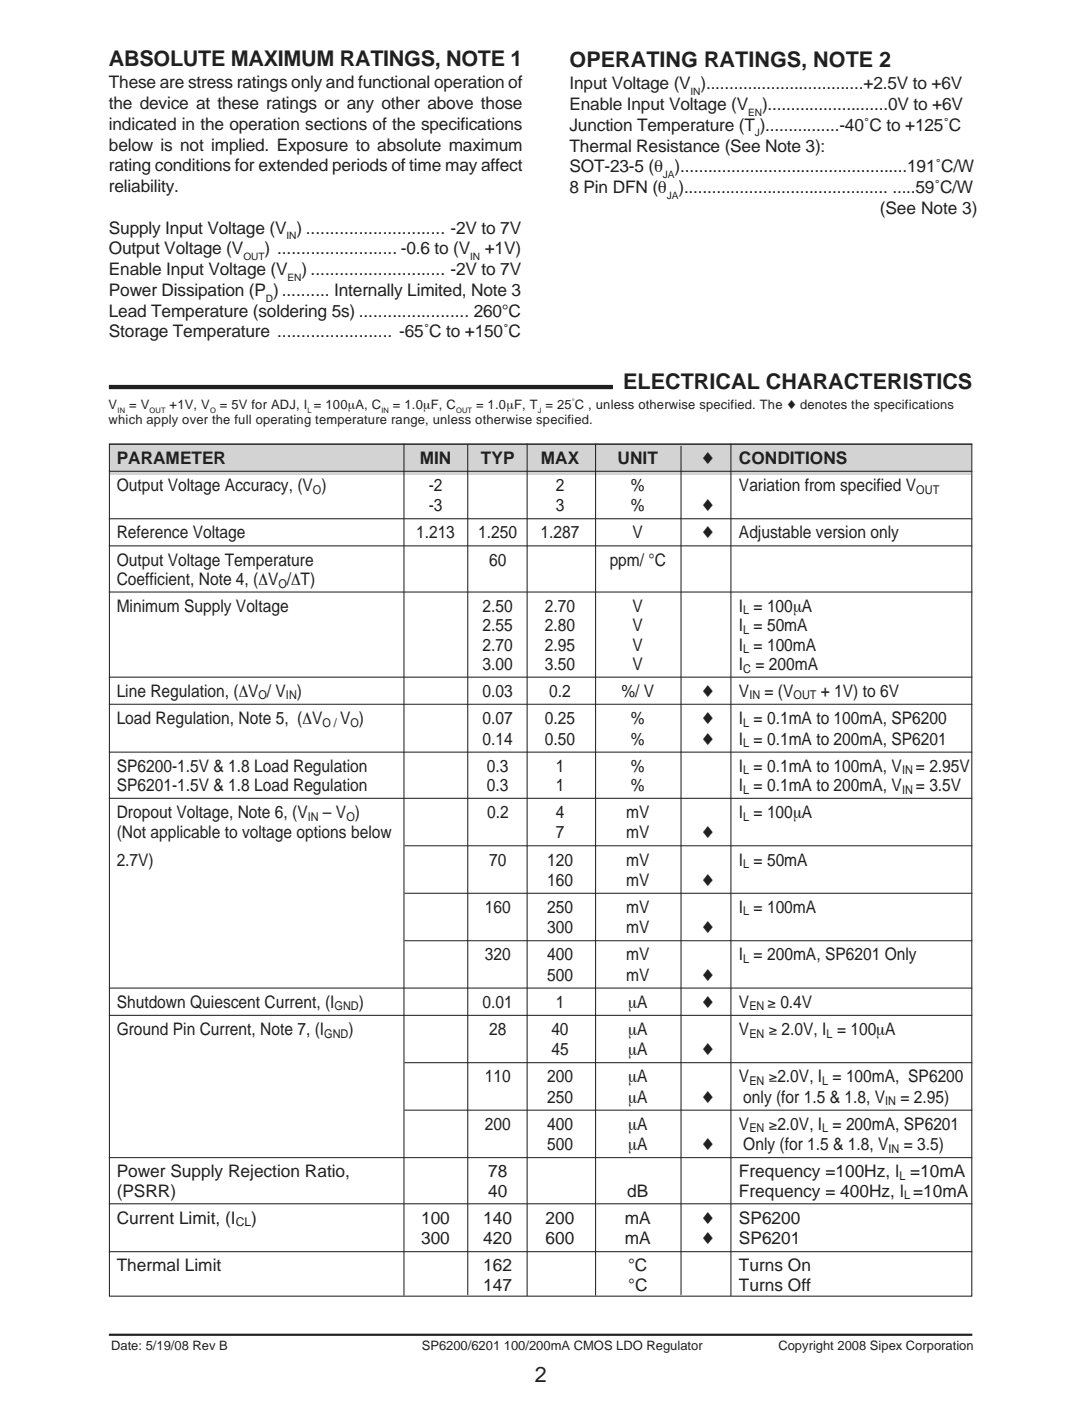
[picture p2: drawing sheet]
<svg xmlns="http://www.w3.org/2000/svg" width="178mm" height="229mm" viewBox="0 0 178 229" stroke-linecap="round" stroke-linejoin="round" font-family="sans-serif">
<defs><g id="words">
<g font-size="3.5" fill="#231f20">
<text x="17.8" y="10.8">ABSOLUTE MAXIMUM RATINGS, NOTE 1</text>
<text x="93" y="10.9">OPERATING RATINGS, NOTE 2</text>
<text x="101.7" y="63.5">ELECTRICAL CHARACTERISTICS</text>
<text x="87.3" y="225.6">2</text>
</g>
<g font-size="2.8" fill="#231f20">
<text x="17.8" y="14.4">These are stress ratings only and functional operation of</text>
<text x="17.8" y="17.8">the device at these ratings or any other above those</text>
<text x="93" y="14.6">Input Voltage (V )..................................+2.5V to +6V</text>
<text x="93" y="17.9">Enable Input Voltage (V</text>
<text x="124.4" y="17.9">)..........................0V to +6V</text>
<text x="17.8" y="21.2">indicated in the operation sections of the specifications</text>
<text x="93" y="21.3">Junction Temperature (T )................-40˚C to +125˚C</text>
<text x="17.8" y="24.6">below is not implied. Exposure to absolute maximum</text>
<text x="17.8" y="28">rating conditions for extended periods of time may affect</text>
<text x="93" y="24.7">Thermal Resistance (See Note 3):</text>
<text x="93" y="28.1">SOT-23-5 (θ ).................................................191˚C/W</text>
<text x="17.8" y="31.3">reliability.</text>
<text x="93" y="31.5">8 Pin DFN (θ )............................................ .....59˚C/W</text>
<text x="143.6" y="34.9">(See Note 3)</text>
<text x="17.8" y="41.5">Output Voltage (V</text>
<text x="17.8" y="38.1">Supply Input Voltage (V ) ............................. -2V to 7V</text>
<text x="43.2" y="41.5">) ......................... -0.6 to (V</text>
<text x="79.1" y="41.5">+1V)</text>
<text x="17.8" y="44.9">Enable Input Voltage (V</text>
<text x="49.2" y="44.9">) ............................ -2V to 7V</text>
<text x="17.8" y="48.3">Power Dissipation (P ).......... Internally Limited, Note 3</text>
<text x="17.8" y="51.7">Lead Temperature (soldering 5s) ....................... 260°C</text>
<text x="17.8" y="55.1">Storage Temperature ........................ -65˚C to +150˚C</text>
<text x="19" y="75.7">PARAMETER</text>
<text x="68.5" y="75.7">MIN</text>
<text x="78.5" y="75.7">TYP</text>
<text x="88.3" y="75.7">MAX</text>
<text x="100.8" y="75.7">UNIT</text>
<text x="114.5" y="75.7">♦</text>
<text x="120.6" y="75.7">CONDITIONS</text>
<text x="19" y="80.1">Output Voltage Accuracy, (V )</text>
<text x="70" y="83.4">-3</text>
<text x="70" y="80.1">-2</text>
<text x="90.7" y="83.4">3</text>
<text x="90.7" y="80.1">2</text>
<text x="103" y="83.4">%</text>
<text x="103" y="80.1">%</text>
<text x="114.5" y="83.4">♦</text>
<text x="120.7" y="80.1">Variation from specified V</text>
<text x="19" y="87.9">Reference Voltage</text>
<text x="67.9" y="87.9">1.213</text>
<text x="78.1" y="87.9">1.250</text>
<text x="88.3" y="87.9">1.287</text>
<text x="103.3" y="87.9">V</text>
<text x="114.5" y="87.9">♦</text>
<text x="120.6" y="87.9">Adjustable version only</text>
<text x="19" y="92.3">Output Voltage Temperature</text>
<text x="19.1" y="95.5">Coefficient, Note 4, (∆V /∆T)</text>
<text x="79.9" y="92.3">60</text>
<text x="99.5" y="92.3">ppm/ °C</text>
<text x="19" y="99.8">Minimum Supply Voltage</text>
<text x="78.8" y="99.8">2.50</text>
<text x="89" y="99.8">2.70</text>
<text x="103.3" y="99.8">V</text>
<text x="120.6" y="99.8">I = 100µA</text>
<text x="78.8" y="103">2.55</text>
<text x="78.8" y="106.2">2.70</text>
<text x="89" y="103">2.80</text>
<text x="89" y="106.2">2.95</text>
<text x="103.3" y="103">V</text>
<text x="103.3" y="106.2">V</text>
<text x="120.6" y="103">I = 50mA</text>
<text x="120.6" y="106.2">I = 100mA</text>
<text x="19" y="113.7">Line Regulation, (∆V / V )</text>
<text x="78.8" y="109.3">3.00</text>
<text x="78.8" y="113.7">0.03</text>
<text x="89" y="109.3">3.50</text>
<text x="89.7" y="113.7">0.2</text>
<text x="101.5" y="113.7">%/ V</text>
<text x="103.3" y="109.3">V</text>
<text x="114.5" y="113.7">♦</text>
<text x="120.6" y="109.3">I</text>
<text x="120.6" y="113.7">V</text>
<text x="123.3" y="109.3">= 200mA</text>
<text x="124.8" y="113.7">= (V</text>
<text x="134" y="113.7">+ 1V) to 6V</text>
<text x="19" y="118.1">Load Regulation, Note 5, (∆V</text>
<text x="55.5" y="118.1">V )</text>
<text x="78.8" y="118.1">0.07</text>
<text x="89" y="118.1">0.25</text>
<text x="103" y="118.1">%</text>
<text x="114.5" y="118.1">♦</text>
<text x="120.6" y="118.1">I = 0.1mA to 100mA, SP6200</text>
<text x="19" y="125.9">SP6200-1.5V &amp; 1.8 Load Regulation</text>
<text x="78.8" y="121.5">0.14</text>
<text x="79.5" y="125.9">0.3</text>
<text x="89" y="121.5">0.50</text>
<text x="90.7" y="125.9">1</text>
<text x="103" y="125.9">%</text>
<text x="103" y="121.5">%</text>
<text x="114.5" y="121.5">♦</text>
<text x="120.6" y="125.9">I = 0.1mA to 100mA, V</text>
<text x="120.6" y="121.5">I = 0.1mA to 200mA, SP6201</text>
<text x="149.5" y="125.9">= 2.95V</text>
<text x="19" y="129.1">SP6201-1.5V &amp; 1.8 Load Regulation</text>
<text x="79.5" y="129.1">0.3</text>
<text x="90.7" y="129.1">1</text>
<text x="103" y="129.1">%</text>
<text x="120.6" y="129.1">I = 0.1mA to 200mA, V</text>
<text x="149.5" y="129.1">= 3.5V</text>
<text x="19" y="136.8">(Not applicable to voltage options below</text>
<text x="19" y="133.5">Dropout Voltage, Note 6, (V</text>
<text x="52.7" y="133.5">– V )</text>
<text x="79.5" y="133.5">0.2</text>
<text x="90.7" y="136.8">7</text>
<text x="90.7" y="133.5">4</text>
<text x="102.2" y="136.8">mV</text>
<text x="102.2" y="133.5">mV</text>
<text x="114.5" y="136.8">♦</text>
<text x="120.6" y="133.5">I = 100µA</text>
<text x="19" y="141.2">2.7V)</text>
<text x="79.9" y="141.2">70</text>
<text x="89.3" y="141.2">120</text>
<text x="102.2" y="141.2">mV</text>
<text x="120.6" y="141.2">I = 50mA</text>
<text x="79.2" y="148.9">160</text>
<text x="89.3" y="148.9">250</text>
<text x="89.3" y="144.5">160</text>
<text x="102.2" y="148.9">mV</text>
<text x="102.2" y="144.5">mV</text>
<text x="114.5" y="144.5">♦</text>
<text x="120.6" y="148.9">I = 100mA</text>
<text x="89.3" y="152.3">300</text>
<text x="102.2" y="152.3">mV</text>
<text x="114.5" y="152.3">♦</text>
<text x="79.2" y="156.7">320</text>
<text x="89.3" y="156.7">400</text>
<text x="89.3" y="160">500</text>
<text x="102.2" y="156.7">mV</text>
<text x="102.2" y="160">mV</text>
<text x="114.5" y="160">♦</text>
<text x="120.6" y="156.7">I = 200mA, SP6201 Only</text>
<text x="19" y="164.4">Shutdown Quiescent Current, (I</text>
<text x="58.6" y="164.4">)</text>
<text x="78.8" y="164.4">0.01</text>
<text x="90.7" y="164.4">1</text>
<text x="102.6" y="164.4">µA</text>
<text x="114.5" y="164.4">♦</text>
<text x="120.6" y="164.4">V</text>
<text x="125.3" y="164.4">≥ 0.4V</text>
<text x="19" y="168.9">Ground Pin Current, Note 7, (I</text>
<text x="56.9" y="168.9">)</text>
<text x="79.9" y="168.9">28</text>
<text x="90" y="168.9">40</text>
<text x="90" y="172.2">45</text>
<text x="102.6" y="168.9">µA</text>
<text x="102.6" y="172.2">µA</text>
<text x="114.5" y="172.2">♦</text>
<text x="120.6" y="168.9">V</text>
<text x="125.5" y="168.9">≥ 2.0V, I = 100µA</text>
<text x="79.2" y="176.6">110</text>
<text x="89.3" y="176.6">200</text>
<text x="89.3" y="179.9">250</text>
<text x="102.6" y="176.6">µA</text>
<text x="102.6" y="179.9">µA</text>
<text x="114.5" y="179.9">♦</text>
<text x="120.6" y="176.6">V</text>
<text x="121.4" y="179.9">only (for 1.5 &amp; 1.8, V</text>
<text x="125.5" y="176.6">≥2.0V, I = 100mA, SP6200</text>
<text x="147" y="179.9">= 2.95)</text>
<text x="79.2" y="184.4">200</text>
<text x="89.3" y="184.4">400</text>
<text x="102.6" y="184.4">µA</text>
<text x="120.6" y="184.4">V</text>
<text x="125.5" y="184.4">≥2.0V, I = 200mA, SP6201</text>
<text x="89.3" y="187.7">500</text>
<text x="102.6" y="187.7">µA</text>
<text x="114.5" y="187.7">♦</text>
<text x="121.4" y="187.7">Only (for 1.5 &amp; 1.8, V</text>
<text x="147.6" y="187.7">= 3.5)</text>
<text x="19" y="192.1">Power Supply Rejection Ratio,</text>
<text x="19" y="195.3">(PSRR)</text>
<text x="79.7" y="192.1">78</text>
<text x="79.7" y="195.3">40</text>
<text x="102.4" y="195.3">dB</text>
<text x="120.6" y="192.1">Frequency =100Hz, I =10mA</text>
<text x="120.6" y="195.3">Frequency = 400Hz, I =10mA</text>
<text x="19" y="199.6">Current Limit, (I</text>
<text x="41" y="199.6">)</text>
<text x="68.7" y="199.6">100</text>
<text x="68.7" y="203">300</text>
<text x="78.9" y="199.6">140</text>
<text x="78.9" y="203">420</text>
<text x="89.1" y="199.6">200</text>
<text x="89.1" y="203">600</text>
<text x="102" y="199.6">mA</text>
<text x="102" y="203">mA</text>
<text x="114.5" y="199.6">♦</text>
<text x="114.5" y="203">♦</text>
<text x="120.6" y="199.6">SP6200</text>
<text x="120.6" y="203">SP6201</text>
<text x="19" y="207.5">Thermal Limit</text>
<text x="78.9" y="207.5">162</text>
<text x="102.6" y="207.5">°C</text>
<text x="120.6" y="207.5">Turns On</text>
<text x="78.9" y="210.6">147</text>
<text x="102.6" y="210.6">°C</text>
<text x="120.7" y="210.6">Turns Off</text>
</g>
<g font-size="2.1" fill="#231f20">
<text x="17.7" y="66.7">V</text>
<text x="17.7" y="69.3">which apply over the full operating temperature range, unless otherwise specified.</text>
<text x="21.1" y="66.7">= V</text>
<text x="27.7" y="66.7">+1V, V</text>
<text x="35.9" y="66.7">= 5V for ADJ, I = 100µA, C</text>
<text x="64.2" y="66.7">= 1.0µF, C</text>
<text x="77.7" y="66.7">= 1.0µF, T = 25 C , unless otherwise specified. The ♦ denotes the specifications</text>
<text x="18.1" y="220.2">Date: 5/19/08 Rev B</text>
<text x="68.9" y="220.2">SP6200/6201 100/200mA CMOS LDO Regulator</text>
<text x="127.1" y="220.2">Copyright 2008 Sipex Corporation</text>
</g>
<g font-size="2" fill="#231f20">
<text x="51.1" y="80.5">O</text>
<text x="149.6" y="80.5">OUT</text>
<text x="45.5" y="95.9">O</text>
<text x="121.3" y="100.2">L</text>
<text x="121.3" y="103.4">L</text>
<text x="121.3" y="106.6">L</text>
<text x="121.3" y="109.8">C</text>
<text x="42.2" y="114.1">O</text>
<text x="46.7" y="114.1">IN</text>
<text x="52.6" y="118.6">O /</text>
<text x="57.2" y="118.6">O</text>
<text x="121.3" y="118.6">L</text>
<text x="122.3" y="114.1">IN</text>
<text x="129.6" y="114.1">OUT</text>
<text x="121.3" y="121.9">L</text>
<text x="121.3" y="126.4">L</text>
<text x="121.3" y="129.5">L</text>
<text x="147.3" y="126.4">IN</text>
<text x="147.3" y="129.5">IN</text>
<text x="50.2" y="133.9">IN</text>
<text x="56.6" y="133.9">O</text>
<text x="121.3" y="133.9">L</text>
<text x="121.3" y="141.6">L</text>
<text x="121.3" y="149.4">L</text>
<text x="121.3" y="157.1">L</text>
<text x="54.6" y="164.9">GND</text>
<text x="122.3" y="164.9">EN</text>
<text x="52.9" y="169.3">GND</text>
<text x="122.3" y="169.3">EN</text>
<text x="135" y="169.3">L</text>
<text x="122.3" y="177">EN</text>
<text x="134.3" y="177">L</text>
<text x="122.3" y="184.8">EN</text>
<text x="134.3" y="184.8">L</text>
<text x="144.5" y="180.4">IN</text>
<text x="145.1" y="188.1">IN</text>
<text x="146.9" y="192.5">L</text>
<text x="147.6" y="195.7">L</text>
<text x="38.5" y="200.1">CL</text>
</g>
<g font-size="1.7" fill="#231f20">
<text x="112.8" y="15.5">IN</text>
<text x="122.1" y="18.9">EN</text>
<text x="123.2" y="22.3">J</text>
<text x="108.2" y="29">JA</text>
<text x="108.9" y="32.4">JA</text>
<text x="46.8" y="39.1">IN</text>
<text x="39.7" y="42.4">OUT</text>
<text x="46.9" y="45.8">EN</text>
<text x="76.8" y="42.4">IN</text>
<text x="43.4" y="49.2">D</text>
</g>
<g font-size="1.2" fill="#231f20">
<text x="93.4" y="66">°</text>
<text x="19.2" y="67.4">IN</text>
<text x="24.4" y="67.4">OUT</text>
<text x="34.3" y="67.4">O</text>
<text x="50.2" y="67.4">L</text>
<text x="62.3" y="67.4">IN</text>
<text x="74.5" y="67.4">OUT</text>
<text x="87.8" y="67.4">J</text>
</g>
</g></defs>
<path d="M17.8 217.8h140.9" fill="none" stroke="#231f20" stroke-width=".36"/>
<path d="M18 72.6h140.5v4.9h-140.5z" fill="#d1d3d4"/>
<g fill="none" stroke="#231f20" stroke-width=".17">
<path d="M17.8 72.5h140.9M17.8 76.9h140.9M17.9 72.5h140.8v139h-140.8zM66 72.4v139M76.4 72.5v138.8M86.1 72.4v139.1M97.2 72.4v139M111.2 72.7v138.6M119.3 72.4v139.1M17.8 84.6h140.9M17.8 89.1h140.9M17.8 96.6h140.9"/>
<path d="M17.8 110.5h140.9M17.8 114.9h140.9M17.8 122.7h140.9M17.8 130.3h140.9M66 138h92.7M66 145.8h92.7M66 153.5h92.7M17.8 161.2h140.9M17.8 165.7h140.9M66 173.4h92.7M17.8 188.9h140.9M17.8 196.4h140.9"/>
<path d="M66 181.1h92.7M17.8 204.2h140.9"/>
</g>
<path d="M17.8 63.2h82.3" fill="none" stroke="#231f20" stroke-width=".7" stroke-linecap="butt"/>
<use href="#words"/>
</svg>
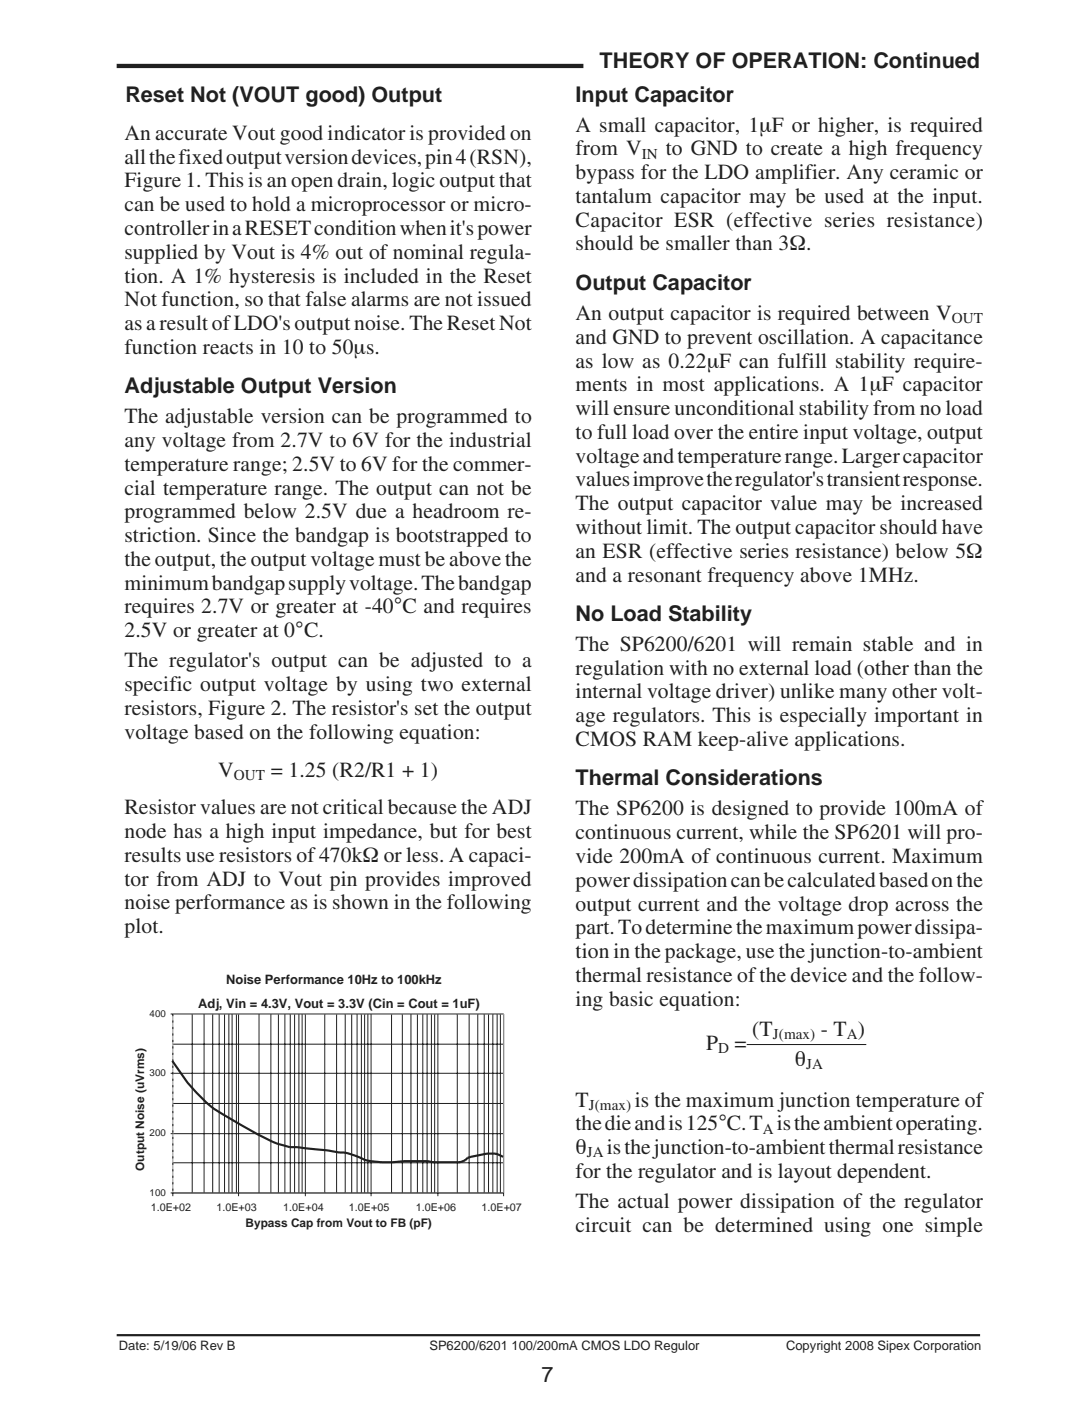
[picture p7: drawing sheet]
<svg xmlns="http://www.w3.org/2000/svg" width="178mm" height="229mm" viewBox="0 0 178 229" stroke-linecap="round" stroke-linejoin="round" font-family="sans-serif">
<defs><g id="words">
<g font-size="3.5" fill="#231f20">
<text x="97.9" y="11">THEORY OF OPERATION: Continued</text>
<text x="20.5" y="16.7">Reset Not (VOUT good) Output</text>
<text x="94" y="16.6">Input Capacitor</text>
<text x="20.3" y="22.8">An accurate Vout good indicator is provided on</text>
<text x="94" y="21.5">A small capacitor, 1µF or higher, is required</text>
<text x="20.3" y="26.7">all the fixed output version devices, pin 4 (RSN),</text>
<text x="94" y="25.4">from V</text>
<text x="94" y="29.2">bypass for the LDO amplifier. Any ceramic or</text>
<text x="108.7" y="25.4">to GND to create a high frequency</text>
<text x="20.3" y="30.6">Figure 1. This is an open drain, logic output that</text>
<text x="20.3" y="34.5">can be used to hold a microprocessor or micro-</text>
<text x="94" y="33.1">tantalum capacitor may be used at the input.</text>
<text x="20.3" y="38.3">controller in a RESET condition when it's power</text>
<text x="94" y="37">Capacitor ESR (effective series resistance)</text>
<text x="94" y="40.9">should be smaller than 3Ω.</text>
<text x="20.3" y="42.2">supplied by Vout is 4% out of nominal regula-</text>
<text x="20.3" y="46.1">tion. A 1% hysteresis is included in the Reset</text>
<text x="94" y="47.3">Output Capacitor</text>
<text x="20.3" y="50">Not function, so that false alarms are not issued</text>
<text x="20.3" y="53.8">as a result of LDO's output noise. The Reset Not</text>
<text x="94" y="52.2">An output capacitor is required between V</text>
<text x="20.3" y="57.7">function reacts in 10 to 50µs.</text>
<text x="94" y="56.1">and GND to prevent oscillation. A capacitance</text>
<text x="94" y="60">as low as 0.22µF can fulfill stability require-</text>
<text x="20.3" y="64.2">Adjustable Output Version</text>
<text x="94" y="63.8">ments in most applications. A 1µF capacitor</text>
<text x="20.3" y="69.1">The adjustable version can be programmed to</text>
<text x="94" y="67.7">will ensure unconditional stability from no load</text>
<text x="94" y="71.6">to full load over the entire input voltage, output</text>
<text x="20.3" y="72.9">any voltage from 2.7V to 6V for the industrial</text>
<text x="20.3" y="76.8">temperature range; 2.5V to 6V for the commer-</text>
<text x="94" y="75.5">voltage and temperature range. Larger capacitor</text>
<text x="20.3" y="80.7">cial temperature range. The output can not be</text>
<text x="94" y="79.4">values improve the regulator's transient response.</text>
<text x="94" y="83.2">The output capacitor value may be increased</text>
<text x="20.3" y="84.6">programmed below 2.5V due a headroom re-</text>
<text x="20.3" y="88.5">striction. Since the bandgap is bootstrapped to</text>
<text x="94" y="87.1">without limit. The output capacitor should have</text>
<text x="20.3" y="92.4">the output, the output voltage must be above the</text>
<text x="94" y="91">an ESR (effective series resistance) below 5Ω</text>
<text x="94" y="94.9">and a resonant frequency above 1MHz.</text>
<text x="20.3" y="96.2">minimum bandgap supply voltage. The bandgap</text>
<text x="20.3" y="100.1">requires 2.7V or greater at -40°C and requires</text>
<text x="94" y="101.3">No Load Stability</text>
<text x="20.3" y="104">2.5V or greater at 0°C.</text>
<text x="94" y="106.2">The SP6200/6201 will remain stable and in</text>
<text x="20.3" y="108.9">The regulator's output can be adjusted to a</text>
<text x="20.3" y="112.8">specific output voltage by using two external</text>
<text x="94" y="110.1">regulation with no external load (other than the</text>
<text x="94" y="114">internal voltage driver) unlike many other volt-</text>
<text x="20.3" y="116.6">resistors, Figure 2. The resistor's set the output</text>
<text x="94" y="117.8">age regulators. This is especially important in</text>
<text x="20.3" y="120.5">voltage based on the following equation:</text>
<text x="94" y="121.7">CMOS RAM keep-alive applications.</text>
<text x="35.6" y="126.7">V</text>
<text x="44.2" y="126.7">= 1.25 (R2/R1 + 1)</text>
<text x="94" y="128.1">Thermal Considerations</text>
<text x="20.3" y="132.9">Resistor values are not critical because the ADJ</text>
<text x="20.3" y="136.8">node has a high input impedance, but for best</text>
<text x="94" y="133.1">The SP6200 is designed to provide 100mA of</text>
<text x="94" y="136.9">continuous current, while the SP6201 will pro-</text>
<text x="20.3" y="140.6">results use resistors of 470kΩ or less. A capaci-</text>
<text x="94" y="140.8">vide 200mA of continuous current. Maximum</text>
<text x="20.3" y="144.5">tor from ADJ to Vout pin provides improved</text>
<text x="20.3" y="148.4">noise performance as is shown in the following</text>
<text x="94" y="144.7">power dissipation can be calculated based on the</text>
<text x="94" y="148.6">output current and the voltage drop across the</text>
<text x="20.3" y="152.3">plot.</text>
<text x="94" y="152.4">part. To determine the maximum power dissipa-</text>
<text x="94" y="156.3">tion in the package, use the junction-to-ambient</text>
<text x="94" y="160.2">thermal resistance of the device and the follow-</text>
<text x="94" y="164.1">ing basic equation:</text>
<text x="115.3" y="171.3">P</text>
<text x="119.9" y="171.3">=</text>
<text x="122.8" y="169">(T</text>
<text x="129.8" y="173.9">θ</text>
<text x="134" y="169">- T )</text>
<text x="94" y="180.6">T</text>
<text x="94" y="184.4">the die and is 125°C. T is the ambient operating.</text>
<text x="103.7" y="180.6">is the maximum junction temperature of</text>
<text x="94" y="188.3">θ</text>
<text x="99.1" y="188.3">is the junction-to-ambient thermal resistance</text>
<text x="94" y="192.2">for the regulator and is layout dependent.</text>
<text x="94" y="197.1">The actual power dissipation of the regulator</text>
<text x="94" y="201">circuit can be determined using one simple</text>
<text x="88.4" y="225.5">7</text>
</g>
<g font-size="2.5" fill="#231f20">
<text x="104.8" y="25.9">IN</text>
<text x="155.4" y="52.7">OUT</text>
<text x="38.2" y="127.2">OUT</text>
<text x="117.2" y="171.8">D</text>
<text x="126.2" y="169.5">J(max)</text>
<text x="138.3" y="169.5">A</text>
<text x="131.6" y="174.4">JA</text>
<text x="96.1" y="181.1">J(max)</text>
<text x="124.6" y="185">A</text>
<text x="95.8" y="188.8">JA</text>
</g>
<g font-size="2.1" fill="#231f20">
<text x="36.9" y="160.6">Noise Performance 10Hz to 100kHz</text>
<text x="32.4" y="164.5">Adj, Vin = 4.3V, Vout = 3.3V (Cin = Cout = 1uF)</text>
<text x="19.4" y="220.2">Date: 5/19/06 Rev B</text>
<text x="70.1" y="220.2">SP6200/6201 100/200mA CMOS LDO Regulor</text>
<text x="128.3" y="220.2">Copyright 2008 Sipex Corporation</text>
</g>
<g font-size="1.9" fill="#231f20">
<text x="23.5" y="191" transform="rotate(-90 23.5 191)">Output Noise (uVrms)</text>
<text x="40.1" y="200.2">Bypass Cap from Vout to FB (pF)</text>
</g>
<g font-size="1.8" fill="#231f20">
<text x="24.6" y="197.6">1.0E+02</text>
<text x="35.3" y="197.6">1.0E+03</text>
<text x="46.2" y="197.6">1.0E+04</text>
<text x="57" y="197.6">1.0E+05</text>
<text x="67.9" y="197.6">1.0E+06</text>
<text x="78.6" y="197.6">1.0E+07</text>
</g>
<g font-size="1.6" fill="#231f20">
<text x="24.4" y="165.9">400</text>
<text x="24.4" y="175.6">300</text>
<text x="24.4" y="185.4">200</text>
<text x="24.4" y="195.1">100</text>
</g>
</g></defs>
<path d="M19 217.9h141" fill="none" stroke="#231f20" stroke-width=".36"/>
<g fill="none" stroke="#231f20" stroke-width=".16">
<path d="M27.9 175.1h54.3M27.9 165.5h54.3v29.7M28.2 170.4h54M28.2 165.5v.3M28.2 166.5v.4M28.2 167.6v.3M28.2 168.6v.4M28.2 169.7v.3M28.2 170.7v.4M28.2 171.8v.3M28.2 172.8v.4M28.2 173.9v.3"/>
<path d="M28.2 175v.3M28.2 176v.4M28.2 177.1v.3M28.2 178.1v.4M28.2 179.2v.3M31.4 165.5v29.2M33.3 165.5v29.2M34.7 165.5v29.2M35.8 165.5v29.2M36.7 165.5v29.2M37.4 165.5v29.2M37.9 165.5v29.2"/>
<path d="M38.6 165.5v29.2M38.9 165.5v29.7M42.3 165.5v29.2M44.2 165.5v29.2M45.5 165.5v29.2M46.5 165.5v29.2M47.4 165.5v29.2M48.1 165.5v29.2M48.8 165.5v29.2M49.3 165.5v29.2M49.9 165.5v29.7M53 165.5v29.2"/>
<path d="M55 165.5v29.2M56.4 165.5v29.2M57.4 165.5v29.2M58.3 165.5v29.2M59 165.5v29.2M59.5 165.5v29.2M60.1 165.5v29.2M60.6 165.5v29.7M63.9 165.5v29.2M65.7 165.5v29.2M67.1 165.5v29.2M68.2 165.5v29.2"/>
<path d="M69 165.5v29.2M69.7 165.5v29.2M70.4 165.5v29.2M71 165.5v29.2M71.5 165.5v29.7M74.7 165.5v29.2M76.6 165.5v29.2M78 165.5v29.2M79.1 165.5v29.2M79.8 165.5v29.2M80.5 165.5v29.2M81.2 165.5v29.2"/>
<path d="M81.7 165.5v29.2M27.9 185h54.3M27.9 194.7h54.3M28.2 180.1h54M28.2 180.2v.4M28.2 181.3v.3M28.2 182.3v.4M28.2 183.4v.3M28.2 184.5v.3M28.2 185.5v.4M28.2 186.6v.3M28.2 187.6v.4"/>
<path d="M28.2 188.7v.3M28.2 190.8v.3M28.2 191.8v.4M28.2 192.9v.3M28.2 194v.3M28.2 194.7v.5M82.2 189.7h-54v.4"/>
</g>
<path d="M28.2 165.5h54v29.2h-54z" fill="none" stroke="#949698" stroke-width=".18"/>
<path d="M28.1 173.1a24.8 24.8 0 0 0 11.1 10.4l2.8 1.6a16.2 16.2 0 0 0 5.3 2.1h1.2l5 .5 1.9 .4a8.3 8.3 0 0 1 4.2 1.2 17.7 17.7 0 0 0 6.4 .2h3.8l.9 .1h4.4l1.8-.8 2.6-.6h1.4l1.2 .6" fill="none" stroke="#231f20" stroke-width=".35"/>
<path d="M19 10.8h76.2" fill="none" stroke="#231f20" stroke-width=".7" stroke-linecap="butt"/>
<path d="M121.9 170.4h19.5" fill="none" stroke="#231f20" stroke-width=".17"/>
<use href="#words"/>
</svg>
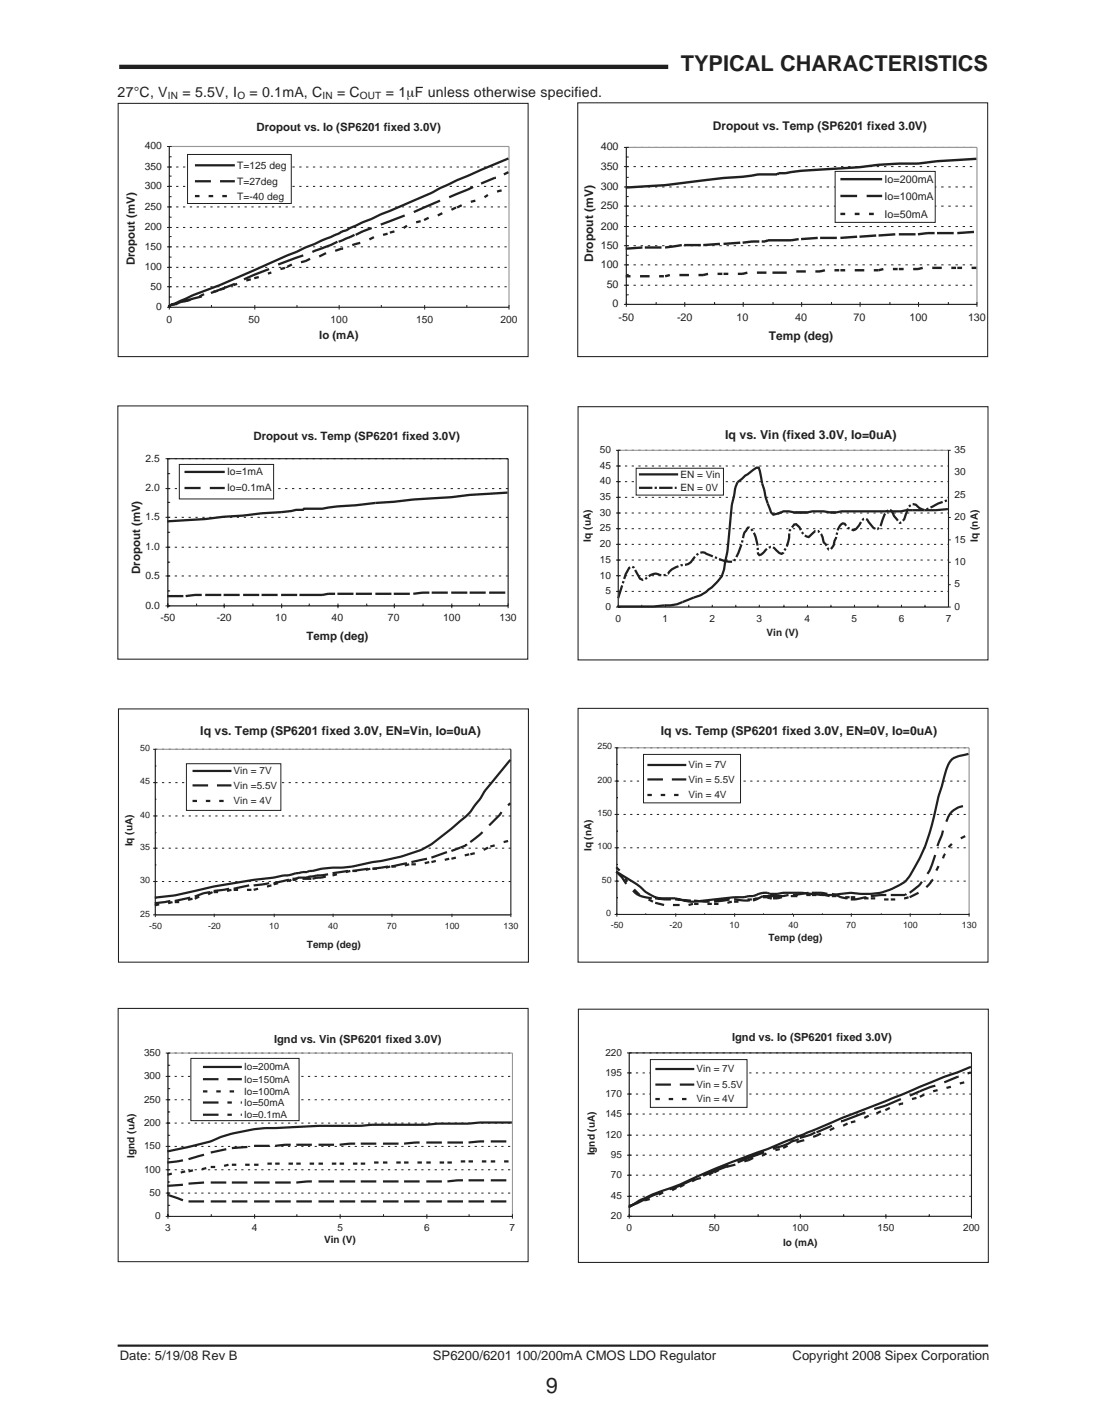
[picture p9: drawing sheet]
<svg xmlns="http://www.w3.org/2000/svg" width="178mm" height="229mm" viewBox="0 0 178 229" stroke-linecap="round" stroke-linejoin="round" font-family="sans-serif">
<defs><g id="words">
<g font-size="3.5" fill="#231f20">
<text x="110.2" y="11.5">TYPICAL CHARACTERISTICS</text>
<text x="88.4" y="225.5">9</text>
</g>
<g font-size="2.3" fill="#231f20">
<text x="19" y="15.7">27°C, V</text>
<text x="29.5" y="15.7">= 5.5V, I</text>
<text x="40.4" y="15.7">= 0.1mA, C</text>
<text x="54.6" y="15.7">= C</text>
<text x="62.5" y="15.7">= 1µF unless otherwise specified.</text>
</g>
<g font-size="2.1" fill="#231f20">
<text x="19.4" y="220.2">Date: 5/19/08 Rev B</text>
<text x="70.1" y="220.2">SP6200/6201 100/200mA CMOS LDO Regulator</text>
<text x="128.3" y="220.2">Copyright 2008 Sipex Corporation</text>
</g>
<g font-size="2" fill="#231f20">
<text x="117.4" y="71">Iq vs. Vin (fixed 3.0V, Io=0uA)</text>
<text x="32.4" y="119.1">Iq vs. Temp (SP6201 fixed 3.0V, EN=Vin, Io=0uA)</text>
<text x="107" y="119">Iq vs. Temp (SP6201 fixed 3.0V, EN=0V, Io=0uA)</text>
</g>
<g font-size="1.9" fill="#231f20">
<text x="115.4" y="21.1">Dropout vs. Temp (SP6201 fixed 3.0V)</text>
<text x="96.1" y="42.4" transform="rotate(-90 96.1 42.4)">Dropout (mV)</text>
<text x="124.5" y="55">Temp (deg)</text>
<text x="41" y="71.2">Dropout vs. Temp (SP6201 fixed 3.0V)</text>
<text x="22.7" y="93" transform="rotate(-90 22.7 93)">Dropout (mV)</text>
<text x="49.6" y="103.6">Temp (deg)</text>
</g>
<g font-size="1.8" fill="#231f20">
<text x="41.5" y="21.2">Dropout vs. Io (SP6201 fixed 3.0V)</text>
<text x="21.8" y="42.9" transform="rotate(-90 21.8 42.9)">Dropout (mV)</text>
<text x="51.7" y="54.8">Io (mA)</text>
<text x="44.4" y="168.8">Ignd vs. Vin (SP6201 fixed 3.0V)</text>
<text x="118.5" y="168.6">Ignd vs. Io (SP6201 fixed 3.0V)</text>
</g>
<g font-size="1.7" fill="#231f20">
<text x="23.4" y="27.5">350</text>
<text x="23.4" y="24.2">400</text>
<text x="38.4" y="27.3">T=125 deg</text>
<text x="38.4" y="29.9">T=27deg</text>
<text x="97.3" y="27.5">350</text>
<text x="97.3" y="24.4">400</text>
<text x="143.2" y="29.6">Io=200mA</text>
<text x="23.4" y="34">250</text>
<text x="23.4" y="30.6">300</text>
<text x="38.4" y="32.3">T=-40 deg</text>
<text x="97.3" y="33.9">250</text>
<text x="97.3" y="30.8">300</text>
<text x="143.2" y="32.3">Io=100mA</text>
<text x="143.2" y="35.2">Io=50mA</text>
<text x="23.4" y="40.4">150</text>
<text x="23.4" y="37.3">200</text>
<text x="97.3" y="40.3">150</text>
<text x="97.3" y="37.2">200</text>
<text x="23.4" y="43.7">100</text>
<text x="24.4" y="46.9">50</text>
<text x="97.3" y="43.4">100</text>
<text x="98.2" y="46.7">50</text>
<text x="25.3" y="50.2">0</text>
<text x="27" y="52.2">0</text>
<text x="40.2" y="52.2">50</text>
<text x="53.5" y="52.2">100</text>
<text x="67.4" y="52.2">150</text>
<text x="81" y="52.2">200</text>
<text x="99.2" y="49.8">0</text>
<text x="100.2" y="51.9">-50</text>
<text x="109.6" y="51.9">-20</text>
<text x="119.3" y="51.9">10</text>
<text x="128.8" y="51.9">40</text>
<text x="138.2" y="51.9">70</text>
<text x="147.3" y="51.9">100</text>
<text x="156.8" y="51.9">130</text>
<text x="23.5" y="74.7">2.5</text>
<text x="36.8" y="77">Io=1mA</text>
<text x="23.5" y="79.6">2.0</text>
<text x="36.8" y="79.6">Io=0.1mA</text>
<text x="23.5" y="89.1">1.0</text>
<text x="23.5" y="84.2">1.5</text>
<text x="23.5" y="93.7">0.5</text>
<text x="23.5" y="98.6">0.0</text>
<text x="26" y="100.6">-50</text>
<text x="35.1" y="100.6">-20</text>
<text x="44.6" y="100.6">10</text>
<text x="53.7" y="100.6">40</text>
<text x="62.8" y="100.6">70</text>
<text x="71.8" y="100.6">100</text>
<text x="80.9" y="100.6">130</text>
</g>
<g font-size="1.6" fill="#231f20">
<text x="27.2" y="16">IN</text>
<text x="38.4" y="16">O</text>
<text x="52.2" y="16">IN</text>
<text x="58.3" y="16">OUT</text>
<text x="97.1" y="75.9">45</text>
<text x="97.1" y="73.4">50</text>
<text x="110.2" y="77.3">EN = Vin</text>
<text x="154.6" y="77">30</text>
<text x="154.6" y="73.4">35</text>
<text x="97.1" y="83.5">30</text>
<text x="97.1" y="81">35</text>
<text x="97.1" y="78.4">40</text>
<text x="110.2" y="79.5">EN = 0V</text>
<text x="154.6" y="80.6">25</text>
<text x="95.7" y="87.7" transform="rotate(-90 95.7 87.7)">Iq (uA)</text>
<text x="97.1" y="88.6">20</text>
<text x="97.1" y="86">25</text>
<text x="154.6" y="87.9">15</text>
<text x="154.6" y="84.2">20</text>
<text x="158.3" y="87.7" transform="rotate(-90 158.3 87.7)">Iq (nA)</text>
<text x="97.1" y="93.7">10</text>
<text x="97.1" y="91.1">15</text>
<text x="154.6" y="95.1">5</text>
<text x="154.6" y="91.5">10</text>
<text x="98" y="98.7">0</text>
<text x="98" y="96.2">5</text>
<text x="99.7" y="100.7">0</text>
<text x="107.3" y="100.7">1</text>
<text x="114.9" y="100.7">2</text>
<text x="122.5" y="100.7">3</text>
<text x="130.3" y="100.7">4</text>
<text x="137.9" y="100.7">5</text>
<text x="145.5" y="100.7">6</text>
<text x="153.1" y="100.7">7</text>
<text x="154.6" y="98.7">0</text>
<text x="124.1" y="102.9">Vin (V)</text>
<text x="37.8" y="125.4">Vin = 7V</text>
<text x="111.5" y="124.4">Vin = 7V</text>
<text x="37.8" y="127.7">Vin =5.5V</text>
<text x="37.8" y="130.2">Vin = 4V</text>
<text x="111.5" y="126.7">Vin = 5.5V</text>
<text x="111.5" y="129.2">Vin = 4V</text>
<text x="21.5" y="137" transform="rotate(-90 21.5 137)">Iq (uA)</text>
<text x="95.8" y="137.8" transform="rotate(-90 95.8 137.8)">Iq (nA)</text>
<text x="49.7" y="153.5">Temp (deg)</text>
<text x="124.4" y="152.3">Temp (deg)</text>
<text x="23.3" y="170.9">350</text>
<text x="39.5" y="173.3">Io=200mA</text>
<text x="98" y="170.9">220</text>
<text x="112.8" y="173.6">Vin = 7V</text>
<text x="23.3" y="178.5">250</text>
<text x="23.3" y="174.7">300</text>
<text x="39.5" y="175.3">Io=150mA</text>
<text x="39.5" y="177.2">Io=100mA</text>
<text x="39.5" y="179">Io=50mA</text>
<text x="98" y="177.6">170</text>
<text x="98" y="174.2">195</text>
<text x="112.8" y="176.1">Vin = 5.5V</text>
<text x="112.8" y="178.5">Vin = 4V</text>
<text x="23.3" y="182.3">200</text>
<text x="39.5" y="181">Io=0.1mA</text>
<text x="98" y="184.2">120</text>
<text x="98" y="180.8">145</text>
<text x="21.8" y="187.4" transform="rotate(-90 21.8 187.4)">Ignd (uA)</text>
<text x="23.3" y="189.8">100</text>
<text x="23.3" y="186.1">150</text>
<text x="96.3" y="187.1" transform="rotate(-90 96.3 187.1)">Ignd (uA)</text>
<text x="98.9" y="190.7">70</text>
<text x="98.9" y="187.5">95</text>
<text x="24.2" y="193.6">50</text>
<text x="25.1" y="197.4">0</text>
<text x="98.9" y="197.4">20</text>
<text x="98.9" y="194.1">45</text>
<text x="26.7" y="199.4">3</text>
<text x="40.8" y="199.4">4</text>
<text x="52.5" y="201.3">Vin (V)</text>
<text x="54.6" y="199.4">5</text>
<text x="68.7" y="199.4">6</text>
<text x="82.5" y="199.4">7</text>
<text x="101.4" y="199.3">0</text>
<text x="114.8" y="199.3">50</text>
<text x="126.8" y="201.7">Io (mA)</text>
<text x="128.3" y="199.3">100</text>
<text x="142.1" y="199.3">150</text>
<text x="156" y="199.3">200</text>
</g>
<g font-size="1.4" fill="#231f20">
<text x="22.7" y="121.6">50</text>
<text x="96.7" y="121.3">250</text>
<text x="22.7" y="127">45</text>
<text x="96.7" y="126.7">200</text>
<text x="22.7" y="137.6">35</text>
<text x="22.7" y="132.4">40</text>
<text x="96.7" y="137.5">100</text>
<text x="96.7" y="132.1">150</text>
<text x="22.7" y="143">30</text>
<text x="97.5" y="142.9">50</text>
<text x="22.7" y="148.4">25</text>
<text x="98.2" y="148.3">0</text>
<text x="24.2" y="150.4">-50</text>
<text x="33.7" y="150.4">-20</text>
<text x="43.6" y="150.4">10</text>
<text x="53.1" y="150.4">40</text>
<text x="62.7" y="150.4">70</text>
<text x="72" y="150.4">100</text>
<text x="81.6" y="150.4">130</text>
<text x="98.9" y="150.3">-50</text>
<text x="108.4" y="150.3">-20</text>
<text x="118.2" y="150.3">10</text>
<text x="127.7" y="150.3">40</text>
<text x="137" y="150.3">70</text>
<text x="146.2" y="150.3">100</text>
<text x="155.8" y="150.3">130</text>
</g>
</g></defs>
<path d="M19 217.9h141" fill="none" stroke="#231f20" stroke-width=".36"/>
<path d="M19.1 16.7h66.4v41h-66.4zM93.6 16.6h66.3v41.1h-66.3zM19.1 65.7h66.4v41h-66.4zM93.6 65.8h66.4v41h-66.4z" fill="none" stroke="#231f20" stroke-width=".17"/>
<g fill="none" stroke="#231f20" stroke-width=".16">
<path d="M27 40h.8M27 36.8h.8M27 33.5h.8M27 30.2h.8M27 27h.8M27 23.7h.8M27.4 23.7v26.4M27.4 38.3h.4M27.4 35.2h.4M27.4 31.8h.4M27.4 28.5h.4M27.4 25.4h.4"/>
<path d="M28.5 40h.4M28.5 36.8h.4M28.5 33.5h.4M28.5 30.2h.4M28.5 27h.4M28.5 23.7h.4M29.6 40h.4M29.6 36.8h.4M29.6 33.5h.4M29.6 30.2h.4M29.6 27h.4M29.6 23.7h.4"/>
<path d="M30.7 40h.4M30.7 36.8h.4M30.7 33.5h.4M30.7 30.2h.4M30.7 27h.4M30.7 23.7h.4M31.8 40h.4M31.8 36.8h.4M31.8 33.5h.4M31.8 30.2h.4M31.8 27h.4M31.8 23.7h.4"/>
<path d="M33 40h.3M33 36.8h.3M33 33.5h.3M33 30.2h.3M33 27h.3M33 23.7h.3M34.1 40h.3M34.1 36.8h.3M34.1 33.5h.3M34.1 30.2h.3M34.1 27h.3M34.1 23.7h.3"/>
<path d="M35.2 40h.3M35.2 36.8h.3M35.2 33.5h.3M35.2 30.2h.3M35.2 27h.3M35.2 23.7h.3M36.3 40h.3M36.3 36.8h.3M36.3 33.5h.3M36.3 30.2h.3M36.3 27h.3M36.3 23.7h.3"/>
<path d="M37.4 40h.4M37.4 36.8h.4M37.4 33.5h.4M37.4 30.2h.4M37.4 27h.4M37.4 23.7h.4M38.5 40h.4M38.5 36.8h.4M38.5 33.5h.4M38.5 30.2h.4M38.5 27h.4M38.5 23.7h.4"/>
<path d="M39.6 40h.4M39.6 36.8h.4M39.6 33.5h.4M39.6 30.2h.4M39.6 27h.4M39.6 23.7h.4M40.7 40h.4M40.7 36.8h.4M40.7 33.5h.4M40.7 30.2h.4M40.7 27h.4M40.7 23.7h.4"/>
<path d="M41.8 40h.4M41.8 36.8h.4M41.8 33.5h.4M41.8 30.2h.4M41.8 27h.4M41.8 23.7h.4M42.9 40h.4M42.9 36.8h.4M42.9 33.5h.4M42.9 30.2h.4M42.9 27h.4M42.9 23.7h.4"/>
<path d="M44 40h.4M44 36.8h.4M44 33.5h.4M44 30.2h.4M44 27h.4M44 23.7h.4M45.1 40h.4M45.1 36.8h.4M45.1 33.5h.4M45.1 30.2h.4M45.1 27h.4M45.1 23.7h.4"/>
<path d="M46.2 40h.4M46.2 36.8h.4M46.2 33.5h.4M46.2 30.2h.4M46.2 27h.4M46.2 23.7h.4M47.4 40h.3M47.4 36.8h.3M47.4 33.5h.3M47.4 30.2h.3M47.4 27h.3M47.4 23.7h.3"/>
<path d="M48.5 40h.3M48.5 36.8h.3M48.5 33.5h.3M48.5 30.2h.3M48.5 27h.3M48.5 23.7h.3M49.6 40h.3M49.6 36.8h.3M49.6 33.5h.3M49.6 30.2h.3M49.6 27h.3M49.6 23.7h.3"/>
<path d="M50.7 40h.3M50.7 36.8h.3M50.7 33.5h.3M50.7 30.2h.3M50.7 27h.3M50.7 23.7h.3M51.8 40h.4M51.8 36.8h.4M51.8 33.5h.4M51.8 30.2h.4M51.8 27h.4M51.8 23.7h.4"/>
<path d="M52.9 40h.4M52.9 36.8h.4M52.9 33.5h.4M52.9 30.2h.4M52.9 27h.4M52.9 23.7h.4M54 40h.4M54 36.8h.4M54 33.5h.4M54 30.2h.4M54 27h.4M54 23.7h.4"/>
<path d="M55.1 40h.4M55.1 36.8h.4M55.1 33.5h.4M55.1 30.2h.4M55.1 27h.4M55.1 23.7h.4M56.2 40h.4M56.2 36.8h.4M56.2 33.5h.4M56.2 30.2h.4M56.2 27h.4M56.2 23.7h.4"/>
<path d="M57.3 40h.4M57.3 36.8h.4M57.3 33.5h.4M57.3 30.2h.4M57.3 27h.4M57.3 23.7h.4M58.4 40h.4M58.4 36.8h.4M58.4 33.5h.4M58.4 30.2h.4M58.4 27h.4M58.4 23.7h.4"/>
<path d="M59.5 40h.4M59.5 36.8h.4M59.5 33.5h.4M59.5 30.2h.4M59.5 27h.4M59.5 23.7h.4M60.6 40h.4M60.6 36.8h.4M60.6 33.5h.4M60.6 30.2h.4M60.6 27h.4M60.6 23.7h.4"/>
<path d="M61.7 40h.4M61.7 36.8h.4M61.7 33.5h.4M61.7 30.2h.4M61.7 27h.4M61.7 23.7h.4M62.9 40h.3M62.9 36.8h.3M62.9 33.5h.3M62.9 30.2h.3M62.9 27h.3M62.9 23.7h.3"/>
<path d="M64 40h.3M64 36.8h.3M64 33.5h.3M64 30.2h.3M64 27h.3M64 23.7h.3M65.1 40h.3M65.1 36.8h.3M65.1 33.5h.3M65.1 30.2h.3M65.1 27h.3M65.1 23.7h.3"/>
<path d="M66.2 40h.3M66.2 36.8h.3M66.2 33.5h.3M66.2 30.2h.3M66.2 27h.3M66.2 23.7h.3M67.3 40h.4M67.3 36.8h.4M67.3 33.5h.4M67.3 30.2h.4M67.3 27h.4M67.3 23.7h.4"/>
<path d="M68.4 40h.4M68.4 36.8h.4M68.4 33.5h.4M68.4 30.2h.4M68.4 27h.4M68.4 23.7h.4M69.5 40h.4M69.5 36.8h.4M69.5 33.5h.4M69.5 30.2h.4M69.5 27h.4M69.5 23.7h.4"/>
<path d="M70.6 40h.4M70.6 36.8h.4M70.6 33.5h.4M70.6 30.2h.4M70.6 27h.4M70.6 23.7h.4M71.7 40h.4M71.7 36.8h.4M71.7 33.5h.4M71.7 30.2h.4M71.7 27h.4M71.7 23.7h.4"/>
<path d="M72.8 40h.4M72.8 36.8h.4M72.8 33.5h.4M72.8 30.2h.4M72.8 27h.4M72.8 23.7h.4M73.9 40h.4M73.9 36.8h.4M73.9 33.5h.4M73.9 30.2h.4M73.9 27h.4M73.9 23.7h.4"/>
<path d="M75 40h.4M75 36.8h.4M75 33.5h.4M75 30.2h.4M75 27h.4M75 23.7h.4M76.1 40h.4M76.1 36.8h.4M76.1 33.5h.4M76.1 30.2h.4M76.1 27h.4M76.1 23.7h.4"/>
<path d="M77.3 40h.3M77.3 36.8h.3M77.3 33.5h.3M77.3 30.2h.3M77.3 27h.3M77.3 23.7h.3M78.4 40h.3M78.4 36.8h.3M78.4 33.5h.3M78.4 30.2h.3M78.4 27h.3M78.4 23.7h.3"/>
<path d="M79.5 40h.3M79.5 36.8h.3M79.5 33.5h.3M79.5 30.2h.3M79.5 27h.3M79.5 23.7h.3M80.6 40h.3M80.6 36.8h.3M80.6 33.5h.3M80.6 30.2h.3M80.6 27h.3M80.6 23.7h.3"/>
<path d="M81.7 40h.4M81.7 36.8h.4M81.7 33.5h.4M81.7 30.2h.4M81.7 27h.4M81.7 23.7h.4M27 46.4h.8M27 43.3h.8M27 49.7h.8M27.4 48.1h.4M27.4 44.9h.4M27.4 41.6h.4"/>
<path d="M28.5 46.4h.4M28.5 43.3h.4M29.6 46.4h.4M29.6 43.3h.4M30.7 46.4h.4M30.7 43.3h.4M31.8 46.4h.4M31.8 43.3h.4M33 46.4h.3M33 43.3h.3M34.1 46.4h.3M34.1 43.3h.3"/>
<path d="M34.2 49.4v.3M35.2 46.4h.3M35.2 43.3h.3M36.3 46.4h.3M36.3 43.3h.3M37.4 46.4h.4M37.4 43.3h.4M38.5 46.4h.4M38.5 43.3h.4M39.6 46.4h.4M39.6 43.3h.4M40.7 46.4h.4"/>
<path d="M40.7 43.3h.4M41.3 49.4v.7M41.8 46.4h.4M41.8 43.3h.4M42.9 46.4h.4M42.9 43.3h.4M44 46.4h.4M44 43.3h.4M45.1 46.4h.4M45.1 43.3h.4M46.2 46.4h.4M46.2 43.3h.4"/>
<path d="M47.4 46.4h.3M47.4 43.3h.3M48.1 49.4v.3M48.5 46.4h.3M48.5 43.3h.3M49.6 46.4h.3M49.6 43.3h.3M50.7 46.4h.3M50.7 43.3h.3M51.8 46.4h.4M51.8 43.3h.4M52.9 46.4h.4"/>
<path d="M52.9 43.3h.4M54 46.4h.4M54 43.3h.4M54.9 49.4v.7M55.1 46.4h.4M55.1 43.3h.4M56.2 46.4h.4M56.2 43.3h.4M57.3 46.4h.4M57.3 43.3h.4M58.4 46.4h.4M58.4 43.3h.4"/>
<path d="M59.5 46.4h.4M59.5 43.3h.4M60.6 46.4h.4M60.6 43.3h.4M61.7 46.4h.4M61.7 43.3h.4M61.7 49.4v.3M62.9 46.4h.3M62.9 43.3h.3M64 46.4h.3M64 43.3h.3M65.1 46.4h.3"/>
<path d="M65.1 43.3h.3M66.2 46.4h.3M66.2 43.3h.3M67.3 46.4h.4M67.3 43.3h.4M68.4 46.4h.4M68.4 43.3h.4M68.8 49.4v.7M69.5 46.4h.4M69.5 43.3h.4M70.6 46.4h.4M70.6 43.3h.4"/>
<path d="M71.7 46.4h.4M71.7 43.3h.4M72.8 46.4h.4M72.8 43.3h.4M73.9 46.4h.4M73.9 43.3h.4M75 46.4h.4M75 43.3h.4M75.6 49.4v.3M76.1 46.4h.4M76.1 43.3h.4M77.3 46.4h.3"/>
<path d="M77.3 43.3h.3M78.4 46.4h.3M78.4 43.3h.3M79.5 46.4h.3M79.5 43.3h.3M80.6 46.4h.3M80.6 43.3h.3M81.7 46.4h.4M81.7 43.3h.4M82.4 49.4v.7"/>
</g>
<path d="M27.4 49.7v-26h55v26" fill="none" stroke="#949698" stroke-width=".18"/>
<path d="M27.4 49.7h55" fill="none" stroke="#231f20" stroke-width=".18"/>
<g fill="none" stroke="#231f20" stroke-width=".37">
<path d="M54.6 39.1l-1.1 .6-2.9 1.1M57.4 38l-2.6 1.1M58.3 39.3l-1.3 .4M60.2 36.9l-2.6 1.1M60.6 38.4l-.8 .4M62.8 37.8l-.8 .2M63.9 37.5l-.8 .2M65.5 34.9l-3.8 1.5M65.9 36.5l-.6 .4M68.1 35.8l-.7 .2M69.4 35.3l-.7 .3M71.3 32.5l-4.3 1.8"/>
<path d="M71.6 34.5l-.7 .4M73.8 33.6l-.7 .4M74.8 33.2l-.8 .4M76.6 30.3l-3.9 1.6M77 32.5l-.8 .2M79 31.6l-.5 .3M80.3 28.8l-2.4 .9M81.2 30.8l-.7 .2M82.3 25.7l-8.3 3.5-2.7 1.3a80.7 80.7 0 0 1-9.6 4.2l-5 2.2-.6 .4-.7 .2-.6 .3-5.3 2.3-13.9 6-4.4 1.7-3.3 1.5M82.3 27.9l-.7 .3M27.9 49.3l-.6 .4M29.7 48.7h.4"/>
<path d="M30.1 48.7l-.9 .2-.8 .4h-.5M30.8 48.5l-.7 .2M32.7 48l-2.6 .7M33 47.6l-.7 .4M35.3 47.1l-.8 .2M35.6 46.9l-1.4 .5M36.4 46.7l-.8 .2M38 46l-2.4 .9M38.4 46l-.6 .1M40.6 45.2l-.7 .2M41.9 44.9l-.7 .1M43.6 43.6l-4.1 1.6"/>
<path d="M43.9 44.1l-.5 .2M46.2 43.4l-.8 .2M47.3 42.8l-.8 .4M49.1 41.3l-4.1 1.5M50.2 41.9l-.7 .4-.8 .2M52.8 41l-1.1 .5M55.6 40.2l-1.3 .4"/>
</g>
<path d="M30.4 25h16.8v7.9h-16.8z" fill="#fff" stroke="#231f20" stroke-width=".16"/>
<path d="M31.6 26.8h6.4M31.6 29.3h2.6M31.6 31.7h.7M33.8 31.7h.7M35.6 29.3h2.4M36 31.7h.7" fill="none" stroke="#231f20" stroke-width=".37"/>
<path d="M19.2 114.8h66.4v41h-66.4zM93.6 114.7h66.4v41.1h-66.4zM19.1 163.3h66.4v41h-66.4zM93.7 163.4h66.3v41h-66.3z" fill="none" stroke="#231f20" stroke-width=".17"/>
<g fill="none" stroke="#231f20" stroke-width=".16">
<path d="M101 39.8h.8M101 36.7h.8M101 33.4h.8M101 30.3h.8M101 27h.8M101 23.9h.8M101.4 23.9v25.8M101.4 38.2h.4M101.4 34.9h.4M101.4 31.8h.4M101.4 28.7h.4M101.4 25.4h.4"/>
<path d="M102.6 39.8h.4M102.6 36.7h.4M102.6 33.4h.4M102.6 30.3h.4M102.6 27h.4M102.6 23.9h.4M103.7 39.8h.4M103.7 36.7h.4M103.7 33.4h.4M103.7 30.3h.4M103.7 27h.4M103.7 23.9h.4"/>
<path d="M104.9 39.8h.4M104.9 36.7h.4M104.9 33.4h.4M104.9 30.3h.4M104.9 27h.4M104.9 23.9h.4M106.1 39.8h.3M106.1 36.7h.3M106.1 33.4h.3M106.1 30.3h.3M106.1 27h.3M106.1 23.9h.3"/>
<path d="M107.2 39.8h.4M107.2 36.7h.4M107.2 33.4h.4M107.2 30.3h.4M107.2 27h.4M107.2 23.9h.4M108.4 39.8h.4M108.4 36.7h.4M108.4 33.4h.4M108.4 30.3h.4M108.4 27h.4M108.4 23.9h.4"/>
<path d="M109.5 39.8h.4M109.5 36.7h.4M109.5 33.4h.4M109.5 30.3h.4M109.5 27h.4M109.5 23.9h.4M110.7 39.8h.4M110.7 36.7h.4M110.7 33.4h.4M110.7 30.3h.4M110.7 27h.4M110.7 23.9h.4"/>
<path d="M111.9 39.8h.3M111.9 36.7h.3M111.9 33.4h.3M111.9 30.3h.3M111.9 27h.3M111.9 23.9h.3M113 39.8h.4M113 36.7h.4M113 33.4h.4M113 30.3h.4M113 27h.4M113 23.9h.4"/>
<path d="M114.2 39.8h.4M114.2 36.7h.4M114.2 33.4h.4M114.2 30.3h.4M114.2 27h.4M114.2 23.9h.4M115.3 39.8h.4M115.3 36.7h.4M115.3 33.4h.4M115.3 30.3h.4M115.3 27h.4M115.3 23.9h.4"/>
<path d="M116.5 39.8h.4M116.5 36.7h.4M116.5 33.4h.4M116.5 30.3h.4M116.5 27h.4M116.5 23.9h.4M117.6 39.8h.4M117.6 36.7h.4M117.6 33.4h.4M117.6 30.3h.4M117.6 27h.4M117.6 23.9h.4"/>
<path d="M118.8 39.8h.4M118.8 36.7h.4M118.8 33.4h.4M118.8 30.3h.4M118.8 27h.4M118.8 23.9h.4M120 39.8h.3M120 36.7h.3M120 33.4h.3M120 30.3h.3M120 27h.3M120 23.9h.3"/>
<path d="M121.1 39.8h.4M121.1 36.7h.4M121.1 33.4h.4M121.1 30.3h.4M121.1 27h.4M121.1 23.9h.4M122.3 39.8h.4M122.3 36.7h.4M122.3 33.4h.4M122.3 30.3h.4M122.3 27h.4M122.3 23.9h.4"/>
<path d="M123.4 39.8h.4M123.4 36.7h.4M123.4 33.4h.4M123.4 30.3h.4M123.4 27h.4M123.4 23.9h.4M124.6 39.8h.4M124.6 36.7h.4M124.6 33.4h.4M124.6 30.3h.4M124.6 27h.4M124.6 23.9h.4"/>
<path d="M125.8 39.8h.3M125.8 36.7h.3M125.8 33.4h.3M125.8 30.3h.3M125.8 27h.3M125.8 23.9h.3M126.9 39.8h.4M126.9 36.7h.4M126.9 33.4h.4M126.9 30.3h.4M126.9 27h.4M126.9 23.9h.4"/>
<path d="M128.1 39.8h.4M128.1 36.7h.4M128.1 33.4h.4M128.1 30.3h.4M128.1 27h.4M128.1 23.9h.4M129.2 39.8h.4M129.2 36.7h.4M129.2 33.4h.4M129.2 30.3h.4M129.2 27h.4M129.2 23.9h.4"/>
<path d="M130.4 39.8h.4M130.4 36.7h.4M130.4 33.4h.4M130.4 30.3h.4M130.4 27h.4M130.4 23.9h.4M131.6 39.8h.3M131.6 36.7h.3M131.6 33.4h.3M131.6 30.3h.3M131.6 27h.3M131.6 23.9h.3"/>
<path d="M132.7 39.8h.4M132.7 36.7h.4M132.7 33.4h.4M132.7 30.3h.4M132.7 27h.4M132.7 23.9h.4M133.9 39.8h.4M133.9 36.7h.4M133.9 33.4h.4M133.9 30.3h.4M133.9 27h.4M133.9 23.9h.4"/>
<path d="M135 39.8h.4M135 36.7h.4M135 33.4h.4M135 30.3h.4M135 27h.4M135 23.9h.4M136.2 39.8h.4M136.2 36.7h.4M136.2 33.4h.4M136.2 30.3h.4M136.2 27h.4M136.2 23.9h.4"/>
<path d="M137.3 39.8h.4M137.3 36.7h.4M137.3 33.4h.4M137.3 30.3h.4M137.3 27h.4M137.3 23.9h.4M138.5 39.8h.4M138.5 36.7h.4M138.5 33.4h.4M138.5 30.3h.4M138.5 27h.4M138.5 23.9h.4"/>
<path d="M139.7 39.8h.3M139.7 36.7h.3M139.7 33.4h.3M139.7 30.3h.3M139.7 27h.3M139.7 23.9h.3M140.8 39.8h.4M140.8 36.7h.4M140.8 33.4h.4M140.8 30.3h.4M140.8 27h.4M140.8 23.9h.4"/>
<path d="M142 39.8h.4M142 36.7h.4M142 33.4h.4M142 30.3h.4M142 27h.4M142 23.9h.4M143.1 39.8h.4M143.1 36.7h.4M143.1 33.4h.4M143.1 30.3h.4M143.1 27h.4M143.1 23.9h.4"/>
<path d="M144.3 39.8h.4M144.3 36.7h.4M144.3 33.4h.4M144.3 30.3h.4M144.3 27h.4M144.3 23.9h.4M145.5 39.8h.3M145.5 36.7h.3M145.5 33.4h.3M145.5 30.3h.3M145.5 27h.3M145.5 23.9h.3"/>
<path d="M146.6 39.8h.4M146.6 36.7h.4M146.6 33.4h.4M146.6 30.3h.4M146.6 27h.4M146.6 23.9h.4M147.8 39.8h.4M147.8 36.7h.4M147.8 33.4h.4M147.8 30.3h.4M147.8 27h.4M147.8 23.9h.4"/>
<path d="M148.9 39.8h.4M148.9 36.7h.4M148.9 33.4h.4M148.9 30.3h.4M148.9 27h.4M148.9 23.9h.4M150.1 39.8h.4M150.1 36.7h.4M150.1 33.4h.4M150.1 30.3h.4M150.1 27h.4M150.1 23.9h.4"/>
<path d="M151.2 39.8h.4M151.2 36.7h.4M151.2 33.4h.4M151.2 30.3h.4M151.2 27h.4M151.2 23.9h.4M152.4 39.8h.4M152.4 36.7h.4M152.4 33.4h.4M152.4 30.3h.4M152.4 27h.4M152.4 23.9h.4"/>
<path d="M153.6 39.8h.4M153.6 36.7h.4M153.6 33.4h.4M153.6 30.3h.4M153.6 27h.4M153.6 23.9h.4M154.7 39.8h.4M154.7 36.7h.4M154.7 33.4h.4M154.7 30.3h.4M154.7 27h.4M154.7 23.9h.4"/>
<path d="M155.9 39.8h.4M155.9 36.7h.4M155.9 33.4h.4M155.9 30.3h.4M155.9 27h.4M155.9 23.9h.4M157 39.8h.4M157 36.7h.4M157 33.4h.4M157 30.3h.4M157 27h.4M157 23.9h.4"/>
<path d="M101 46.2h.8M101 42.9h.8M101 49.3h57.2M101.4 47.7h.4M101.4 44.4h.4M101.4 41.3h.4M102.6 46.2h.4M102.6 42.9h.4M103.7 46.2h.4M103.7 42.9h.4M104.9 46.2h.4M104.9 42.9h.4"/>
<path d="M106.1 46.2h.3M106.1 42.9h.3M106.3 48.9v.4M107.2 46.2h.4M107.2 42.9h.4M108.4 46.2h.4M108.4 42.9h.4M109.5 46.2h.4M109.5 42.9h.4M110.7 46.2h.4M110.7 42.9h.4M110.9 48.9v.8"/>
<path d="M111.9 46.2h.3M111.9 42.9h.3M113 46.2h.4M113 42.9h.4M114.2 46.2h.4M114.2 42.9h.4M115.3 46.2h.4M115.3 42.9h.4M115.7 48.9v.4M116.5 46.2h.4M116.5 42.9h.4M117.6 46.2h.4"/>
<path d="M117.6 42.9h.4M118.8 46.2h.4M118.8 42.9h.4M120 46.2h.3M120 42.9h.3M120.3 48.9v.8M121.1 46.2h.4M121.1 42.9h.4M122.3 46.2h.4M122.3 42.9h.4M123.4 46.2h.4M123.4 42.9h.4"/>
<path d="M124.6 46.2h.4M124.6 42.9h.4M125.2 48.9v.4M125.8 46.2h.3M125.8 42.9h.3M126.9 46.2h.4M126.9 42.9h.4M128.1 46.2h.4M128.1 42.9h.4M129.2 46.2h.4M129.2 42.9h.4M129.8 48.9v.8"/>
<path d="M130.4 46.2h.4M130.4 42.9h.4M131.6 46.2h.3M131.6 42.9h.3M132.7 46.2h.4M132.7 42.9h.4M133.9 46.2h.4M133.9 42.9h.4M134.6 48.9v.4M135 46.2h.4M135 42.9h.4M136.2 46.2h.4"/>
<path d="M136.2 42.9h.4M137.3 46.2h.4M137.3 42.9h.4M138.5 46.2h.4M138.5 42.9h.4M139.3 48.9v.8M139.7 46.2h.3M139.7 42.9h.3M140.8 46.2h.4M140.8 42.9h.4M142 46.2h.4M142 42.9h.4"/>
<path d="M143.1 46.2h.4M143.1 42.9h.4M144.1 48.9v.4M144.3 46.2h.4M144.3 42.9h.4M145.5 46.2h.3M145.5 42.9h.3M146.6 46.2h.4M146.6 42.9h.4M147.8 46.2h.4M147.8 42.9h.4M148.7 48.9v.8"/>
<path d="M148.9 46.2h.4M148.9 42.9h.4M150.1 46.2h.4M150.1 42.9h.4M151.2 46.2h.4M151.2 42.9h.4M152.4 46.2h.4M152.4 42.9h.4M153.6 46.2h.4M153.6 42.9h.4M153.6 48.9v.4M154.7 46.2h.4"/>
<path d="M154.7 42.9h.4M155.9 46.2h.4M155.9 42.9h.4M157 46.2h.4M157 42.9h.4M158.2 48.9v.8"/>
</g>
<path d="M101.4 23.9h56.8v25.4h-56.8z" fill="none" stroke="#949698" stroke-width=".19"/>
<g fill="none" stroke="#231f20" stroke-width=".39">
<path d="M110.4 39.7l-2.7 .4M110.8 39.7h2.7M116.6 39.5l-2.7 .2M119.9 39.3l-2.7 .2M123 39.1h-1.2l-1.5 .2M129.3 38.7l-1.1 .2h-3.9l-.4 .2h-.6M132.4 38.5l-2.7 .2M132.8 38.5h2.7M138.8 38.3l-2.7 .2M141.9 38.1l-2.7 .2M145 37.9l-2.7 .2M145.6 37.9h2.7"/>
<path d="M151.3 37.7h-1.1l-1.6 .2M151.7 37.7h2.7M157.7 37.5l-2.7 .2M158.1 25.7l-6.4 .4-3.1 .4h-3l-3.3 .2-3.1 .4-9.5 .6-2.5 .3h-1.2l-.1 .2h-3.1l-1 .2a182.3 182.3 0 0 0-14.1 1.6l-6.4 .4M101.3 44.7h.8M103.6 44.7h1.6M104 40.1l-2.7 .2M104.4 40.1h2.7M106.7 44.7h.8M108.5 44.5l-.8 .2M110 44.5h1.6M114.7 44.3l-.8 .2h-.8"/>
<path d="M116.2 44.3h.8M117.2 44.3h.7M121 44.1l-.7 .2h-.8M122.6 44.1h1.5M125.1 44.1h2.3M128.9 43.9h1.6M133.6 43.8l-.8 .1h-.8M135.1 43.8h.8M136.1 43.8h.8M138.4 43.8h1.6M143 43.6l-.7 .2h-.8M144.6 43.6h.8"/>
<path d="M145.6 43.6h.7M149.4 43.4l-.8 .2h-.7M151 43.4h1.5M154 43.4h.8M155 43.4h.8M157.3 43.4h.8"/>
</g>
<path d="M135.2 27.7h16.2v8.3h-16.2z" fill="#fff" stroke="#231f20" stroke-width=".16"/>
<path d="M136.1 29h6.7M136.1 31.7h2.7M136.1 34.6h.8M138.4 34.6h.8M140.3 31.7h2.5M140.7 34.6h.8" fill="none" stroke="#231f20" stroke-width=".39"/>
<g fill="none" stroke="#231f20" stroke-width=".16">
<path d="M26.8 79.1h.8M26.8 74.3h.8M27.2 74.3v24.2M27.2 76.7h.4M28.3 79.1h.4M28.3 74.3h.4M29.4 79.1h.4M29.4 74.3h.4M30.5 79.1h.4M30.5 74.3h.4M31.6 79.1h.4M31.6 74.3h.4"/>
<path d="M32.8 79.1h.3M32.8 74.3h.3M33.9 79.1h.4M33.9 74.3h.4M35 79.1h.4M35 74.3h.4M36.1 79.1h.4M36.1 74.3h.4M37.2 79.1h.4M37.2 74.3h.4M38.3 79.1h.4M38.3 74.3h.4"/>
<path d="M39.5 79.1h.3M39.5 74.3h.3M40.6 79.1h.4M40.6 74.3h.4M41.7 79.1h.4M41.7 74.3h.4M42.8 79.1h.4M42.8 74.3h.4M43.9 79.1h.4M43.9 74.3h.4M45.1 79.1h.3M45.1 74.3h.3"/>
<path d="M46.2 79.1h.3M46.2 74.3h.3M47.3 79.1h.4M47.3 74.3h.4M48.4 79.1h.4M48.4 74.3h.4M49.5 79.1h.4M49.5 74.3h.4M50.6 79.1h.4M50.6 74.3h.4M51.8 79.1h.3M51.8 74.3h.3"/>
<path d="M52.9 79.1h.3M52.9 74.3h.3M54 79.1h.4M54 74.3h.4M55.1 79.1h.4M55.1 74.3h.4M56.2 79.1h.4M56.2 74.3h.4M57.3 79.1h.4M57.3 74.3h.4M58.5 79.1h.3M58.5 74.3h.3"/>
<path d="M59.6 79.1h.3M59.6 74.3h.3M60.7 79.1h.4M60.7 74.3h.4M61.8 79.1h.4M61.8 74.3h.4M62.9 79.1h.4M62.9 74.3h.4M64 79.1h.4M64 74.3h.4M65.2 79.1h.3M65.2 74.3h.3"/>
<path d="M66.3 79.1h.3M66.3 74.3h.3M67.4 79.1h.4M67.4 74.3h.4M68.5 79.1h.4M68.5 74.3h.4M69.6 79.1h.4M69.6 74.3h.4M70.7 79.1h.4M70.7 74.3h.4M71.9 79.1h.3M71.9 74.3h.3"/>
<path d="M73 79.1h.3M73 74.3h.3M74.1 79.1h.4M74.1 74.3h.4M75.2 79.1h.4M75.2 74.3h.4M76.3 79.1h.4M76.3 74.3h.4M77.4 79.1h.4M77.4 74.3h.4M78.6 79.1h.3M78.6 74.3h.3"/>
<path d="M79.7 79.1h.3M79.7 74.3h.3M80.8 79.1h.4M80.8 74.3h.4M81.9 79.1h.4M81.9 74.3h.4M26.8 93.2h.8M26.8 88.6h.8M26.8 83.8h.8M26.8 98.1h55.5M27.2 95.7h.4M27.2 91h.4"/>
<path d="M27.2 86.2h.4M27.2 81.3h.4M28.3 93.2h.4M28.3 88.6h.4M28.3 83.8h.4M29.4 93.2h.4M29.4 88.6h.4M29.4 83.8h.4M30.5 93.2h.4M30.5 88.6h.4M30.5 83.8h.4M31.6 93.2h.4"/>
<path d="M31.6 88.6h.4M31.6 83.8h.4M31.8 97.7v.4M32.8 93.2h.3M32.8 88.6h.3M32.8 83.8h.3M33.9 93.2h.4M33.9 88.6h.4M33.9 83.8h.4M35 93.2h.4M35 88.6h.4M35 83.8h.4"/>
<path d="M36.1 93.2h.4M36.1 88.6h.4M36.1 83.8h.4M36.3 97.7v.8M37.2 93.2h.4M37.2 88.6h.4M37.2 83.8h.4M38.3 93.2h.4M38.3 88.6h.4M38.3 83.8h.4M39.5 93.2h.3M39.5 88.6h.3"/>
<path d="M39.5 83.8h.3M40.6 93.2h.4M40.6 88.6h.4M40.6 83.8h.4M41 97.7v.4M41.7 93.2h.4M41.7 88.6h.4M41.7 83.8h.4M42.8 93.2h.4M42.8 88.6h.4M42.8 83.8h.4M43.9 93.2h.4"/>
<path d="M43.9 88.6h.4M43.9 83.8h.4M45.1 93.2h.3M45.1 88.6h.3M45.1 83.8h.3M45.6 97.7v.8M46.2 93.2h.3M46.2 88.6h.3M46.2 83.8h.3M47.3 93.2h.4M47.3 88.6h.4M47.3 83.8h.4"/>
<path d="M48.4 93.2h.4M48.4 88.6h.4M48.4 83.8h.4M49.5 93.2h.4M49.5 88.6h.4M49.5 83.8h.4M50.1 97.7v.4M50.6 93.2h.4M50.6 88.6h.4M50.6 83.8h.4M51.8 93.2h.3M51.8 88.6h.3"/>
<path d="M51.8 83.8h.3M52.9 93.2h.3M52.9 88.6h.3M52.9 83.8h.3M54 93.2h.4M54 88.6h.4M54 83.8h.4M54.7 97.7v.8M55.1 93.2h.4M55.1 88.6h.4M55.1 83.8h.4M56.2 93.2h.4"/>
<path d="M56.2 88.6h.4M56.2 83.8h.4M57.3 93.2h.4M57.3 88.6h.4M57.3 83.8h.4M58.5 93.2h.3M58.5 88.6h.3M58.5 83.8h.3M59.4 97.7v.4M59.6 93.2h.3M59.6 88.6h.3M59.6 83.8h.3"/>
<path d="M60.7 93.2h.4M60.7 88.6h.4M60.7 83.8h.4M61.8 93.2h.4M61.8 88.6h.4M61.8 83.8h.4M62.9 93.2h.4M62.9 88.6h.4M62.9 83.8h.4M63.9 97.7v.8M64 93.2h.4M64 88.6h.4"/>
<path d="M64 83.8h.4M65.2 93.2h.3M65.2 88.6h.3M65.2 83.8h.3M66.3 93.2h.3M66.3 88.6h.3M66.3 83.8h.3M67.4 93.2h.4M67.4 88.6h.4M67.4 83.8h.4M68.5 93.2h.4M68.5 88.6h.4"/>
<path d="M68.5 83.8h.4M68.5 97.7v.4M69.6 93.2h.4M69.6 88.6h.4M69.6 83.8h.4M70.7 93.2h.4M70.7 88.6h.4M70.7 83.8h.4M71.9 93.2h.3M71.9 88.6h.3M71.9 83.8h.3M73 93.2h.3"/>
<path d="M73 88.6h.3M73 83.8h.3M73.2 97.7v.8M74.1 93.2h.4M74.1 88.6h.4M74.1 83.8h.4M75.2 93.2h.4M75.2 88.6h.4M75.2 83.8h.4M76.3 93.2h.4M76.3 88.6h.4M76.3 83.8h.4"/>
<path d="M77.4 93.2h.4M77.4 88.6h.4M77.4 83.8h.4M77.6 97.7v.4M78.6 93.2h.3M78.6 88.6h.3M78.6 83.8h.3M79.7 93.2h.3M79.7 88.6h.3M79.7 83.8h.3M80.8 93.2h.4M80.8 88.6h.4"/>
<path d="M80.8 83.8h.4M81.9 93.2h.4M81.9 88.6h.4M81.9 83.8h.4M82.3 97.7v.8"/>
</g>
<path d="M27.2 74.3h55.1v23.8" fill="none" stroke="#231f20" stroke-width=".19"/>
<path d="M27.2 74.3v23.8h55.1" fill="none" stroke="#949698" stroke-width=".19"/>
<g fill="none" stroke="#231f20" stroke-width=".37">
<path d="M82.2 79.8l-6.2 .3-2.9 .4-6.2 .4-3.1 .3-3 .2M27.1 96.5h2.6M32.7 96.3l-2.6 .2M33.2 96.3h2.6M36.2 96.3h2.6M39.4 96.3h2.6M42.4 96.3h2.6M45.5 82.9l-9.3 .8-3 .3-6.1 .4M45.5 96.3h2.6M54.3 96.1h-1.2l-.9 .2h-3.7M54.6 96.1h2.6M57.6 96.1h2.6"/>
<path d="M60.8 96.1h2.6M63.8 96.1h2.6M69.5 95.9l-2.6 .2M69.9 95.9h2.6M73.1 95.9h2.6M76 95.9h2.7M79.2 95.9h2.6"/>
</g>
<path d="M29 75.2h15.3v5.6h-15.3z" fill="#fff" stroke="#231f20" stroke-width=".16"/>
<path d="M29.9 76.4h6.5M29.9 79h2.6M34 79h2.4M60.8 81.4l-3.2 .4-3 .2-2.4 .4h-3l-.1 .1h-1.2l-2.4 .4" fill="none" stroke="#231f20" stroke-width=".37"/>
<path d="M100.1 96.9l1.2-3.9 .6-1.1 .5-.2 .2 .2 1 1.8 .5 .2 .3-.1a1.99 1.99 0 0 1 2.2-.8 1.42 1.42 0 0 0 1.8-.5 4.9 4.9 0 0 1 3-1.2l.5-.3a3.4 3.4 0 0 1 1.7-1.6l.5 .1 .9 .4a8.5 8.5 0 0 0 3 1l.9-.1a12.8 12.8 0 0 0 1.7-4.6l.5-.8a1.19 1.19 0 0 1 1.1 1 8.1 8.1 0 0 1 .6 3.2l.2 .3 .7-.5a1.52 1.52 0 0 1 1.4-.8l1.1 .9 .4 .2 .2-.2a7 7 0 0 0 1.1-3.6l.7-1h.3l.5 .4 .8 1.3 .4 .3 .4 .1 1-1h.5a2.61 2.61 0 0 1 .9 1.8l.8 1.2h.2l.6-.7 .1-.7 .3-.5a2.93 2.93 0 0 1 1.1-2.4l.3 .1a1.86 1.86 0 0 0 1.4 1 2.43 2.43 0 0 0 1.4-1.6l.5-.2 .3 .1 1 1.3 .7 .3 .5-.7 .7-1.8 .7-.7a1.19 1.19 0 0 1 .8 1.1l.9 1a.94 .94 0 0 0 .7-.6l.5-1.4a1.04 1.04 0 0 1 1.4-.9 1.77 1.77 0 0 0 1.7 .8l1.9-1 1.6-.6" fill="none" stroke="#231f20" stroke-width=".36" stroke-dasharray="2.2 .4 .4 .4" stroke-linecap="butt"/>
<g fill="none" stroke="#231f20" stroke-width=".16">
<path d="M99.8 78h.7M99.8 75.4h.7M99.8 72.9h.7M100.1 72.9v25.4M101.2 78h.4M101.2 75.4h.4M101.2 72.9h.4M102.3 78h.4M102.3 75.4h.4M102.3 72.9h.4M103.4 78h.3M103.4 75.4h.3"/>
<path d="M103.4 72.9h.3M104.5 78h.3M104.5 75.4h.3M104.5 72.9h.3M105.6 78h.3M105.6 75.4h.3M105.6 72.9h.3M106.6 78h.4M106.6 75.4h.4M106.6 72.9h.4M107.7 78h.4M107.7 75.4h.4"/>
<path d="M107.7 72.9h.4M108.8 78h.4M108.8 75.4h.4M108.8 72.9h.4M109.9 78h.4M109.9 75.4h.4M109.9 72.9h.4M111 78h.4M111 75.4h.4M111 72.9h.4M112.1 78h.3M112.1 75.4h.3"/>
<path d="M112.1 72.9h.3M113.2 78h.3M113.2 75.4h.3M113.2 72.9h.3M114.3 78h.3M114.3 75.4h.3M114.3 72.9h.3M115.3 78h.4M115.3 75.4h.4M115.3 72.9h.4M116.4 78h.4M116.4 75.4h.4"/>
<path d="M116.4 72.9h.4M117.5 78h.4M117.5 75.4h.4M117.5 72.9h.4M118.6 78h.4M118.6 75.4h.4M118.6 72.9h.4M119.7 78h.4M119.7 75.4h.4M119.7 72.9h.4M120.8 78h.3M120.8 75.4h.3"/>
<path d="M120.8 72.9h.3M121.9 78h.3M121.9 75.4h.3M121.9 72.9h.3M123 78h.3M123 75.4h.3M123 72.9h.3M124 78h.4M124 75.4h.4M124 72.9h.4M125.1 78h.4M125.1 75.4h.4"/>
<path d="M125.1 72.9h.4M126.2 78h.4M126.2 75.4h.4M126.2 72.9h.4M127.3 78h.4M127.3 75.4h.4M127.3 72.9h.4M128.4 78h.4M128.4 75.4h.4M128.4 72.9h.4M129.5 78h.3M129.5 75.4h.3"/>
<path d="M129.5 72.9h.3M130.6 78h.3M130.6 75.4h.3M130.6 72.9h.3M131.7 78h.3M131.7 75.4h.3M131.7 72.9h.3M132.7 78h.4M132.7 75.4h.4M132.7 72.9h.4M133.8 78h.4M133.8 75.4h.4"/>
<path d="M133.8 72.9h.4M134.9 78h.4M134.9 75.4h.4M134.9 72.9h.4M136 78h.4M136 75.4h.4M136 72.9h.4M137.1 78h.4M137.1 75.4h.4M137.1 72.9h.4M138.2 78h.3M138.2 75.4h.3"/>
<path d="M138.2 72.9h.3M139.3 78h.3M139.3 75.4h.3M139.3 72.9h.3M140.4 78h.3M140.4 75.4h.3M140.4 72.9h.3M141.4 78h.4M141.4 75.4h.4M141.4 72.9h.4M142.5 78h.4M142.5 75.4h.4"/>
<path d="M142.5 72.9h.4M143.6 78h.4M143.6 75.4h.4M143.6 72.9h.4M144.7 78h.4M144.7 75.4h.4M144.7 72.9h.4M145.8 78h.4M145.8 75.4h.4M145.8 72.9h.4M146.9 78h.3M146.9 75.4h.3"/>
<path d="M146.9 72.9h.3M148 78h.3M148 75.4h.3M148 72.9h.3M149.1 78h.3M149.1 75.4h.3M149.1 72.9h.3M150.1 78h.4M150.1 75.4h.4M150.1 72.9h.4M151.2 78h.4M151.2 75.4h.4"/>
<path d="M151.2 72.9h.4M152.3 78h.4M152.3 75.4h.4M152.3 72.9h.4M153.4 78h.2M153.4 75.4h.2M153.4 72.9h.6M153.6 72.9v25.4M99.8 95.7h.7M99.8 93.2h.7M99.8 90.7h.7M99.8 88.1h.7"/>
<path d="M99.8 85.6h.7M99.8 83.1h.7M99.8 80.5h.7M99.8 98.3h54.2M101.2 95.7h.4M101.2 93.2h.4M101.2 90.7h.4M101.2 88.1h.4M101.2 85.6h.4M101.2 83.1h.4M101.2 80.5h.4M102.3 95.7h.4"/>
<path d="M102.3 93.2h.4M102.3 90.7h.4M102.3 88.1h.4M102.3 85.6h.4M102.3 83.1h.4M102.3 80.5h.4M103.4 95.7h.3M103.4 93.2h.3M103.4 90.7h.3M103.4 88.1h.3M103.4 85.6h.3M103.4 83.1h.3"/>
<path d="M103.4 80.5h.3M103.9 97.9v.4M104.5 95.7h.3M104.5 93.2h.3M104.5 90.7h.3M104.5 88.1h.3M104.5 85.6h.3M104.5 83.1h.3M104.5 80.5h.3M105.6 95.7h.3M105.6 93.2h.3M105.6 90.7h.3"/>
<path d="M105.6 88.1h.3M105.6 85.6h.3M105.6 83.1h.3M105.6 80.5h.3M106.6 95.7h.4M106.6 93.2h.4M106.6 90.7h.4M106.6 88.1h.4M106.6 85.6h.4M106.6 83.1h.4M106.6 80.5h.4M107.7 95.7h.4"/>
<path d="M107.7 93.2h.4M107.7 90.7h.4M107.7 88.1h.4M107.7 85.6h.4M107.7 83.1h.4M107.7 80.5h.4M107.7 97.9v.4M108.8 95.7h.4M108.8 93.2h.4M108.8 90.7h.4M108.8 88.1h.4M108.8 85.6h.4"/>
<path d="M108.8 83.1h.4M108.8 80.5h.4M109.9 95.7h.4M109.9 93.2h.4M109.9 90.7h.4M109.9 88.1h.4M109.9 85.6h.4M109.9 83.1h.4M109.9 80.5h.4M111 95.7h.4M111 93.2h.4M111 90.7h.4"/>
<path d="M111 88.1h.4M111 85.6h.4M111 83.1h.4M111 80.5h.4M111.5 97.9v.4M112.1 95.7h.3M112.1 93.2h.3M112.1 90.7h.3M112.1 88.1h.3M112.1 85.6h.3M112.1 83.1h.3M112.1 80.5h.3"/>
<path d="M113.2 95.7h.3M113.2 93.2h.3M113.2 90.7h.3M113.2 88.1h.3M113.2 85.6h.3M113.2 83.1h.3M113.2 80.5h.3M114.3 95.7h.3M114.3 93.2h.3M114.3 90.7h.3M114.3 88.1h.3M114.3 85.6h.3"/>
<path d="M114.3 83.1h.3M114.3 80.5h.3M115.3 95.7h.4M115.3 93.2h.4M115.3 90.7h.4M115.3 88.1h.4M115.3 85.6h.4M115.3 83.1h.4M115.3 80.5h.4M115.3 97.9v.4M116.4 95.7h.4M116.4 93.2h.4"/>
<path d="M116.4 90.7h.4M116.4 88.1h.4M116.4 85.6h.4M116.4 83.1h.4M116.4 80.5h.4M117.5 95.7h.4M117.5 93.2h.4M117.5 90.7h.4M117.5 88.1h.4M117.5 85.6h.4M117.5 83.1h.4M117.5 80.5h.4"/>
<path d="M118.6 95.7h.4M118.6 93.2h.4M118.6 90.7h.4M118.6 88.1h.4M118.6 85.6h.4M118.6 83.1h.4M118.6 80.5h.4M119.1 97.9v.4M119.7 95.7h.4M119.7 93.2h.4M119.7 90.7h.4M119.7 88.1h.4"/>
<path d="M119.7 85.6h.4M119.7 83.1h.4M119.7 80.5h.4M120.8 95.7h.3M120.8 93.2h.3M120.8 90.7h.3M120.8 88.1h.3M120.8 85.6h.3M120.8 83.1h.3M120.8 80.5h.3M121.9 95.7h.3M121.9 93.2h.3"/>
<path d="M121.9 90.7h.3M121.9 88.1h.3M121.9 85.6h.3M121.9 83.1h.3M121.9 80.5h.3M123 95.7h.3M123 93.2h.3M123 90.7h.3M123 88.1h.3M123 85.6h.3M123 83.1h.3M123 80.5h.3"/>
<path d="M123 97.9v.4M124 95.7h.4M124 93.2h.4M124 90.7h.4M124 88.1h.4M124 85.6h.4M124 83.1h.4M124 80.5h.4M125.1 95.7h.4M125.1 93.2h.4M125.1 90.7h.4M125.1 88.1h.4"/>
<path d="M125.1 85.6h.4M125.1 83.1h.4M125.1 80.5h.4M126.2 95.7h.4M126.2 93.2h.4M126.2 90.7h.4M126.2 88.1h.4M126.2 85.6h.4M126.2 83.1h.4M126.2 80.5h.4M126.9 97.9v.4M127.3 95.7h.4"/>
<path d="M127.3 93.2h.4M127.3 90.7h.4M127.3 88.1h.4M127.3 85.6h.4M127.3 83.1h.4M127.3 80.5h.4M128.4 95.7h.4M128.4 93.2h.4M128.4 90.7h.4M128.4 88.1h.4M128.4 85.6h.4M128.4 83.1h.4"/>
<path d="M128.4 80.5h.4M129.5 95.7h.3M129.5 93.2h.3M129.5 90.7h.3M129.5 88.1h.3M129.5 85.6h.3M129.5 83.1h.3M129.5 80.5h.3M130.6 95.7h.3M130.6 93.2h.3M130.6 90.7h.3M130.6 88.1h.3"/>
<path d="M130.6 85.6h.3M130.6 83.1h.3M130.6 80.5h.3M130.8 97.9v.4M131.7 95.7h.3M131.7 93.2h.3M131.7 90.7h.3M131.7 88.1h.3M131.7 85.6h.3M131.7 83.1h.3M131.7 80.5h.3M132.7 95.7h.4"/>
<path d="M132.7 93.2h.4M132.7 90.7h.4M132.7 88.1h.4M132.7 85.6h.4M132.7 83.1h.4M132.7 80.5h.4M133.8 95.7h.4M133.8 93.2h.4M133.8 90.7h.4M133.8 88.1h.4M133.8 85.6h.4M133.8 83.1h.4"/>
<path d="M133.8 80.5h.4M134.6 97.9v.4M134.9 95.7h.4M134.9 93.2h.4M134.9 90.7h.4M134.9 88.1h.4M134.9 85.6h.4M134.9 83.1h.4M134.9 80.5h.4M136 95.7h.4M136 93.2h.4M136 90.7h.4"/>
<path d="M136 88.1h.4M136 85.6h.4M136 83.1h.4M136 80.5h.4M137.1 95.7h.4M137.1 93.2h.4M137.1 90.7h.4M137.1 88.1h.4M137.1 85.6h.4M137.1 83.1h.4M137.1 80.5h.4M138.2 95.7h.3"/>
<path d="M138.2 93.2h.3M138.2 90.7h.3M138.2 88.1h.3M138.2 85.6h.3M138.2 83.1h.3M138.2 80.5h.3M138.4 97.9v.4M139.3 95.7h.3M139.3 93.2h.3M139.3 90.7h.3M139.3 88.1h.3M139.3 85.6h.3"/>
<path d="M139.3 83.1h.3M139.3 80.5h.3M140.4 95.7h.3M140.4 93.2h.3M140.4 90.7h.3M140.4 88.1h.3M140.4 85.6h.3M140.4 83.1h.3M140.4 80.5h.3M141.4 95.7h.4M141.4 93.2h.4M141.4 90.7h.4"/>
<path d="M141.4 88.1h.4M141.4 85.6h.4M141.4 83.1h.4M141.4 80.5h.4M142.2 97.9v.4M142.5 95.7h.4M142.5 93.2h.4M142.5 90.7h.4M142.5 88.1h.4M142.5 85.6h.4M142.5 83.1h.4M142.5 80.5h.4"/>
<path d="M143.6 95.7h.4M143.6 93.2h.4M143.6 90.7h.4M143.6 88.1h.4M143.6 85.6h.4M143.6 83.1h.4M143.6 80.5h.4M144.7 95.7h.4M144.7 93.2h.4M144.7 90.7h.4M144.7 88.1h.4M144.7 85.6h.4"/>
<path d="M144.7 83.1h.4M144.7 80.5h.4M145.8 95.7h.4M145.8 93.2h.4M145.8 90.7h.4M145.8 88.1h.4M145.8 85.6h.4M145.8 83.1h.4M145.8 80.5h.4M146 97.9v.4M146.9 95.7h.3M146.9 93.2h.3"/>
<path d="M146.9 90.7h.3M146.9 88.1h.3M146.9 85.6h.3M146.9 83.1h.3M146.9 80.5h.3M148 95.7h.3M148 93.2h.3M148 90.7h.3M148 88.1h.3M148 85.6h.3M148 83.1h.3M148 80.5h.3"/>
<path d="M149.1 95.7h.3M149.1 93.2h.3M149.1 90.7h.3M149.1 88.1h.3M149.1 85.6h.3M149.1 83.1h.3M149.1 80.5h.3M149.8 97.9v.4M150.1 95.7h.4M150.1 93.2h.4M150.1 90.7h.4M150.1 88.1h.4"/>
<path d="M150.1 85.6h.4M150.1 83.1h.4M150.1 80.5h.4M151.2 95.7h.4M151.2 93.2h.4M151.2 90.7h.4M151.2 88.1h.4M151.2 85.6h.4M151.2 83.1h.4M151.2 80.5h.4M152.3 95.7h.4M152.3 93.2h.4"/>
<path d="M152.3 90.7h.4M152.3 88.1h.4M152.3 85.6h.4M152.3 83.1h.4M152.3 80.5h.4M153.4 95.7h.2M153.4 93.2h.2M153.4 90.7h.2M153.4 88.1h.2M153.4 85.6h.2M153.4 83.1h.2M153.4 80.5h.2"/>
<path d="M153.6 94.7h.4M153.6 91h.4M153.6 87.4h.4M153.6 83.8h.4"/>
</g>
<path d="M153.6 72.9h-53.5v25.4h53.5" fill="none" stroke="#949698" stroke-width=".18"/>
<path d="M153.6 72.9v25.4" fill="none" stroke="#231f20" stroke-width=".18"/>
<path d="M119.4 78.1l-.3 .9-.6 2.7-.7 7.6-.4 1.6M123.4 78.3l.9 3.2M107.6 98l-1.8 .2h-5.8M112.3 96.7l-1.8 .8M117.2 90.8l.4 .1M126.5 83l-.6 .1M128.7 83h2M134.5 83h.9M147.7 82.6h2" fill="none" stroke="#231f20" stroke-width=".36"/>
<path d="M103 75.8h14.2v4.4h-14.2z" fill="#fff" stroke="#231f20" stroke-width=".16"/>
<g fill="none" stroke="#231f20" stroke-width=".36">
<path d="M103.5 76.8h6.3M119.4 78.1l2.6-2 .5-.4h.4l.5 2.6M110.5 97.5l-.9 .3-1.1 .2h-.9M117.4 90.9l-.2 1.3-.3 1.1a10.3 10.3 0 0 1-3.5 3.1l-1.1 .3M124.3 81.5l.6 1.5 .3 .3 .7-.2a2.95 2.95 0 0 1 2.8-.1h2l.9-.2h1.8l1.1 .2h.9l.9-.2h9.6l.9-.2h.9M153.5 82.4l-2 .2h-1.8M65.9 139.7l-2.5 .6h.7M66.3 139.9l-.8 .2M66.6 139.9h.7M69.1 139l-2.5 .6M69.5 139.6l-.7 .1M70.6 139.4l-.7 .2"/>
<path d="M72.4 137.9l-2.5 .9M72.7 139l-.7 .2M73.8 138.8l-.7 .2M75.6 136.7l-.2 .2-2.3 .9M76 138.3l-.7 .2M76.9 138.1l-.7 .2M78.1 134.7l-1.9 1.6M79 137.2l-.7 .4M80.1 136.9l-.7 .2M81.2 131.5l-.2 .3-1.8 1.8M82.3 136.2l-.7 .1M82.6 123l-4.1 5.1-.7 1.2-1.6 2.2-3.1 2.7-3.2 2.5-1.7 .9-3.2 1.1-7.9 1.6-5.1 .3-1.4 .4h-.5l-.4 .2h-.7l-2.4 .5h-.7l-1.6 .4a104.9 104.9 0 0 0-16 2.9l-3.2 .3"/>
<path d="M82.6 130l-.3 .4M25.8 146.4l-.7 .2M27.6 145.9l-2.5 .3M27.9 146l-.7 .2M28.3 146h.7M30.8 145.3l-2.5 .6M31.2 145.5l-.7 .2M32.3 145.1l-.8 .4M34.1 144.4l-1.1 .2-1.5 .5M34.4 144.4l-.7 .4M34.6 144.4h.7M37.1 143.9l-2.5 .3"/>
<path d="M37.5 144.1l-.7 .1M37.8 144.1h.8M40 144.1h.7M40.4 143.3l-2.6 .6M41.8 143.9l-.7 .2M43.6 143l-2.5 .3M44 143.3l-.8 .2M45 143l-.7 .2M46.8 142.4l-2.5 .6M47.2 142.4l-.7 .2M48.1 142.3l-.2 .1h-.5M49 142.3h1.4"/>
<path d="M52.8 141.9l-2.2 .4M53.1 141.5l-3 .4-.4 .2h-1.4l-.4 .2h-.5M54.6 141.5l-.8 .2M56.4 141l-2.6 .4M56.7 141l-.7 .2M59.6 140.6l-2.5 .4h.7M60 140.6l-.8 .2M62.8 140.3l-2.5 .3h.7M63.2 140.3l-.7 .2"/>
</g>
<path d="M103.5 79h6.1" fill="none" stroke="#231f20" stroke-width=".36" stroke-dasharray="2.2 .4 .4 .4" stroke-linecap="butt"/>
<g fill="none" stroke="#231f20" stroke-width=".16">
<path d="M24.8 137.3h.7M24.8 132.1h.7M24.8 126.7h.7M24.8 121.3h.7M25.1 121.3v27.2M25.1 134.8h.2M25.1 129.4h.2M25.1 124h.2M26.2 137.3h.4M26.2 132.1h.4M26.2 126.7h.4M26.2 121.3h.4"/>
<path d="M27.3 137.3h.4M27.3 132.1h.4M27.3 126.7h.4M27.3 121.3h.4M28.4 137.3h.3M28.4 132.1h.3M28.4 126.7h.3M28.4 121.3h.3M29.5 137.3h.3M29.5 132.1h.3M29.5 126.7h.3M29.5 121.3h.3"/>
<path d="M30.5 137.3h.4M30.5 132.1h.4M30.5 126.7h.4M30.5 121.3h.4M31.6 137.3h.4M31.6 132.1h.4M31.6 126.7h.4M31.6 121.3h.4M32.7 137.3h.4M32.7 132.1h.4M32.7 126.7h.4M32.7 121.3h.4"/>
<path d="M33.8 137.3h.3M33.8 132.1h.3M33.8 126.7h.3M33.8 121.3h.3M34.9 137.3h.3M34.9 132.1h.3M34.9 126.7h.3M34.9 121.3h.3M35.9 137.3h.4M35.9 132.1h.4M35.9 126.7h.4M35.9 121.3h.4"/>
<path d="M37 137.3h.4M37 132.1h.4M37 126.7h.4M37 121.3h.4M38.1 137.3h.4M38.1 132.1h.4M38.1 126.7h.4M38.1 121.3h.4M39.2 137.3h.3M39.2 132.1h.3M39.2 126.7h.3M39.2 121.3h.3"/>
<path d="M40.3 137.3h.3M40.3 132.1h.3M40.3 126.7h.3M40.3 121.3h.3M41.3 137.3h.4M41.3 132.1h.4M41.3 126.7h.4M41.3 121.3h.4M42.4 137.3h.4M42.4 132.1h.4M42.4 126.7h.4M42.4 121.3h.4"/>
<path d="M43.5 137.3h.4M43.5 132.1h.4M43.5 126.7h.4M43.5 121.3h.4M44.6 137.3h.3M44.6 132.1h.3M44.6 126.7h.3M44.6 121.3h.3M45.7 137.3h.3M45.7 132.1h.3M45.7 126.7h.3M45.7 121.3h.3"/>
<path d="M46.7 137.3h.4M46.7 132.1h.4M46.7 126.7h.4M46.7 121.3h.4M47.8 137.3h.4M47.8 132.1h.4M47.8 126.7h.4M47.8 121.3h.4M48.9 137.3h.4M48.9 132.1h.4M48.9 126.7h.4M48.9 121.3h.4"/>
<path d="M50 137.3h.3M50 132.1h.3M50 126.7h.3M50 121.3h.3M51.1 137.3h.3M51.1 132.1h.3M51.1 126.7h.3M51.1 121.3h.3M52.1 137.3h.4M52.1 132.1h.4M52.1 126.7h.4M52.1 121.3h.4"/>
<path d="M53.2 137.3h.4M53.2 132.1h.4M53.2 126.7h.4M53.2 121.3h.4M54.3 137.3h.4M54.3 132.1h.4M54.3 126.7h.4M54.3 121.3h.4M55.4 137.3h.3M55.4 132.1h.3M55.4 126.7h.3M55.4 121.3h.3"/>
<path d="M56.5 137.3h.3M56.5 132.1h.3M56.5 126.7h.3M56.5 121.3h.3M57.5 137.3h.4M57.5 132.1h.4M57.5 126.7h.4M57.5 121.3h.4M58.6 137.3h.4M58.6 132.1h.4M58.6 126.7h.4M58.6 121.3h.4"/>
<path d="M59.7 137.3h.4M59.7 132.1h.4M59.7 126.7h.4M59.7 121.3h.4M60.8 137.3h.3M60.8 132.1h.3M60.8 126.7h.3M60.8 121.3h.3M61.9 137.3h.3M61.9 132.1h.3M61.9 126.7h.3M61.9 121.3h.3"/>
<path d="M62.9 137.3h.4M62.9 132.1h.4M62.9 126.7h.4M62.9 121.3h.4M64 137.3h.4M64 132.1h.4M64 126.7h.4M64 121.3h.4M65.1 137.3h.4M65.1 132.1h.4M65.1 126.7h.4M65.1 121.3h.4"/>
<path d="M66.2 137.3h.3M66.2 132.1h.3M66.2 126.7h.3M66.2 121.3h.3M67.3 137.3h.3M67.3 132.1h.3M67.3 126.7h.3M67.3 121.3h.3M68.3 137.3h.4M68.3 132.1h.4M68.3 126.7h.4M68.3 121.3h.4"/>
<path d="M69.4 137.3h.4M69.4 132.1h.4M69.4 126.7h.4M69.4 121.3h.4M70.5 137.3h.3M70.5 132.1h.3M70.5 126.7h.3M70.5 121.3h.3M71.6 137.3h.3M71.6 132.1h.3M71.6 126.7h.3M71.6 121.3h.3"/>
<path d="M72.6 137.3h.4M72.6 132.1h.4M72.6 126.7h.4M72.6 121.3h.4M73.7 137.3h.4M73.7 132.1h.4M73.7 126.7h.4M73.7 121.3h.4M74.8 137.3h.4M74.8 132.1h.4M74.8 126.7h.4M74.8 121.3h.4"/>
<path d="M75.9 137.3h.3M75.9 132.1h.3M75.9 126.7h.3M75.9 121.3h.3M77 137.3h.3M77 132.1h.3M77 126.7h.3M77 121.3h.3M78 137.3h.4M78 132.1h.4M78 126.7h.4M78 121.3h.4"/>
<path d="M79.1 137.3h.4M79.1 132.1h.4M79.1 126.7h.4M79.1 121.3h.4M80.2 137.3h.4M80.2 132.1h.4M80.2 126.7h.4M80.2 121.3h.4M81.3 137.3h.3M81.3 132.1h.3M81.3 126.7h.3M81.3 121.3h.3"/>
<path d="M82.4 137.3h.3M82.4 132.1h.3M82.4 126.7h.3M82.4 121.3h.3M24.8 142.7h.7M24.8 148.1h.5M25.1 145.4h.2M25.1 140h.2M26.2 142.7h.4M27.3 142.7h.4M28.4 142.7h.3M29.5 142.7h.3"/>
<path d="M30.5 142.7h.4M31.6 142.7h.4M32.7 142.7h.4M33.8 142.7h.3M34.7 147.9v.6M34.9 142.7h.3M35.9 142.7h.4M37 142.7h.4M38.1 142.7h.4M39.2 142.7h.3M40.3 142.7h.3M41.3 142.7h.4"/>
<path d="M42.4 142.7h.4M43.5 142.7h.4M44.4 147.9v.6M44.6 142.7h.3M45.7 142.7h.3M46.7 142.7h.4M47.8 142.7h.4M48.9 142.7h.4M50 142.7h.3M51.1 142.7h.3M52.1 142.7h.4M53.2 142.7h.4"/>
<path d="M53.9 147.9v.6M54.3 142.7h.4M55.4 142.7h.3M56.5 142.7h.3M57.5 142.7h.4M58.6 142.7h.4M59.7 142.7h.4M60.8 142.7h.3M61.9 142.7h.3M62.9 142.7h.4M63.5 147.9v.6M64 142.7h.4"/>
<path d="M65.1 142.7h.4M66.2 142.7h.3M67.3 142.7h.3M68.3 142.7h.4M69.4 142.7h.4M70.5 142.7h.3M71.6 142.7h.3M72.6 142.7h.4M73.2 147.9v.6M73.7 142.7h.4M74.8 142.7h.4M75.9 142.7h.3"/>
<path d="M77 142.7h.3M78 142.7h.4M79.1 142.7h.4M80.2 142.7h.4M81.3 142.7h.3M82.4 142.7h.3M82.7 147.9v.6"/>
</g>
<path d="M82.7 121.3h-57.6v26.8h57.6" fill="none" stroke="#949698" stroke-width=".18"/>
<path d="M82.7 121.3v26.8h-57.6" fill="none" stroke="#231f20" stroke-width=".18"/>
<path d="M30.2 123.6h15.3v7.6h-15.3z" fill="#fff" stroke="#231f20" stroke-width=".16"/>
<g fill="none" stroke="#231f20" stroke-width=".36">
<path d="M31.2 124.8h6.3M31.2 127.2h2.5M31.2 129.7h.7M33.3 129.7h.8M35.1 127.2h2.4M35.5 129.7h.7M151.4 138.4l-.9 2.5-.3 .6M152.7 134.5l-.9 2.5M153.1 138.2l-.4 .8M154.1 136.6l-.5 .6M155.9 130.5a3.2 3.2 0 0 0-2.7 2.5M156.3 135.4l-.7 .3"/>
<path d="M156.8 122.1l-1.6 .3a2.64 2.64 0 0 0-2 2.2l-1.2 4.3a35.6 35.6 0 0 1-4.7 12.9l-.7 .9a10.9 10.9 0 0 1-8.8 1.8 20.9 20.9 0 0 1-8 0h-3l-.9 .2h-1.3a2.32 2.32 0 0 0-2.1 .2l-2 .4h-1.6l-6.5 .7h-.7l-2.4-.6h-2.5a6 6 0 0 1-3-1.8l-4-2.5 .9 .9 .7 1.1M99.8 140.4l.5 .5M101.2 142.2l.4 .5M102.5 144.2a4 4 0 0 0 3.1 1.2M102.7 144l.9 .9M105 145.6l.7 .4M106.1 145.4l2.5 .2M106.1 146.2l1.4 .3M109 146.5h1.1M109.3 145.6l2.6 .2M112.2 146.3l-.7 .2M112.4 145.8l2.5 .2"/>
<path d="M112.4 146.3h.7M114.6 146.3h.7M115.6 146.3h.8M118.2 145.6l-2.6 .4M118.5 146l-.7 .2M118.9 146h.7M118.9 145.6l2.5 .2M121 145.6h.7M122.6 145.4l-.7 .2M123.5 145.3h.8l.3 .1h.4M126.6 145.3l-.7 .1h-.7M127.7 144.9l-.9 .2h-3.3l-1.6 .7"/>
<path d="M128 145.1h1.1M130.6 144.9h.7M130.9 144.5l-2.5 .4M131.5 144.5h1.6l.9 .2M131.5 144.9h.7M133.6 144.9l.7 .2M134.7 144.7l.7 .2 .7 .4 1.1 .1M134.7 145.1h.7M136.9 145.3h.7M137.8 145.3h.7M139.9 145.4h.7M140.3 145.3l-1.8 .3h-.7"/>
<path d="M141 145.4h.7M143.2 145.6h.7M143.5 144.9l-2.5 .2M144.2 145.6h.8M146.8 144.7l-.2 .2h-2.4M147.1 145.3l-.7 .1M148.7 144.5l-1.4 .8M149.3 142.7l-.4 .6-1.6 1.2M151.1 142.4l-1.1 1.2M152 140.2l-.4 .7"/>
</g>
<g fill="none" stroke="#231f20" stroke-width=".16">
<path d="M99.5 137.3h.7M99.5 131.9h.7M99.5 126.5h.7M99.5 121.1h.7M99.9 121.1v27.3M99.9 140h.2M99.9 134.6h.2M99.9 129.2h.2M99.9 123.8h.2M101 137.3h.3M101 131.9h.3M101 126.5h.3"/>
<path d="M101 121.1h.3M102 137.3h.4M102 131.9h.4M102 126.5h.4M102 121.1h.4M103.1 137.3h.4M103.1 131.9h.4M103.1 126.5h.4M103.1 121.1h.4M104.2 137.3h.4M104.2 131.9h.4M104.2 126.5h.4"/>
<path d="M104.2 121.1h.4M105.3 137.3h.3M105.3 131.9h.3M105.3 126.5h.3M105.3 121.1h.3M106.4 137.3h.3M106.4 131.9h.3M106.4 126.5h.3M106.4 121.1h.3M107.4 137.3h.4M107.4 131.9h.4M107.4 126.5h.4"/>
<path d="M107.4 121.1h.4M108.5 137.3h.4M108.5 131.9h.4M108.5 126.5h.4M108.5 121.1h.4M109.6 137.3h.4M109.6 131.9h.4M109.6 126.5h.4M109.6 121.1h.4M110.7 137.3h.3M110.7 131.9h.3M110.7 126.5h.3"/>
<path d="M110.7 121.1h.3M111.8 137.3h.3M111.8 131.9h.3M111.8 126.5h.3M111.8 121.1h.3M112.8 137.3h.4M112.8 131.9h.4M112.8 126.5h.4M112.8 121.1h.4M113.9 137.3h.4M113.9 131.9h.4M113.9 126.5h.4"/>
<path d="M113.9 121.1h.4M115 137.3h.4M115 131.9h.4M115 126.5h.4M115 121.1h.4M116.1 137.3h.3M116.1 131.9h.3M116.1 126.5h.3M116.1 121.1h.3M117.2 137.3h.3M117.2 131.9h.3M117.2 126.5h.3"/>
<path d="M117.2 121.1h.3M118.2 137.3h.4M118.2 131.9h.4M118.2 126.5h.4M118.2 121.1h.4M119.3 137.3h.4M119.3 131.9h.4M119.3 126.5h.4M119.3 121.1h.4M120.4 137.3h.4M120.4 131.9h.4M120.4 126.5h.4"/>
<path d="M120.4 121.1h.4M121.5 137.3h.3M121.5 131.9h.3M121.5 126.5h.3M121.5 121.1h.3M122.6 137.3h.3M122.6 131.9h.3M122.6 126.5h.3M122.6 121.1h.3M123.6 137.3h.4M123.6 131.9h.4M123.6 126.5h.4"/>
<path d="M123.6 121.1h.4M124.7 137.3h.4M124.7 131.9h.4M124.7 126.5h.4M124.7 121.1h.4M125.8 137.3h.4M125.8 131.9h.4M125.8 126.5h.4M125.8 121.1h.4M126.9 137.3h.3M126.9 131.9h.3M126.9 126.5h.3"/>
<path d="M126.9 121.1h.3M128 137.3h.3M128 131.9h.3M128 126.5h.3M128 121.1h.3M129 137.3h.4M129 131.9h.4M129 126.5h.4M129 121.1h.4M130.1 137.3h.4M130.1 131.9h.4M130.1 126.5h.4"/>
<path d="M130.1 121.1h.4M131.2 137.3h.4M131.2 131.9h.4M131.2 126.5h.4M131.2 121.1h.4M132.3 137.3h.3M132.3 131.9h.3M132.3 126.5h.3M132.3 121.1h.3M133.4 137.3h.3M133.4 131.9h.3M133.4 126.5h.3"/>
<path d="M133.4 121.1h.3M134.4 137.3h.4M134.4 131.9h.4M134.4 126.5h.4M134.4 121.1h.4M135.5 137.3h.4M135.5 131.9h.4M135.5 126.5h.4M135.5 121.1h.4M136.6 137.3h.4M136.6 131.9h.4M136.6 126.5h.4"/>
<path d="M136.6 121.1h.4M137.7 137.3h.3M137.7 131.9h.3M137.7 126.5h.3M137.7 121.1h.3M138.8 137.3h.3M138.8 131.9h.3M138.8 126.5h.3M138.8 121.1h.3M139.8 137.3h.4M139.8 131.9h.4M139.8 126.5h.4"/>
<path d="M139.8 121.1h.4M140.9 137.3h.4M140.9 131.9h.4M140.9 126.5h.4M140.9 121.1h.4M142 137.3h.4M142 131.9h.4M142 126.5h.4M142 121.1h.4M143.1 137.3h.3M143.1 131.9h.3M143.1 126.5h.3"/>
<path d="M143.1 121.1h.3M144.2 137.3h.3M144.2 131.9h.3M144.2 126.5h.3M144.2 121.1h.3M145.2 137.3h.4M145.2 131.9h.4M145.2 126.5h.4M145.2 121.1h.4M146.3 137.3h.4M146.3 131.9h.4M146.3 126.5h.4"/>
<path d="M146.3 121.1h.4M147.4 137.3h.4M147.4 131.9h.4M147.4 126.5h.4M147.4 121.1h.4M148.5 137.3h.3M148.5 131.9h.3M148.5 126.5h.3M148.5 121.1h.3M149.6 137.3h.3M149.6 131.9h.3M149.6 126.5h.3"/>
<path d="M149.6 121.1h.3M150.6 137.3h.4M150.6 131.9h.4M150.6 126.5h.4M150.6 121.1h.4M151.7 137.3h.4M151.7 131.9h.4M151.7 126.5h.4M151.7 121.1h.4M152.8 137.3h.4M152.8 131.9h.4M152.8 126.5h.4"/>
<path d="M152.8 121.1h.4M153.9 137.3h.3M153.9 131.9h.3M153.9 126.5h.3M153.9 121.1h.3M154.9 137.3h.4M154.9 131.9h.4M154.9 126.5h.4M154.9 121.1h.4M156 137.3h.4M156 131.9h.4M156 126.5h.4"/>
<path d="M156 121.1h.4M99.5 142.7h.7M99.5 148h57.4M99.9 145.4h.2M101 142.7h.3M102 142.7h.4M103.1 142.7h.4M104.2 142.7h.4M104.6 147.9v.1M105.3 142.7h.3M106.4 142.7h.3M107.4 142.7h.4"/>
<path d="M108.5 142.7h.4M109.4 147.9v.5M109.6 142.7h.4M110.7 142.7h.3M111.8 142.7h.3M112.8 142.7h.4M113.9 142.7h.4M114.1 147.9v.1M115 142.7h.4M116.1 142.7h.3M117.2 142.7h.3M118.2 142.7h.4"/>
<path d="M119 147.9v.5M119.3 142.7h.4M120.4 142.7h.4M121.5 142.7h.3M122.6 142.7h.3M123.6 142.7h.4M123.6 147.9v.1M124.7 142.7h.4M125.8 142.7h.4M126.9 142.7h.3M128 142.7h.3M128.3 147.9v.1"/>
<path d="M128.5 148v.4M129 142.7h.4M130.1 142.7h.4M131.2 142.7h.4M132.3 142.7h.3M133.2 147.9v.1M133.4 142.7h.3M134.4 142.7h.4M135.5 142.7h.4M136.6 142.7h.4M137.7 142.7h.3M137.9 147.9v.5"/>
<path d="M138.8 142.7h.3M139.8 142.7h.4M140.9 142.7h.4M142 142.7h.4M142.7 147.9v.1M143.1 142.7h.3M144.2 142.7h.3M145.2 142.7h.4M146.3 142.7h.4M147.4 142.7h.4M147.4 147.9v.5M148.5 142.7h.3"/>
<path d="M149.6 142.7h.3M150.6 142.7h.4M151.7 142.7h.4M152.3 147.9v.1M152.8 142.7h.4M153.9 142.7h.3M154.9 142.7h.4M156 142.7h.4M156.9 147.9v.5"/>
</g>
<path d="M99.9 121.1h57v26.9h-57z" fill="none" stroke="#949698" stroke-width=".18"/>
<path d="M104.2 122.1h15.7v7.9h-15.7z" fill="#fff" stroke="#231f20" stroke-width=".16"/>
<g fill="none" stroke="#231f20" stroke-width=".36">
<path d="M104.8 123.9h6.3M104.8 126.2h2.6M104.8 128.7h.8M107 128.7h.7M108.8 126.2h2.3M109.2 128.7h.7M27.1 193.4l2.5 .9M27.8 190l-.7 .2M29.6 187.9l-2.5 .3M29.6 191.8l-2.5 .2M30 189.7l-.7 .1M30.5 194.5h2.5"/>
<path d="M31.2 189.5l-.7 .2M33 187l-2.5 .7M33 191.5l-2.5 .1M33.4 189.1l-.7 .2M34.1 188.9h.7M34.1 191.5h2.5M34.1 194.5h2.5M36.6 186.1l-2.5 .5M37 188.6l-.7 .2M37.5 188.6h.8M37.5 191.5h2.6M37.5 194.5h2.6"/>
<path d="M39.7 188.6h.7M40.1 185.7l-2.6 .2M41.1 185.5h2.6M41.1 188.6h.8M41.1 191.5h2.6M41.1 194.5h2.6M43.3 188.4h.7M44.6 188.4h.7M44.6 191.5h2.5M44.6 194.5h2.5M46.7 188.4h.7M47.1 185.3l-2.5 .2"/>
<path d="M48 185.3h2.5M48 188.4h.7M48 194.5h2.5M50.1 188.4h.8M50.5 191.3l-2.5 .2M51.6 185.3h2.5M51.6 188.4h.7M51.6 191.3h2.5M51.6 194.5h2.5M53.7 188.4h.8M55 188.4h.7M55 191.3h2.5"/>
<path d="M55 194.5h2.5M57.2 188.4h.7M57.5 185.2l-2.5 .1M58.4 185.2h2.5M58.4 188.4h.7M58.4 191.3h2.5M58.4 194.5h2.5M60.6 188.2h.7M62 185.2h2.5M62 188.2h.7M62 191.3h2.5M62 194.5h2.5"/>
<path d="M64.2 188.2h.7M65.4 188.2h.8M65.4 191.3h2.6M65.4 194.5h2.6M67.6 188.2h.7M68 185l-2.6 .2M69 185h2.6M69 188.2h.8M69 191.3h2.6M69 194.5h2.6M71.2 188.2h.7M72.5 185h2.5"/>
<path d="M72.5 188.2h.7M72.5 194.5h2.5M74.6 188h.7M75 191.1l-2.5 .2M75.9 188h.7M75.9 191.1h2.5M75.9 194.5h2.5M78 188h.8M78.4 184.8l-2.5 .2M79.5 184.8h2.5M79.5 188h.7M79.5 191.1h2.5"/>
<path d="M79.5 194.5h2.5M81.6 188h.7M82.9 181.7h-5.2l-1.8 .2h-5.1l-1.8 .2h-8.8l-1.8 .2h-6.8l-7 .3a24.2 24.2 0 0 0-10.5 2.2l-7 1.6"/>
</g>
<g fill="none" stroke="#231f20" stroke-width=".16">
<path d="M26.8 178h.8M26.8 174.3h.8M26.8 170.5h.8M27.2 170.5v26.8M27.2 176.2h.4M27.2 172.5h.4M28.3 178h.3M28.3 174.3h.3M28.3 170.5h.3M29.4 178h.3M29.4 174.3h.3M29.4 170.5h.3"/>
<path d="M30.4 178h.4M30.4 174.3h.4M30.4 170.5h.4M31.5 178h.4M31.5 174.3h.4M31.5 170.5h.4M32.6 178h.4M32.6 174.3h.4M32.6 170.5h.4M33.7 178h.3M33.7 174.3h.3M33.7 170.5h.3"/>
<path d="M34.8 178h.3M34.8 174.3h.3M34.8 170.5h.3M35.8 178h.4M35.8 174.3h.4M35.8 170.5h.4M36.9 178h.4M36.9 174.3h.4M36.9 170.5h.4M38 178h.4M38 174.3h.4M38 170.5h.4"/>
<path d="M39.1 178h.3M39.1 174.3h.3M39.1 170.5h.3M40.2 178h.3M40.2 174.3h.3M40.2 170.5h.3M41.2 178h.4M41.2 174.3h.4M41.2 170.5h.4M42.3 178h.4M42.3 174.3h.4M42.3 170.5h.4"/>
<path d="M43.4 178h.4M43.4 174.3h.4M43.4 170.5h.4M44.5 178h.3M44.5 174.3h.3M44.5 170.5h.3M45.6 178h.3M45.6 174.3h.3M45.6 170.5h.3M46.6 178h.4M46.6 174.3h.4M46.6 170.5h.4"/>
<path d="M47.7 178h.4M47.7 174.3h.4M47.7 170.5h.4M48.8 178h.3M48.8 174.3h.3M48.8 170.5h.3M49.9 178h.3M49.9 174.3h.3M49.9 170.5h.3M50.9 178h.4M50.9 174.3h.4M50.9 170.5h.4"/>
<path d="M52 178h.4M52 174.3h.4M52 170.5h.4M53.1 178h.4M53.1 174.3h.4M53.1 170.5h.4M54.2 178h.3M54.2 174.3h.3M54.2 170.5h.3M55.3 178h.3M55.3 174.3h.3M55.3 170.5h.3"/>
<path d="M56.3 178h.4M56.3 174.3h.4M56.3 170.5h.4M57.4 178h.4M57.4 174.3h.4M57.4 170.5h.4M58.5 178h.4M58.5 174.3h.4M58.5 170.5h.4M59.6 178h.3M59.6 174.3h.3M59.6 170.5h.3"/>
<path d="M60.7 178h.3M60.7 174.3h.3M60.7 170.5h.3M61.7 178h.4M61.7 174.3h.4M61.7 170.5h.4M62.8 178h.4M62.8 174.3h.4M62.8 170.5h.4M63.9 178h.4M63.9 174.3h.4M63.9 170.5h.4"/>
<path d="M65 178h.3M65 174.3h.3M65 170.5h.3M66.1 178h.3M66.1 174.3h.3M66.1 170.5h.3M67.1 178h.4M67.1 174.3h.4M67.1 170.5h.4M68.2 178h.4M68.2 174.3h.4M68.2 170.5h.4"/>
<path d="M69.3 178h.4M69.3 174.3h.4M69.3 170.5h.4M70.4 178h.3M70.4 174.3h.3M70.4 170.5h.3M71.5 178h.3M71.5 174.3h.3M71.5 170.5h.3M72.5 178h.4M72.5 174.3h.4M72.5 170.5h.4"/>
<path d="M73.6 178h.4M73.6 174.3h.4M73.6 170.5h.4M74.7 178h.4M74.7 174.3h.4M74.7 170.5h.4M75.8 178h.3M75.8 174.3h.3M75.8 170.5h.3M76.9 178h.3M76.9 174.3h.3M76.9 170.5h.3"/>
<path d="M77.9 178h.4M77.9 174.3h.4M77.9 170.5h.4M79 178h.4M79 174.3h.4M79 170.5h.4M80.1 178h.4M80.1 174.3h.4M80.1 170.5h.4M81.2 178h.3M81.2 174.3h.3M81.2 170.5h.3"/>
<path d="M82.3 178h.3M82.3 174.3h.3M82.3 170.5h.3M26.8 193.2h.8M26.8 189.4h.8M26.8 185.6h.8M26.8 181.8h.8M26.8 196.9h56.2M27.2 195.1h.4M27.2 191.4h.4M27.2 187.6h.4M27.2 183.8h.4"/>
<path d="M27.2 180h.4M28.3 193.2h.3M28.3 189.4h.3M28.3 185.6h.3M28.3 181.8h.3M29.4 193.2h.3M29.4 189.4h.3M29.4 185.6h.3M29.4 181.8h.3M30.4 193.2h.4M30.4 189.4h.4M30.4 185.6h.4"/>
<path d="M30.4 181.8h.4M31.5 193.2h.4M31.5 189.4h.4M31.5 185.6h.4M31.5 181.8h.4M32.6 193.2h.4M32.6 189.4h.4M32.6 185.6h.4M32.6 181.8h.4M33.7 193.2h.3M33.7 189.4h.3M33.7 185.6h.3"/>
<path d="M33.7 181.8h.3M34.2 196.6v.3M34.8 193.2h.3M34.8 189.4h.3M34.8 185.6h.3M34.8 181.8h.3M35.8 193.2h.4M35.8 189.4h.4M35.8 185.6h.4M35.8 181.8h.4M36.9 193.2h.4M36.9 189.4h.4"/>
<path d="M36.9 185.6h.4M36.9 181.8h.4M38 193.2h.4M38 189.4h.4M38 185.6h.4M38 181.8h.4M39.1 193.2h.3M39.1 189.4h.3M39.1 185.6h.3M39.1 181.8h.3M40.2 193.2h.3M40.2 189.4h.3"/>
<path d="M40.2 185.6h.3M40.2 181.8h.3M41.2 193.2h.4M41.2 189.4h.4M41.2 185.6h.4M41.2 181.8h.4M41.2 196.6v.7M42.3 193.2h.4M42.3 189.4h.4M42.3 185.6h.4M42.3 181.8h.4M43.4 193.2h.4"/>
<path d="M43.4 189.4h.4M43.4 185.6h.4M43.4 181.8h.4M44.5 193.2h.3M44.5 189.4h.3M44.5 185.6h.3M44.5 181.8h.3M45.6 193.2h.3M45.6 189.4h.3M45.6 185.6h.3M45.6 181.8h.3M46.6 193.2h.4"/>
<path d="M46.6 189.4h.4M46.6 185.6h.4M46.6 181.8h.4M47.7 193.2h.4M47.7 189.4h.4M47.7 185.6h.4M47.7 181.8h.4M48.1 196.6v.3M48.8 193.2h.3M48.8 189.4h.3M48.8 185.6h.3M48.8 181.8h.3"/>
<path d="M49.9 193.2h.3M49.9 189.4h.3M49.9 185.6h.3M49.9 181.8h.3M50.9 193.2h.4M50.9 189.4h.4M50.9 185.6h.4M50.9 181.8h.4M52 193.2h.4M52 189.4h.4M52 185.6h.4M52 181.8h.4"/>
<path d="M53.1 193.2h.4M53.1 189.4h.4M53.1 185.6h.4M53.1 181.8h.4M54.2 193.2h.3M54.2 189.4h.3M54.2 185.6h.3M54.2 181.8h.3M55.1 196.6v.7M55.3 193.2h.3M55.3 189.4h.3M55.3 185.6h.3"/>
<path d="M55.3 181.8h.3M56.3 193.2h.4M56.3 189.4h.4M56.3 185.6h.4M56.3 181.8h.4M57.4 193.2h.4M57.4 189.4h.4M57.4 185.6h.4M57.4 181.8h.4M58.5 193.2h.4M58.5 189.4h.4M58.5 185.6h.4"/>
<path d="M58.5 181.8h.4M59.6 193.2h.3M59.6 189.4h.3M59.6 185.6h.3M59.6 181.8h.3M60.7 193.2h.3M60.7 189.4h.3M60.7 185.6h.3M60.7 181.8h.3M61.7 193.2h.4M61.7 189.4h.4M61.7 185.6h.4"/>
<path d="M61.7 181.8h.4M62.1 196.6v.3M62.8 193.2h.4M62.8 189.4h.4M62.8 185.6h.4M62.8 181.8h.4M63.9 193.2h.4M63.9 189.4h.4M63.9 185.6h.4M63.9 181.8h.4M65 193.2h.3M65 189.4h.3"/>
<path d="M65 185.6h.3M65 181.8h.3M66.1 193.2h.3M66.1 189.4h.3M66.1 185.6h.3M66.1 181.8h.3M67.1 193.2h.4M67.1 189.4h.4M67.1 185.6h.4M67.1 181.8h.4M68.2 193.2h.4M68.2 189.4h.4"/>
<path d="M68.2 185.6h.4M68.2 181.8h.4M69.1 196.6v.7M69.3 193.2h.4M69.3 189.4h.4M69.3 185.6h.4M69.3 181.8h.4M70.4 193.2h.3M70.4 189.4h.3M70.4 185.6h.3M70.4 181.8h.3M71.5 193.2h.3"/>
<path d="M71.5 189.4h.3M71.5 185.6h.3M71.5 181.8h.3M72.5 193.2h.4M72.5 189.4h.4M72.5 185.6h.4M72.5 181.8h.4M73.6 193.2h.4M73.6 189.4h.4M73.6 185.6h.4M73.6 181.8h.4M74.7 193.2h.4"/>
<path d="M74.7 189.4h.4M74.7 185.6h.4M74.7 181.8h.4M75.8 193.2h.3M75.8 189.4h.3M75.8 185.6h.3M75.8 181.8h.3M76 196.6v.3M76.9 193.2h.3M76.9 189.4h.3M76.9 185.6h.3M76.9 181.8h.3"/>
<path d="M77.9 193.2h.4M77.9 189.4h.4M77.9 185.6h.4M77.9 181.8h.4M79 193.2h.4M79 189.4h.4M79 185.6h.4M79 181.8h.4M80.1 193.2h.4M80.1 189.4h.4M80.1 185.6h.4M80.1 181.8h.4"/>
<path d="M81.2 193.2h.3M81.2 189.4h.3M81.2 185.6h.3M81.2 181.8h.3M82.3 193.2h.3M82.3 189.4h.3M82.3 185.6h.3M82.3 181.8h.3M83 196.6v.7"/>
</g>
<path d="M27.2 170.5h55.8v26.4h-55.8z" fill="none" stroke="#949698" stroke-width=".18"/>
<path d="M30.9 171.4h17.5v10h-17.5z" fill="#fff" stroke="#231f20" stroke-width=".16"/>
<g fill="none" stroke="#231f20" stroke-width=".36">
<path d="M32.9 172.7h6.3M32.9 174.7h2.5M32.9 176.7h.7M32.9 178.5h2.5M35 176.7h.7M36.8 174.7h2.4M36.8 178.5h.7M37.2 176.7h.7M39 178.5h.2M142.6 179.9l-.7 .4M144.1 179.4l-.7 .3M145.9 177.9l-2.5 1.1-1.8 .6"/>
<path d="M146.2 178.7l-.7 .1M148.4 177.8l-.7 .1M149.7 177.2l-.8 .4M151.5 175.8l-.8 .2-3.4 1.4M151.8 176.5l-.7 .2M154 176l-.7 .1M155.2 174.3l-2.3 .9M156.1 175.2l-.7 .2M157.2 172.7l-2.1 .9-2.2 .7-9.5 4a172.2 172.2 0 0 0-12.1 4.9l-7 2.8a125 125 0 0 0-14.2 5.8l-4.5 1.6-2 .9-1.1 .7 3.1-1.4 1.4-.6M157.2 173.6l-.5 .2M32.9 180.5h2.5M36.8 180.5h.7"/>
<path d="M39 180.5h.2M101.8 195.2h.4M102.2 195.2l-.4 .2M102.9 194.8l-.7 .4M105.2 194.1l-.9 .2M107.4 193l-.7 .4M109.5 192.3l-.7 .4M110.8 191.8l-.7 .3M112.4 190.9l-2.3 1.1-1.6 .5M113.5 190.7l-.7 .2-.7 .4M115.5 189.8l-.7 .4M116.4 189.5l-.7 .3"/>
<path d="M118 188.7l-4.1 1.7M119.1 188.6l-1.5 .3M122 187.5l-.8 .3-.7 .2M123.8 186.6l-4.4 1.6M124.1 186.8l-.7 .3M126.3 186l-.7 .2M127.5 185.5l-.7 .4M129.3 184.4l-1 .4-1.5 .7-1.6 .5M130.2 184.6l-1.2 .4M132 183.3l-.7 .4-1.8 .5M132.9 183.5l-1.2 .6M134.7 182.3l-2.5 1"/>
<path d="M135.1 182.6l-.7 .4M137.2 181.9l-.7 .4M138.5 181.5l-.7 .2M140.1 180.1l-3.9 1.4M140.7 180.6l-.8 .4"/>
</g>
<g fill="none" stroke="#231f20" stroke-width=".16">
<path d="M101.5 177.1h.8M101.5 173.7h.8M101.5 170.5h.8M101.9 170.5v26.8M103 177.1h.3M103 173.7h.3M103 170.5h.3M104.1 177.1h.3M104.1 173.7h.3M104.1 170.5h.3M105.1 177.1h.4M105.1 173.7h.4"/>
<path d="M105.1 170.5h.4M106.2 177.1h.4M106.2 173.7h.4M106.2 170.5h.4M107.3 177.1h.4M107.3 173.7h.4M107.3 170.5h.4M108.4 177.1h.3M108.4 173.7h.3M108.4 170.5h.3M109.5 177.1h.3M109.5 173.7h.3"/>
<path d="M109.5 170.5h.3M110.5 177.1h.4M110.5 173.7h.4M110.5 170.5h.4M111.6 177.1h.4M111.6 173.7h.4M111.6 170.5h.4M112.7 177.1h.4M112.7 173.7h.4M112.7 170.5h.4M113.8 177.1h.3M113.8 173.7h.3"/>
<path d="M113.8 170.5h.3M114.8 177.1h.4M114.8 173.7h.4M114.8 170.5h.4M115.9 177.1h.4M115.9 173.7h.4M115.9 170.5h.4M117 177.1h.4M117 173.7h.4M117 170.5h.4M118.1 177.1h.3M118.1 173.7h.3"/>
<path d="M118.1 170.5h.3M119.2 177.1h.3M119.2 173.7h.3M119.2 170.5h.3M120.2 177.1h.4M120.2 173.7h.4M120.2 170.5h.4M121.3 177.1h.4M121.3 173.7h.4M121.3 170.5h.4M122.4 177.1h.4M122.4 173.7h.4"/>
<path d="M122.4 170.5h.4M123.5 177.1h.3M123.5 173.7h.3M123.5 170.5h.3M124.6 177.1h.3M124.6 173.7h.3M124.6 170.5h.3M125.6 177.1h.4M125.6 173.7h.4M125.6 170.5h.4M126.7 177.1h.4M126.7 173.7h.4"/>
<path d="M126.7 170.5h.4M127.8 177.1h.4M127.8 173.7h.4M127.8 170.5h.4M128.9 177.1h.3M128.9 173.7h.3M128.9 170.5h.3M130 177.1h.3M130 173.7h.3M130 170.5h.3M131 177.1h.4M131 173.7h.4"/>
<path d="M131 170.5h.4M132.1 177.1h.4M132.1 173.7h.4M132.1 170.5h.4M133.2 177.1h.4M133.2 173.7h.4M133.2 170.5h.4M134.3 177.1h.3M134.3 173.7h.3M134.3 170.5h.3M135.4 177.1h.3M135.4 173.7h.3"/>
<path d="M135.4 170.5h.3M136.4 177.1h.4M136.4 173.7h.4M136.4 170.5h.4M137.5 177.1h.4M137.5 173.7h.4M137.5 170.5h.4M138.6 177.1h.4M138.6 173.7h.4M138.6 170.5h.4M139.7 177.1h.3M139.7 173.7h.3"/>
<path d="M139.7 170.5h.3M140.8 177.1h.3M140.8 173.7h.3M140.8 170.5h.3M141.8 177.1h.4M141.8 173.7h.4M141.8 170.5h.4M142.9 177.1h.4M142.9 173.7h.4M142.9 170.5h.4M144 177.1h.4M144 173.7h.4"/>
<path d="M144 170.5h.4M145.1 177.1h.3M145.1 173.7h.3M145.1 170.5h.3M146.2 177.1h.3M146.2 173.7h.3M146.2 170.5h.3M147.2 177.1h.4M147.2 173.7h.4M147.2 170.5h.4M148.3 177.1h.4M148.3 173.7h.4"/>
<path d="M148.3 170.5h.4M149.4 177.1h.4M149.4 173.7h.4M149.4 170.5h.4M150.5 177.1h.3M150.5 173.7h.3M150.5 170.5h.3M151.6 177.1h.3M151.6 173.7h.3M151.6 170.5h.3M152.6 177.1h.4M152.6 173.7h.4"/>
<path d="M152.6 170.5h.4M153.7 177.1h.4M153.7 173.7h.4M153.7 170.5h.4M154.8 177.1h.4M154.8 173.7h.4M154.8 170.5h.4M155.9 177.1h.3M155.9 173.7h.3M155.9 170.5h.3M157 177.1h.3M157 173.7h.3"/>
<path d="M157 170.5h.3M101.5 193.7h.8M101.5 190.3h.8M101.5 187h.8M101.5 183.8h.8M101.5 180.4h.8M101.5 196.9h55.8M103 193.7h.3M103 190.3h.3M103 187h.3M103 183.8h.3M103 180.4h.3"/>
<path d="M104.1 193.7h.3M104.1 190.3h.3M104.1 187h.3M104.1 183.8h.3M104.1 180.4h.3M105.1 193.7h.4M105.1 190.3h.4M105.1 187h.4M105.1 183.8h.4M105.1 180.4h.4M106.2 193.7h.4M106.2 190.3h.4"/>
<path d="M106.2 187h.4M106.2 183.8h.4M106.2 180.4h.4M107.3 193.7h.4M107.3 190.3h.4M107.3 187h.4M107.3 183.8h.4M107.3 180.4h.4M108.4 193.7h.3M108.4 190.3h.3M108.4 187h.3M108.4 183.8h.3"/>
<path d="M108.4 180.4h.3M108.9 196.6v.3M109.5 193.7h.3M109.5 190.3h.3M109.5 187h.3M109.5 183.8h.3M109.5 180.4h.3M110.5 193.7h.4M110.5 190.3h.4M110.5 187h.4M110.5 183.8h.4M110.5 180.4h.4"/>
<path d="M111.6 193.7h.4M111.6 190.3h.4M111.6 187h.4M111.6 183.8h.4M111.6 180.4h.4M112.7 193.7h.4M112.7 190.3h.4M112.7 187h.4M112.7 183.8h.4M112.7 180.4h.4M113.8 193.7h.3M113.8 190.3h.3"/>
<path d="M113.8 187h.3M113.8 183.8h.3M113.8 180.4h.3M114.8 193.7h.4M114.8 190.3h.4M114.8 187h.4M114.8 183.8h.4M114.8 180.4h.4M115.7 196.6v.7M115.9 193.7h.4M115.9 190.3h.4M115.9 187h.4"/>
<path d="M115.9 183.8h.4M115.9 180.4h.4M117 193.7h.4M117 190.3h.4M117 187h.4M117 183.8h.4M117 180.4h.4M118.1 193.7h.3M118.1 190.3h.3M118.1 187h.3M118.1 183.8h.3M118.1 180.4h.3"/>
<path d="M119.2 193.7h.3M119.2 190.3h.3M119.2 187h.3M119.2 183.8h.3M119.2 180.4h.3M120.2 193.7h.4M120.2 190.3h.4M120.2 187h.4M120.2 183.8h.4M120.2 180.4h.4M121.3 193.7h.4M121.3 190.3h.4"/>
<path d="M121.3 187h.4M121.3 183.8h.4M121.3 180.4h.4M122.4 193.7h.4M122.4 190.3h.4M122.4 187h.4M122.4 183.8h.4M122.4 180.4h.4M122.8 196.6v.3M123.5 193.7h.3M123.5 190.3h.3M123.5 187h.3"/>
<path d="M123.5 183.8h.3M123.5 180.4h.3M124.6 193.7h.3M124.6 190.3h.3M124.6 187h.3M124.6 183.8h.3M124.6 180.4h.3M125.6 193.7h.4M125.6 190.3h.4M125.6 187h.4M125.6 183.8h.4M125.6 180.4h.4"/>
<path d="M126.7 193.7h.4M126.7 190.3h.4M126.7 187h.4M126.7 183.8h.4M126.7 180.4h.4M127.8 193.7h.4M127.8 190.3h.4M127.8 187h.4M127.8 183.8h.4M127.8 180.4h.4M128.9 193.7h.3M128.9 190.3h.3"/>
<path d="M128.9 187h.3M128.9 183.8h.3M128.9 180.4h.3M129.6 196.6v.7M130 193.7h.3M130 190.3h.3M130 187h.3M130 183.8h.3M130 180.4h.3M131 193.7h.4M131 190.3h.4M131 187h.4"/>
<path d="M131 183.8h.4M131 180.4h.4M132.1 193.7h.4M132.1 190.3h.4M132.1 187h.4M132.1 183.8h.4M132.1 180.4h.4M133.2 193.7h.4M133.2 190.3h.4M133.2 187h.4M133.2 183.8h.4M133.2 180.4h.4"/>
<path d="M134.3 193.7h.3M134.3 190.3h.3M134.3 187h.3M134.3 183.8h.3M134.3 180.4h.3M135.4 193.7h.3M135.4 190.3h.3M135.4 187h.3M135.4 183.8h.3M135.4 180.4h.3M136.4 193.7h.4M136.4 190.3h.4"/>
<path d="M136.4 187h.4M136.4 183.8h.4M136.4 180.4h.4M136.6 196.6v.3M137.5 193.7h.4M137.5 190.3h.4M137.5 187h.4M137.5 183.8h.4M137.5 180.4h.4M138.6 193.7h.4M138.6 190.3h.4M138.6 187h.4"/>
<path d="M138.6 183.8h.4M138.6 180.4h.4M139.7 193.7h.3M139.7 190.3h.3M139.7 187h.3M139.7 183.8h.3M139.7 180.4h.3M140.8 193.7h.3M140.8 190.3h.3M140.8 187h.3M140.8 183.8h.3M140.8 180.4h.3"/>
<path d="M141.8 193.7h.4M141.8 190.3h.4M141.8 187h.4M141.8 183.8h.4M141.8 180.4h.4M142.9 193.7h.4M142.9 190.3h.4M142.9 187h.4M142.9 183.8h.4M142.9 180.4h.4M143.5 196.6v.7M144 193.7h.4"/>
<path d="M144 190.3h.4M144 187h.4M144 183.8h.4M144 180.4h.4M145.1 193.7h.3M145.1 190.3h.3M145.1 187h.3M145.1 183.8h.3M145.1 180.4h.3M146.2 193.7h.3M146.2 190.3h.3M146.2 187h.3"/>
<path d="M146.2 183.8h.3M146.2 180.4h.3M147.2 193.7h.4M147.2 190.3h.4M147.2 187h.4M147.2 183.8h.4M147.2 180.4h.4M148.3 193.7h.4M148.3 190.3h.4M148.3 187h.4M148.3 183.8h.4M148.3 180.4h.4"/>
<path d="M149.4 193.7h.4M149.4 190.3h.4M149.4 187h.4M149.4 183.8h.4M149.4 180.4h.4M150.5 193.7h.3M150.5 190.3h.3M150.5 187h.3M150.5 183.8h.3M150.5 180.4h.3M150.5 196.6v.3M151.6 193.7h.3"/>
<path d="M151.6 190.3h.3M151.6 187h.3M151.6 183.8h.3M151.6 180.4h.3M152.6 193.7h.4M152.6 190.3h.4M152.6 187h.4M152.6 183.8h.4M152.6 180.4h.4M153.7 193.7h.4M153.7 190.3h.4M153.7 187h.4"/>
<path d="M153.7 183.8h.4M153.7 180.4h.4M154.8 193.7h.4M154.8 190.3h.4M154.8 187h.4M154.8 183.8h.4M154.8 180.4h.4M155.9 193.7h.3M155.9 190.3h.3M155.9 187h.3M155.9 183.8h.3M155.9 180.4h.3"/>
<path d="M157 193.7h.3M157 190.3h.3M157 187h.3M157 183.8h.3M157 180.4h.3M157.3 196.6v.7"/>
</g>
<path d="M101.9 170.5h55.4v26.4" fill="none" stroke="#231f20" stroke-width=".18"/>
<path d="M101.9 170.5v26.4h55.4" fill="none" stroke="#949698" stroke-width=".18"/>
<path d="M105.3 171.5h15.7v7.8h-15.7z" fill="#fff" stroke="#231f20" stroke-width=".16"/>
<path d="M106.1 173.1h6.3M106.1 175.6h2.5M106.1 177.9h.7M108.3 177.9h.7M110.1 175.6h2.3M110.4 177.9h.8" fill="none" stroke="#231f20" stroke-width=".36"/>
<path d="M19.3 10.8h88.9" fill="none" stroke="#231f20" stroke-width=".7" stroke-linecap="butt"/>
<use href="#words"/>
</svg>
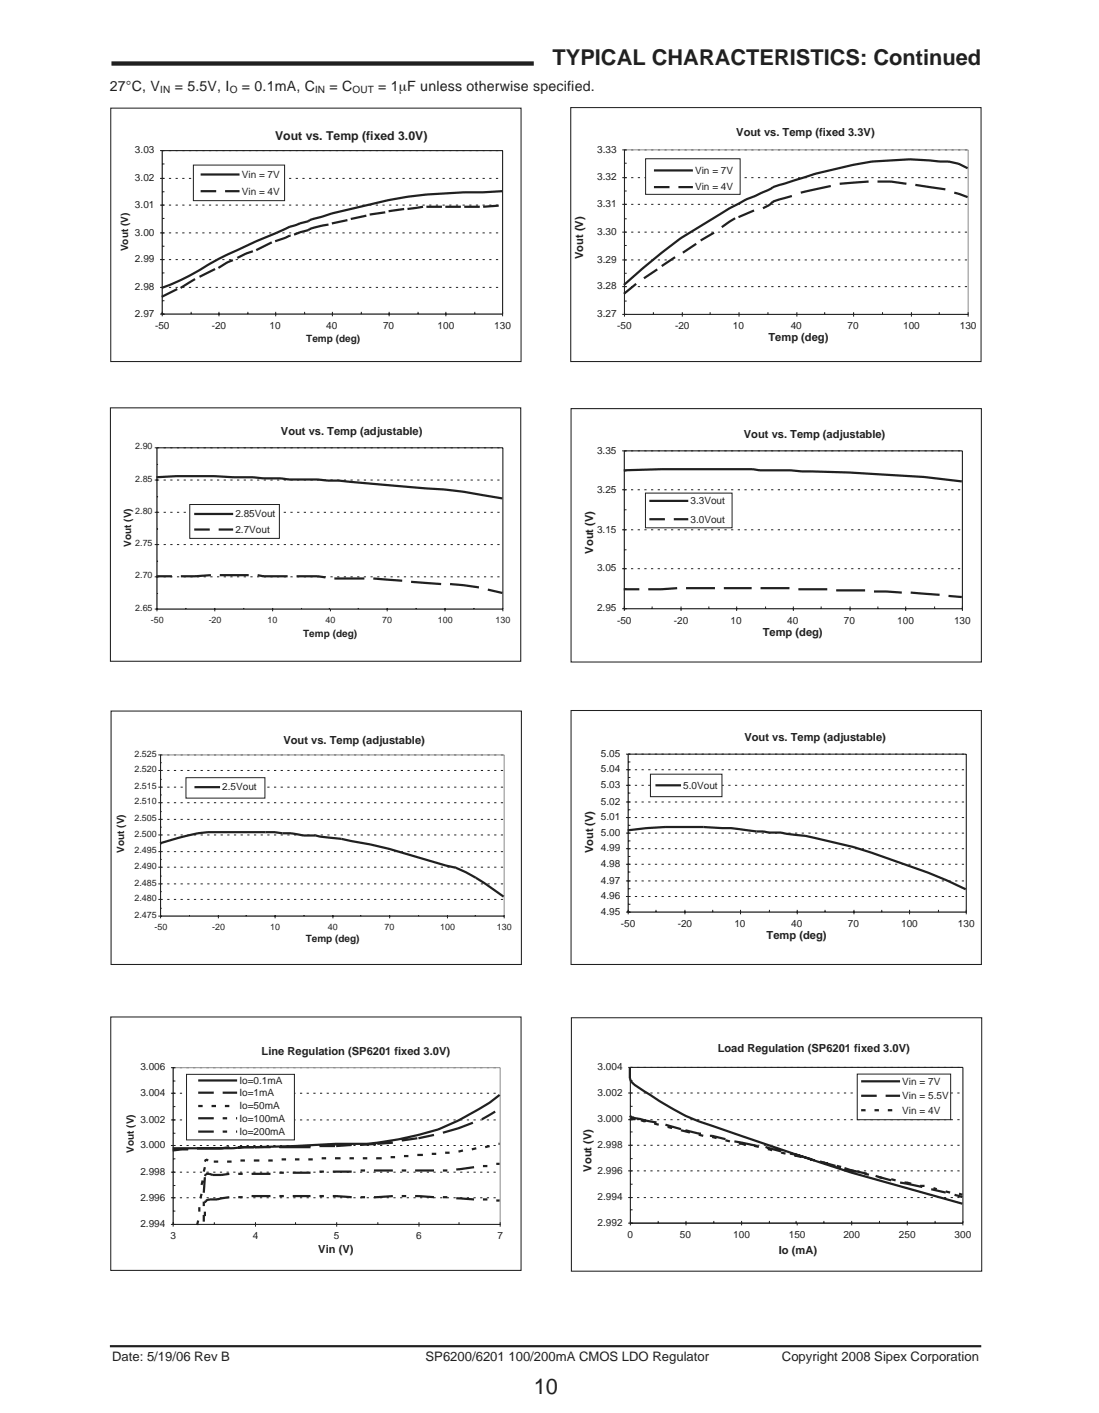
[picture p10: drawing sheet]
<svg xmlns="http://www.w3.org/2000/svg" width="178mm" height="229mm" viewBox="0 0 178 229" stroke-linecap="round" stroke-linejoin="round" font-family="sans-serif">
<defs><g id="words">
<g font-size="3.5" fill="#231f20">
<text x="89.4" y="10.5">TYPICAL CHARACTERISTICS: Continued</text>
<text x="86.3" y="225.6">10</text>
</g>
<g font-size="2.3" fill="#231f20">
<text x="17.8" y="14.7">27°C, V</text>
<text x="28.3" y="14.7">= 5.5V, I</text>
<text x="39.1" y="14.7">= 0.1mA, C</text>
<text x="53.3" y="14.7">= C</text>
<text x="61.2" y="14.7">= 1µF unless otherwise specified.</text>
</g>
<g font-size="2.1" fill="#231f20">
<text x="18.1" y="220.2">Date: 5/19/06 Rev B</text>
<text x="68.9" y="220.2">SP6200/6201 100/200mA CMOS LDO Regulator</text>
<text x="126.5" y="220.2">Copyright 2008 Sipex Corporation</text>
</g>
<text font-size="2" fill="#231f20" x="44.5" y="22.7">Vout vs. Temp (fixed 3.0V)</text>
<g font-size="1.8" fill="#231f20">
<text x="119.1" y="22">Vout vs. Temp (fixed 3.3V)</text>
<text x="94.3" y="41.9" transform="rotate(-90 94.3 41.9)">Vout (V)</text>
<text x="124.3" y="55.1">Temp (deg)</text>
<text x="45.5" y="70.4">Vout vs. Temp (adjustable)</text>
<text x="120.3" y="70.9">Vout vs. Temp (adjustable)</text>
<text x="96" y="89.6" transform="rotate(-90 96 89.6)">Vout (V)</text>
<text x="123.4" y="102.9">Temp (deg)</text>
<text x="120.4" y="119.9">Vout vs. Temp (adjustable)</text>
<text x="45.9" y="120.4">Vout vs. Temp (adjustable)</text>
<text x="96" y="138.1" transform="rotate(-90 96 138.1)">Vout (V)</text>
<text x="124" y="152">Temp (deg)</text>
<text x="42.3" y="170.7">Line Regulation (SP6201 fixed 3.0V)</text>
<text x="116.1" y="170.3">Load Regulation (SP6201 fixed 3.0V)</text>
<text x="95.7" y="189.5" transform="rotate(-90 95.7 189.5)">Vout (V)</text>
<text x="51.5" y="202.7">Vin (V)</text>
<text x="126" y="202.9">Io (mA)</text>
</g>
<g font-size="1.6" fill="#231f20">
<text x="25.9" y="15.1">IN</text>
<text x="37.2" y="15.1">O</text>
<text x="51" y="15.1">IN</text>
<text x="57" y="15.1">OUT</text>
<text x="21.8" y="29.3">3.02</text>
<text x="21.8" y="24.8">3.03</text>
<text x="39.1" y="28.8">Vin = 7V</text>
<text x="96.6" y="29.2">3.32</text>
<text x="96.6" y="24.7">3.33</text>
<text x="112.5" y="28.1">Vin = 7V</text>
<text x="21.8" y="33.6">3.01</text>
<text x="39.1" y="31.5">Vin = 4V</text>
<text x="96.6" y="33.5">3.31</text>
<text x="112.5" y="30.8">Vin = 4V</text>
<text x="20.7" y="40.6" transform="rotate(-90 20.7 40.6)">Vout (V)</text>
<text x="21.8" y="38.1">3.00</text>
<text x="96.6" y="38">3.30</text>
<text x="21.8" y="46.9">2.98</text>
<text x="21.8" y="42.4">2.99</text>
<text x="96.6" y="46.8">3.28</text>
<text x="96.6" y="42.5">3.29</text>
<text x="21.8" y="51.3">2.97</text>
<text x="25.1" y="53.2">-50</text>
<text x="34.3" y="53.2">-20</text>
<text x="43.6" y="53.2">10</text>
<text x="52.8" y="53.2">40</text>
<text x="62" y="53.2">70</text>
<text x="70.8" y="53.2">100</text>
<text x="80" y="53.2">130</text>
<text x="96.6" y="51.3">3.27</text>
<text x="99.9" y="53.3">-50</text>
<text x="109.2" y="53.3">-20</text>
<text x="118.6" y="53.3">10</text>
<text x="127.9" y="53.3">40</text>
<text x="137.1" y="53.3">70</text>
<text x="146.1" y="53.3">100</text>
<text x="155.3" y="53.3">130</text>
<text x="49.6" y="55.4">Temp (deg)</text>
<text x="96.6" y="73.4">3.35</text>
<text x="38.1" y="83.7">2.85Vout</text>
<text x="96.6" y="79.7">3.25</text>
<text x="111.7" y="81.6">3.3Vout</text>
<text x="21.2" y="88.4" transform="rotate(-90 21.2 88.4)">Vout (V)</text>
<text x="38.1" y="86.2">2.7Vout</text>
<text x="96.6" y="86.2">3.15</text>
<text x="111.7" y="84.5">3.0Vout</text>
<text x="96.6" y="92.5">3.05</text>
<text x="96.6" y="98.9">2.95</text>
<text x="99.8" y="100.9">-50</text>
<text x="109" y="100.9">-20</text>
<text x="118.2" y="100.9">10</text>
<text x="127.4" y="100.9">40</text>
<text x="136.5" y="100.9">70</text>
<text x="145.2" y="100.9">100</text>
<text x="154.3" y="100.9">130</text>
<text x="49.1" y="103.1">Temp (deg)</text>
<text x="97.2" y="125">5.04</text>
<text x="97.2" y="122.5">5.05</text>
<text x="36" y="127.9">2.5Vout</text>
<text x="97.2" y="130.2">5.02</text>
<text x="97.2" y="127.5">5.03</text>
<text x="110.5" y="127.6">5.0Vout</text>
<text x="20.1" y="137.9" transform="rotate(-90 20.1 137.9)">Vout (V)</text>
<text x="97.2" y="137.8">4.99</text>
<text x="97.2" y="135.2">5.00</text>
<text x="97.2" y="132.7">5.01</text>
<text x="97.2" y="143">4.97</text>
<text x="97.2" y="140.3">4.98</text>
<text x="97.2" y="148">4.95</text>
<text x="97.2" y="145.5">4.96</text>
<text x="100.5" y="150">-50</text>
<text x="109.6" y="150">-20</text>
<text x="118.8" y="150">10</text>
<text x="128" y="150">40</text>
<text x="137.2" y="150">70</text>
<text x="145.8" y="150">100</text>
<text x="155" y="150">130</text>
<text x="49.5" y="152.4">Temp (deg)</text>
<text x="22.7" y="173.2">3.006</text>
<text x="96.7" y="173.1">3.004</text>
<text x="22.7" y="177.3">3.004</text>
<text x="38.7" y="175.3">Io=0.1mA</text>
<text x="38.7" y="177.3">Io=1mA</text>
<text x="38.7" y="179.5">Io=50mA</text>
<text x="96.7" y="177.3">3.002</text>
<text x="146" y="175.5">Vin = 7V</text>
<text x="146" y="177.8">Vin = 5.5V</text>
<text x="22.7" y="185.8">3.000</text>
<text x="22.7" y="181.6">3.002</text>
<text x="38.7" y="181.5">Io=100mA</text>
<text x="38.7" y="183.6">Io=200mA</text>
<text x="96.7" y="185.7">2.998</text>
<text x="96.7" y="181.6">3.000</text>
<text x="146" y="180.2">Vin = 4V</text>
<text x="21.6" y="186.5" transform="rotate(-90 21.6 186.5)">Vout (V)</text>
<text x="22.7" y="190.1">2.998</text>
<text x="96.7" y="189.9">2.996</text>
<text x="22.7" y="194.2">2.996</text>
<text x="96.7" y="194.2">2.994</text>
<text x="22.7" y="198.5">2.994</text>
<text x="27.6" y="200.5">3</text>
<text x="40.9" y="200.5">4</text>
<text x="54" y="200.5">5</text>
<text x="67.3" y="200.5">6</text>
<text x="80.5" y="200.5">7</text>
<text x="96.7" y="198.3">2.992</text>
<text x="101.5" y="200.3">0</text>
<text x="110" y="200.3">50</text>
<text x="118.6" y="200.3">100</text>
<text x="127.6" y="200.3">150</text>
<text x="136.4" y="200.3">200</text>
<text x="145.4" y="200.3">250</text>
<text x="154.4" y="200.3">300</text>
</g>
<g font-size="1.4" fill="#231f20">
<text x="21.9" y="77.9">2.85</text>
<text x="21.9" y="72.7">2.90</text>
<text x="21.9" y="83.2">2.80</text>
<text x="21.9" y="88.4">2.75</text>
<text x="21.9" y="93.6">2.70</text>
<text x="21.9" y="98.8">2.65</text>
<text x="24.4" y="100.8">-50</text>
<text x="33.8" y="100.8">-20</text>
<text x="43.3" y="100.8">10</text>
<text x="52.7" y="100.8">40</text>
<text x="61.8" y="100.8">70</text>
<text x="70.8" y="100.8">100</text>
<text x="80.2" y="100.8">130</text>
<text x="21.7" y="124.9">2.520</text>
<text x="21.7" y="122.4">2.525</text>
<text x="21.7" y="130.1">2.510</text>
<text x="21.7" y="127.6">2.515</text>
<text x="21.7" y="135.4">2.500</text>
<text x="21.7" y="132.8">2.505</text>
<text x="21.7" y="143.3">2.485</text>
<text x="21.7" y="140.6">2.490</text>
<text x="21.7" y="138">2.495</text>
<text x="21.7" y="148.5">2.475</text>
<text x="21.7" y="145.8">2.480</text>
<text x="25" y="150.5">-50</text>
<text x="34.3" y="150.5">-20</text>
<text x="43.7" y="150.5">10</text>
<text x="53.1" y="150.5">40</text>
<text x="62.2" y="150.5">70</text>
<text x="71.2" y="150.5">100</text>
<text x="80.4" y="150.5">130</text>
</g>
</g></defs>
<g fill="none" stroke="#231f20" stroke-width=".36">
<path d="M44 39.2l-2.5 1.3M47 38.1l-2.5 .9M53.1 36.3a6.7 6.7 0 0 0-3.2 .9l-2.3 .7M56.2 35.6l-2.5 .6M59.3 34.9l-2.6 .5M62.3 34.4l-2.5 .3M65.4 33.8l-2.5 .4M68.4 33.5l-2.5 .3M69 33.5h2.5M72 33.5h2.6M75.1 33.5h2.5M80.7 33.3l-2.5 .2"/>
<path d="M81.2 30.9l-3 .2a72 72 0 0 0-15.3 1.3l-9.2 2.1-3.6 1.1-.2 .2-1.4 .4a128.9 128.9 0 0 0-13.2 5.7l-1.6 .9a36.1 36.1 0 0 1-7.5 3.8M28.7 46.8l-2.5 1.2M31.6 45.1l-2.4 1.5M34.8 43.5l-2.5 1.3M37.7 42.1l-.9 .3-1.5 .9M40.9 40.6l-1.1 .4-1.4 .7M17.8 217.8h140.9"/>
</g>
<path d="M17.9 17.5h66.4v41h-66.4zM92.3 17.4h66.4v41.1h-66.4zM17.9 66h66.3v41h-66.3zM92.4 66.1h66.4v41h-66.4zM18 115h66.4v41h-66.4zM92.4 114.9h66.4v41.1h-66.4zM17.9 164.5h66.4v41h-66.4zM92.4 164.7h66.4v41h-66.4z" fill="none" stroke="#231f20" stroke-width=".17"/>
<g fill="none" stroke="#231f20" stroke-width=".16">
<path d="M25.9 37.7h.7M25.9 33.2h.7M25.9 28.9h.7M25.9 24.4h.7M26.2 24.4v26.8M26.2 39.8h.4M26.2 35.3h.4M26.2 31h.4M26.2 26.5h.4M27.3 37.7h.4M27.3 33.2h.4M27.3 28.9h.4"/>
<path d="M27.3 24.4h.4M28.4 37.7h.4M28.4 33.2h.4M28.4 28.9h.4M28.4 24.4h.4M29.5 37.7h.3M29.5 33.2h.3M29.5 28.9h.3M29.5 24.4h.3M30.6 37.7h.3M30.6 33.2h.3M30.6 28.9h.3"/>
<path d="M30.6 24.4h.3M31.6 37.7h.4M31.6 33.2h.4M31.6 28.9h.4M31.6 24.4h.4M32.7 37.7h.4M32.7 33.2h.4M32.7 28.9h.4M32.7 24.4h.4M33.8 37.7h.4M33.8 33.2h.4M33.8 28.9h.4"/>
<path d="M33.8 24.4h.4M34.9 37.7h.3M34.9 33.2h.3M34.9 28.9h.3M34.9 24.4h.3M36 37.7h.3M36 33.2h.3M36 28.9h.3M36 24.4h.3M37 37.7h.4M37 33.2h.4M37 28.9h.4"/>
<path d="M37 24.4h.4M38.1 37.7h.4M38.1 33.2h.4M38.1 28.9h.4M38.1 24.4h.4M39.2 37.7h.4M39.2 33.2h.4M39.2 28.9h.4M39.2 24.4h.4M40.3 37.7h.3M40.3 33.2h.3M40.3 28.9h.3"/>
<path d="M40.3 24.4h.3M41.4 37.7h.3M41.4 33.2h.3M41.4 28.9h.3M41.4 24.4h.3M42.4 37.7h.4M42.4 33.2h.4M42.4 28.9h.4M42.4 24.4h.4M43.5 37.7h.4M43.5 33.2h.4M43.5 28.9h.4"/>
<path d="M43.5 24.4h.4M44.6 37.7h.4M44.6 33.2h.4M44.6 28.9h.4M44.6 24.4h.4M45.7 37.7h.3M45.7 33.2h.3M45.7 28.9h.3M45.7 24.4h.3M46.8 37.7h.3M46.8 33.2h.3M46.8 28.9h.3"/>
<path d="M46.8 24.4h.3M47.8 37.7h.4M47.8 33.2h.4M47.8 28.9h.4M47.8 24.4h.4M48.9 37.7h.4M48.9 33.2h.4M48.9 28.9h.4M48.9 24.4h.4M50 37.7h.4M50 33.2h.4M50 28.9h.4"/>
<path d="M50 24.4h.4M51.1 37.7h.3M51.1 33.2h.3M51.1 28.9h.3M51.1 24.4h.3M52.2 37.7h.3M52.2 33.2h.3M52.2 28.9h.3M52.2 24.4h.3M53.2 37.7h.4M53.2 33.2h.4M53.2 28.9h.4"/>
<path d="M53.2 24.4h.4M54.3 37.7h.4M54.3 33.2h.4M54.3 28.9h.4M54.3 24.4h.4M55.4 37.7h.4M55.4 33.2h.4M55.4 28.9h.4M55.4 24.4h.4M56.5 37.7h.3M56.5 33.2h.3M56.5 28.9h.3"/>
<path d="M56.5 24.4h.3M57.6 37.7h.3M57.6 33.2h.3M57.6 28.9h.3M57.6 24.4h.3M58.6 37.7h.4M58.6 33.2h.4M58.6 28.9h.4M58.6 24.4h.4M59.7 37.7h.4M59.7 33.2h.4M59.7 28.9h.4"/>
<path d="M59.7 24.4h.4M60.8 37.7h.4M60.8 33.2h.4M60.8 28.9h.4M60.8 24.4h.4M61.9 37.7h.3M61.9 33.2h.3M61.9 28.9h.3M61.9 24.4h.3M63 37.7h.3M63 33.2h.3M63 28.9h.3"/>
<path d="M63 24.4h.3M64 37.7h.4M64 33.2h.4M64 28.9h.4M64 24.4h.4M65.1 37.7h.4M65.1 33.2h.4M65.1 28.9h.4M65.1 24.4h.4M66.2 37.7h.4M66.2 33.2h.4M66.2 28.9h.4"/>
<path d="M66.2 24.4h.4M67.3 37.7h.3M67.3 33.2h.3M67.3 28.9h.3M67.3 24.4h.3M68.4 37.7h.3M68.4 33.2h.3M68.4 28.9h.3M68.4 24.4h.3M69.4 37.7h.4M69.4 33.2h.4M69.4 28.9h.4"/>
<path d="M69.4 24.4h.4M70.5 37.7h.4M70.5 33.2h.4M70.5 28.9h.4M70.5 24.4h.4M71.6 37.7h.4M71.6 33.2h.4M71.6 28.9h.4M71.6 24.4h.4M72.7 37.7h.3M72.7 33.2h.3M72.7 28.9h.3"/>
<path d="M72.7 24.4h.3M73.8 37.7h.3M73.8 33.2h.3M73.8 28.9h.3M73.8 24.4h.3M74.8 37.7h.4M74.8 33.2h.4M74.8 28.9h.4M74.8 24.4h.4M75.9 37.7h.4M75.9 33.2h.4M75.9 28.9h.4"/>
<path d="M75.9 24.4h.4M77 37.7h.4M77 33.2h.4M77 28.9h.4M77 24.4h.4M78.1 37.7h.3M78.1 33.2h.3M78.1 28.9h.3M78.1 24.4h.3M79.2 37.7h.3M79.2 33.2h.3M79.2 28.9h.3"/>
<path d="M79.2 24.4h.3M80.2 37.7h.4M80.2 33.2h.4M80.2 28.9h.4M80.2 24.4h.4M25.9 46.5h.7M25.9 42h.7M25.9 50.8h55.4M26.2 48.7h.4M26.2 44.2h.4M27.3 46.5h.4M27.3 42h.4"/>
<path d="M28.4 46.5h.4M28.4 42h.4M29.5 46.5h.3M29.5 42h.3M30.6 46.5h.3M30.6 42h.3M30.9 50.5v.3M31.6 46.5h.4M31.6 42h.4M32.7 46.5h.4M32.7 42h.4M33.8 46.5h.4"/>
<path d="M33.8 42h.4M34.9 46.5h.3M34.9 42h.3M35.4 50.5v.7M36 46.5h.3M36 42h.3M37 46.5h.4M37 42h.4M38.1 46.5h.4M38.1 42h.4M39.2 46.5h.4M39.2 42h.4"/>
<path d="M40.1 50.5v.3M40.3 46.5h.3M40.3 42h.3M41.4 46.5h.3M41.4 42h.3M42.4 46.5h.4M42.4 42h.4M43.5 46.5h.4M43.5 42h.4M44.6 46.5h.4M44.6 42h.4M44.6 50.5v.7"/>
<path d="M45.7 46.5h.3M45.7 42h.3M46.8 46.5h.3M46.8 42h.3M47.8 46.5h.4M47.8 42h.4M48.9 46.5h.4M48.9 42h.4M49.3 50.5v.3M50 46.5h.4M50 42h.4M51.1 46.5h.3"/>
<path d="M51.1 42h.3M52.2 46.5h.3M52.2 42h.3M53.2 46.5h.4M53.2 42h.4M53.8 50.5v.7M54.3 46.5h.4M54.3 42h.4M55.4 46.5h.4M55.4 42h.4M56.5 46.5h.3M56.5 42h.3"/>
<path d="M57.6 46.5h.3M57.6 42h.3M58.5 50.5v.3M58.6 46.5h.4M58.6 42h.4M59.7 46.5h.4M59.7 42h.4M60.8 46.5h.4M60.8 42h.4M61.9 46.5h.3M61.9 42h.3M63 46.5h.3"/>
<path d="M63 42h.3M63 50.5v.7M64 46.5h.4M64 42h.4M65.1 46.5h.4M65.1 42h.4M66.2 46.5h.4M66.2 42h.4M67.3 46.5h.3M67.3 42h.3M67.6 50.5v.3M68.4 46.5h.3"/>
<path d="M68.4 42h.3M69.4 46.5h.4M69.4 42h.4M70.5 46.5h.4M70.5 42h.4M71.6 46.5h.4M71.6 42h.4M72.1 50.5v.7M72.7 46.5h.3M72.7 42h.3M73.8 46.5h.3M73.8 42h.3"/>
<path d="M74.8 46.5h.4M74.8 42h.4M75.9 46.5h.4M75.9 42h.4M76.8 50.5v.3M77 46.5h.4M77 42h.4M78.1 46.5h.3M78.1 42h.3M79.2 46.5h.3M79.2 42h.3M80.2 46.5h.4"/>
<path d="M80.2 42h.4M81.3 50.5v.7"/>
</g>
<path d="M26.2 24.4h55.1v26.4" fill="none" stroke="#231f20" stroke-width=".18"/>
<path d="M26.2 24.4v26.4h55.1" fill="none" stroke="#949698" stroke-width=".18"/>
<path d="M31.3 26.7h14.7v5.8h-14.7z" fill="#fff" stroke="#231f20" stroke-width=".16"/>
<g fill="none" stroke="#231f20" stroke-width=".36">
<path d="M32.5 28.2h6.3M32.5 30.9h2.5M36.4 30.9h2.4M112.6 39.4l-2.1 1.5M115.5 37.6l-2.1 1.3M118.9 35.3l-2.1 1.4M122 34l-2.5 1.1M128.1 31.7l-3 .9-.6 .5-1.1 .6M134.4 30.1l-4.8 1.1M140.5 29.4l-4.7 .3M142 29.4h2.1l2.5 .3M148.1 29.9l4.8 .7"/>
<path d="M154.4 31.2l2.1 .7M156.5 27.2l-1.4-.7-1.6-.4h-1.5a41.1 41.1 0 0 0-14 .6 104.4 104.4 0 0 0-11.1 3 5.9 5.9 0 0 0-2.7 1.1l-3.5 1.5a89.5 89.5 0 0 0-13.6 8.6l-6.2 5.2M102.9 45.9l-2 1.6M106.3 43.6l-2.1 1.4M109.2 41.6l-2.1 1.4"/>
</g>
<g fill="none" stroke="#231f20" stroke-width=".16">
<path d="M100.7 37.6h.7M100.7 33.1h.7M100.7 28.7h.7M100.7 24.2h.7M101 24.2v27M101 39.7h.4M101 35.4h.4M101 30.9h.4M101 26.4h.4M102.1 37.6h.4M102.1 33.1h.4M102.1 28.7h.4"/>
<path d="M102.1 24.2h.4M103.2 37.6h.3M103.2 33.1h.3M103.2 28.7h.3M103.2 24.2h.3M104.3 37.6h.3M104.3 33.1h.3M104.3 28.7h.3M104.3 24.2h.3M105.3 37.6h.4M105.3 33.1h.4M105.3 28.7h.4"/>
<path d="M105.3 24.2h.4M106.4 37.6h.4M106.4 33.1h.4M106.4 28.7h.4M106.4 24.2h.4M107.5 37.6h.4M107.5 33.1h.4M107.5 28.7h.4M107.5 24.2h.4M108.6 37.6h.3M108.6 33.1h.3M108.6 28.7h.3"/>
<path d="M108.6 24.2h.3M109.7 37.6h.3M109.7 33.1h.3M109.7 28.7h.3M109.7 24.2h.3M110.7 37.6h.4M110.7 33.1h.4M110.7 28.7h.4M110.7 24.2h.4M111.8 37.6h.4M111.8 33.1h.4M111.8 28.7h.4"/>
<path d="M111.8 24.2h.4M112.9 37.6h.4M112.9 33.1h.4M112.9 28.7h.4M112.9 24.2h.4M114 37.6h.3M114 33.1h.3M114 28.7h.3M114 24.2h.3M115.1 37.6h.3M115.1 33.1h.3M115.1 28.7h.3"/>
<path d="M115.1 24.2h.3M116.1 37.6h.4M116.1 33.1h.4M116.1 28.7h.4M116.1 24.2h.4M117.2 37.6h.4M117.2 33.1h.4M117.2 28.7h.4M117.2 24.2h.4M118.3 37.6h.4M118.3 33.1h.4M118.3 28.7h.4"/>
<path d="M118.3 24.2h.4M119.4 37.6h.3M119.4 33.1h.3M119.4 28.7h.3M119.4 24.2h.3M120.5 37.6h.3M120.5 33.1h.3M120.5 28.7h.3M120.5 24.2h.3M121.5 37.6h.4M121.5 33.1h.4M121.5 28.7h.4"/>
<path d="M121.5 24.2h.4M122.6 37.6h.4M122.6 33.1h.4M122.6 28.7h.4M122.6 24.2h.4M123.7 37.6h.4M123.7 33.1h.4M123.7 28.7h.4M123.7 24.2h.4M124.8 37.6h.3M124.8 33.1h.3M124.8 28.7h.3"/>
<path d="M124.8 24.2h.3M125.9 37.6h.3M125.9 33.1h.3M125.9 28.7h.3M125.9 24.2h.3M126.9 37.6h.4M126.9 33.1h.4M126.9 28.7h.4M126.9 24.2h.4M128 37.6h.4M128 33.1h.4M128 28.7h.4"/>
<path d="M128 24.2h.4M129.1 37.6h.4M129.1 33.1h.4M129.1 28.7h.4M129.1 24.2h.4M130.2 37.6h.3M130.2 33.1h.3M130.2 28.7h.3M130.2 24.2h.3M131.3 37.6h.3M131.3 33.1h.3M131.3 28.7h.3"/>
<path d="M131.3 24.2h.3M132.3 37.6h.4M132.3 33.1h.4M132.3 28.7h.4M132.3 24.2h.4M133.4 37.6h.4M133.4 33.1h.4M133.4 28.7h.4M133.4 24.2h.4M134.5 37.6h.4M134.5 33.1h.4M134.5 28.7h.4"/>
<path d="M134.5 24.2h.4M135.6 37.6h.3M135.6 33.1h.3M135.6 28.7h.3M135.6 24.2h.3M136.7 37.6h.3M136.7 33.1h.3M136.7 28.7h.3M136.7 24.2h.3M137.7 37.6h.4M137.7 33.1h.4M137.7 28.7h.4"/>
<path d="M137.7 24.2h.4M138.8 37.6h.4M138.8 33.1h.4M138.8 28.7h.4M138.8 24.2h.4M139.9 37.6h.4M139.9 33.1h.4M139.9 28.7h.4M139.9 24.2h.4M141 37.6h.3M141 33.1h.3M141 28.7h.3"/>
<path d="M141 24.2h.3M142.1 37.6h.3M142.1 33.1h.3M142.1 28.7h.3M142.1 24.2h.3M143.1 37.6h.4M143.1 33.1h.4M143.1 28.7h.4M143.1 24.2h.4M144.2 37.6h.4M144.2 33.1h.4M144.2 28.7h.4"/>
<path d="M144.2 24.2h.4M145.3 37.6h.4M145.3 33.1h.4M145.3 28.7h.4M145.3 24.2h.4M146.4 37.6h.3M146.4 33.1h.3M146.4 28.7h.3M146.4 24.2h.3M147.5 37.6h.3M147.5 33.1h.3M147.5 28.7h.3"/>
<path d="M147.5 24.2h.3M148.5 37.6h.4M148.5 33.1h.4M148.5 28.7h.4M148.5 24.2h.4M149.6 37.6h.4M149.6 33.1h.4M149.6 28.7h.4M149.6 24.2h.4M150.7 37.6h.4M150.7 33.1h.4M150.7 28.7h.4"/>
<path d="M150.7 24.2h.4M151.8 37.6h.3M151.8 33.1h.3M151.8 28.7h.3M151.8 24.2h.3M152.9 37.6h.3M152.9 33.1h.3M152.9 28.7h.3M152.9 24.2h.3M153.9 37.6h.4M153.9 33.1h.4M153.9 28.7h.4"/>
<path d="M153.9 24.2h.4M155 37.6h.4M155 33.1h.4M155 28.7h.4M155 24.2h.4M156.1 37.6h.4M156.1 33.1h.4M156.1 28.7h.4M156.1 24.2h.4M100.7 46.4h.7M100.7 42.1h.7M100.7 50.9h55.9"/>
<path d="M101 48.7h.4M101 44.2h.4M102.1 46.4h.4M102.1 42.1h.4M103.2 46.4h.3M103.2 42.1h.3M104.3 46.4h.3M104.3 42.1h.3M105.3 46.4h.4M105.3 42.1h.4M105.7 50.5v.4M106.4 46.4h.4"/>
<path d="M106.4 42.1h.4M107.5 46.4h.4M107.5 42.1h.4M108.6 46.4h.3M108.6 42.1h.3M109.7 46.4h.3M109.7 42.1h.3M110.4 50.5v.7M110.7 46.4h.4M110.7 42.1h.4M111.8 46.4h.4M111.8 42.1h.4"/>
<path d="M112.9 46.4h.4M112.9 42.1h.4M114 46.4h.3M114 42.1h.3M114.9 50.5v.4M115.1 46.4h.3M115.1 42.1h.3M116.1 46.4h.4M116.1 42.1h.4M117.2 46.4h.4M117.2 42.1h.4M118.3 46.4h.4"/>
<path d="M118.3 42.1h.4M119.4 46.4h.3M119.4 42.1h.3M119.6 50.5v.7M120.5 46.4h.3M120.5 42.1h.3M121.5 46.4h.4M121.5 42.1h.4M122.6 46.4h.4M122.6 42.1h.4M123.7 46.4h.4M123.7 42.1h.4"/>
<path d="M124.2 50.5v.4M124.8 46.4h.3M124.8 42.1h.3M125.9 46.4h.3M125.9 42.1h.3M126.9 46.4h.4M126.9 42.1h.4M128 46.4h.4M128 42.1h.4M128.9 50.5v.7M129.1 46.4h.4M129.1 42.1h.4"/>
<path d="M130.2 46.4h.3M130.2 42.1h.3M131.3 46.4h.3M131.3 42.1h.3M132.3 46.4h.4M132.3 42.1h.4M133.4 46.4h.4M133.4 42.1h.4M133.4 50.5v.4M134.5 46.4h.4M134.5 42.1h.4M135.6 46.4h.3"/>
<path d="M135.6 42.1h.3M136.7 46.4h.3M136.7 42.1h.3M137.7 46.4h.4M137.7 42.1h.4M138.1 50.5v.7M138.8 46.4h.4M138.8 42.1h.4M139.9 46.4h.4M139.9 42.1h.4M141 46.4h.3M141 42.1h.3"/>
<path d="M142.1 46.4h.3M142.1 42.1h.3M142.8 50.5v.4M143.1 46.4h.4M143.1 42.1h.4M144.2 46.4h.4M144.2 42.1h.4M145.3 46.4h.4M145.3 42.1h.4M146.4 46.4h.3M146.4 42.1h.3M147.5 46.4h.3"/>
<path d="M147.5 42.1h.3M147.5 50.5v.7M148.5 46.4h.4M148.5 42.1h.4M149.6 46.4h.4M149.6 42.1h.4M150.7 46.4h.4M150.7 42.1h.4M151.8 46.4h.3M151.8 42.1h.3M152 50.5v.4M152.9 46.4h.3"/>
<path d="M152.9 42.1h.3M153.9 46.4h.4M153.9 42.1h.4M155 46.4h.4M155 42.1h.4M156.1 46.4h.4M156.1 42.1h.4M156.6 50.5v.7"/>
</g>
<path d="M101 24.2h55.6v26.7h-55.6z" fill="none" stroke="#949698" stroke-width=".18"/>
<path d="M104.4 25.7h15.3v5.7h-15.3z" fill="#fff" stroke="#231f20" stroke-width=".16"/>
<g fill="none" stroke="#231f20" stroke-width=".36">
<path d="M105.8 27.6h6.3M105.8 30.3h2.5M109.8 30.3h2.3M25.3 77.2l3.2-.2h6.2l3 .2h3.3l1.6 .2h2.9l1.2 .2h4.7l1.6 .2h1.8l17.1 1.4 3.1 .4 6.3 1M25.3 93.2h2.5M34.1 93.1l-2.5 .1h-2.3M35.6 93.1h4.6M41.7 93.1l.9 .1h3.9M48 93.2h3.4l1.3 .2M54.1 93.6h4.9M60.4 93.6l4.7 .4M66.5 94.1l4.9 .4"/>
<path d="M72.8 94.5l4.7 .5M78.9 95.4l2.4 .5"/>
</g>
<g fill="none" stroke="#231f20" stroke-width=".16">
<path d="M25 77.7h.8M25 72.4h.8M25.4 72.4v26.5M25.4 75.1h.2M26.5 77.7h.3M26.5 72.4h.3M27.6 77.7h.3M27.6 72.4h.3M28.6 77.7h.4M28.6 72.4h.4M29.7 77.7h.4M29.7 72.4h.4"/>
<path d="M30.8 77.7h.3M30.8 72.4h.3M31.9 77.7h.3M31.9 72.4h.3M32.9 77.7h.4M32.9 72.4h.4M34 77.7h.4M34 72.4h.4M35.1 77.7h.4M35.1 72.4h.4M36.2 77.7h.3M36.2 72.4h.3"/>
<path d="M37.3 77.7h.3M37.3 72.4h.3M38.3 77.7h.4M38.3 72.4h.4M39.4 77.7h.4M39.4 72.4h.4M40.5 77.7h.4M40.5 72.4h.4M41.6 77.7h.3M41.6 72.4h.3M42.7 77.7h.3M42.7 72.4h.3"/>
<path d="M43.7 77.7h.4M43.7 72.4h.4M44.8 77.7h.4M44.8 72.4h.4M45.9 77.7h.4M45.9 72.4h.4M47 77.7h.3M47 72.4h.3M48.1 77.7h.3M48.1 72.4h.3M49.1 77.7h.4M49.1 72.4h.4"/>
<path d="M50.2 77.7h.4M50.2 72.4h.4M51.3 77.7h.4M51.3 72.4h.4M52.4 77.7h.3M52.4 72.4h.3M53.5 77.7h.3M53.5 72.4h.3M54.5 77.7h.4M54.5 72.4h.4M55.6 77.7h.4M55.6 72.4h.4"/>
<path d="M56.7 77.7h.4M56.7 72.4h.4M57.8 77.7h.3M57.8 72.4h.3M58.9 77.7h.3M58.9 72.4h.3M59.9 77.7h.4M59.9 72.4h.4M61 77.7h.4M61 72.4h.4M62.1 77.7h.4M62.1 72.4h.4"/>
<path d="M63.2 77.7h.3M63.2 72.4h.3M64.3 77.7h.3M64.3 72.4h.3M65.3 77.7h.4M65.3 72.4h.4M66.4 77.7h.4M66.4 72.4h.4M67.5 77.7h.4M67.5 72.4h.4M68.6 77.7h.3M68.6 72.4h.3"/>
<path d="M69.7 77.7h.3M69.7 72.4h.3M70.7 77.7h.4M70.7 72.4h.4M71.8 77.7h.4M71.8 72.4h.4M72.9 77.7h.4M72.9 72.4h.4M74 77.7h.3M74 72.4h.3M75.1 77.7h.3M75.1 72.4h.3"/>
<path d="M76.1 77.7h.4M76.1 72.4h.4M77.2 77.7h.4M77.2 72.4h.4M78.3 77.7h.4M78.3 72.4h.4M79.4 77.7h.3M79.4 72.4h.3M80.5 77.7h.3M80.5 72.4h.3M25 93.3h.8M25 88.1h.8"/>
<path d="M25 82.9h.8M25 98.5h56.4M25.4 96h.2M25.4 90.8h.2M25.4 85.6h.2M25.4 80.4h.2M26.5 93.3h.3M26.5 88.1h.3M26.5 82.9h.3M27.6 93.3h.3M27.6 88.1h.3M27.6 82.9h.3"/>
<path d="M28.6 93.3h.4M28.6 88.1h.4M28.6 82.9h.4M29.7 93.3h.4M29.7 88.1h.4M29.7 82.9h.4M30.1 98.4v.1M30.8 93.3h.3M30.8 88.1h.3M30.8 82.9h.3M31.9 93.3h.3M31.9 88.1h.3"/>
<path d="M31.9 82.9h.3M32.9 93.3h.4M32.9 88.1h.4M32.9 82.9h.4M34 93.3h.4M34 88.1h.4M34 82.9h.4M34.7 98.4v.5M35.1 93.3h.4M35.1 88.1h.4M35.1 82.9h.4M36.2 93.3h.3"/>
<path d="M36.2 88.1h.3M36.2 82.9h.3M37.3 93.3h.3M37.3 88.1h.3M37.3 82.9h.3M38.3 93.3h.4M38.3 88.1h.4M38.3 82.9h.4M39.4 93.3h.4M39.4 88.1h.4M39.4 82.9h.4M39.4 98.4v.1"/>
<path d="M40.5 93.3h.4M40.5 88.1h.4M40.5 82.9h.4M41.6 93.3h.3M41.6 88.1h.3M41.6 82.9h.3M42.7 93.3h.3M42.7 88.1h.3M42.7 82.9h.3M43.7 93.3h.4M43.7 88.1h.4M43.7 82.9h.4"/>
<path d="M44.1 98.4v.5M44.8 93.3h.4M44.8 88.1h.4M44.8 82.9h.4M45.9 93.3h.4M45.9 88.1h.4M45.9 82.9h.4M47 93.3h.3M47 88.1h.3M47 82.9h.3M48.1 93.3h.3M48.1 88.1h.3"/>
<path d="M48.1 82.9h.3M48.8 98.4v.1M49.1 93.3h.4M49.1 88.1h.4M49.1 82.9h.4M50.2 93.3h.4M50.2 88.1h.4M50.2 82.9h.4M51.3 93.3h.4M51.3 88.1h.4M51.3 82.9h.4M52.4 93.3h.3"/>
<path d="M52.4 88.1h.3M52.4 82.9h.3M53.3 98.4v.1M53.5 93.3h.3M53.5 88.1h.3M53.5 82.9h.3M53.5 98.5v.4M54.5 93.3h.4M54.5 88.1h.4M54.5 82.9h.4M55.6 93.3h.4M55.6 88.1h.4"/>
<path d="M55.6 82.9h.4M56.7 93.3h.4M56.7 88.1h.4M56.7 82.9h.4M57.8 93.3h.3M57.8 88.1h.3M57.8 82.9h.3M58 98.4v.1M58.9 93.3h.3M58.9 88.1h.3M58.9 82.9h.3M59.9 93.3h.4"/>
<path d="M59.9 88.1h.4M59.9 82.9h.4M61 93.3h.4M61 88.1h.4M61 82.9h.4M62.1 93.3h.4M62.1 88.1h.4M62.1 82.9h.4M62.6 98.4v.5M63.2 93.3h.3M63.2 88.1h.3M63.2 82.9h.3"/>
<path d="M64.3 93.3h.3M64.3 88.1h.3M64.3 82.9h.3M65.3 93.3h.4M65.3 88.1h.4M65.3 82.9h.4M66.4 93.3h.4M66.4 88.1h.4M66.4 82.9h.4M67.3 98.4v.1M67.5 93.3h.4M67.5 88.1h.4"/>
<path d="M67.5 82.9h.4M68.6 93.3h.3M68.6 88.1h.3M68.6 82.9h.3M69.7 93.3h.3M69.7 88.1h.3M69.7 82.9h.3M70.7 93.3h.4M70.7 88.1h.4M70.7 82.9h.4M71.8 93.3h.4M71.8 88.1h.4"/>
<path d="M71.8 82.9h.4M72 98.4v.5M72.9 93.3h.4M72.9 88.1h.4M72.9 82.9h.4M74 93.3h.3M74 88.1h.3M74 82.9h.3M75.1 93.3h.3M75.1 88.1h.3M75.1 82.9h.3M76.1 93.3h.4"/>
<path d="M76.1 88.1h.4M76.1 82.9h.4M76.7 98.4v.1M77.2 93.3h.4M77.2 88.1h.4M77.2 82.9h.4M78.3 93.3h.4M78.3 88.1h.4M78.3 82.9h.4M79.4 93.3h.3M79.4 88.1h.3M79.4 82.9h.3"/>
<path d="M80.5 93.3h.3M80.5 88.1h.3M80.5 82.9h.3M81.4 98.4v.5"/>
</g>
<path d="M25.4 72.4h56v26.1" fill="none" stroke="#231f20" stroke-width=".18"/>
<path d="M25.4 72.4v26.1h56" fill="none" stroke="#949698" stroke-width=".18"/>
<path d="M30.7 81.6h14.5v5.5h-14.5z" fill="#fff" stroke="#231f20" stroke-width=".16"/>
<g fill="none" stroke="#231f20" stroke-width=".36">
<path d="M100.9 76.1l6.1-.2h14.8l1.1 .2h5l1.8 .2a232.8 232.8 0 0 1 25.9 1.6M31.4 83.2h6.3M31.4 85.7h2.5M35.4 85.7h2.3M100.9 95.3h2.5M109.6 95.2l-2.6 .1h-2.1M111 95.2h4.7M117.1 95.2h4.5M123 95.2h4.7M129.2 95.3h4.6M135.3 95.5h4.7M141.4 95.7l4.5 .2"/>
<path d="M147.3 95.9l4.7 .3M153.5 96.4l2.1 .2"/>
</g>
<g fill="none" stroke="#231f20" stroke-width=".16">
<path d="M100.6 79.2h.8M100.6 72.9h.8M101 72.9v25.9M101 76.2h.4M102.1 79.2h.3M102.1 72.9h.3M103.2 79.2h.3M103.2 72.9h.3M104.2 79.2h.4M104.2 72.9h.4M105.3 79.2h.4M105.3 72.9h.4"/>
<path d="M106.4 79.2h.4M106.4 72.9h.4M107.5 79.2h.3M107.5 72.9h.3M108.6 79.2h.3M108.6 72.9h.3M109.6 79.2h.4M109.6 72.9h.4M110.7 79.2h.4M110.7 72.9h.4M111.8 79.2h.4M111.8 72.9h.4"/>
<path d="M112.9 79.2h.3M112.9 72.9h.3M114 79.2h.3M114 72.9h.3M115 79.2h.4M115 72.9h.4M116.1 79.2h.4M116.1 72.9h.4M117.2 79.2h.4M117.2 72.9h.4M118.3 79.2h.3M118.3 72.9h.3"/>
<path d="M119.4 79.2h.3M119.4 72.9h.3M120.4 79.2h.4M120.4 72.9h.4M121.5 79.2h.4M121.5 72.9h.4M122.6 79.2h.4M122.6 72.9h.4M123.7 79.2h.3M123.7 72.9h.3M124.8 79.2h.3M124.8 72.9h.3"/>
<path d="M125.8 79.2h.4M125.8 72.9h.4M126.9 79.2h.4M126.9 72.9h.4M128 79.2h.4M128 72.9h.4M129.1 79.2h.3M129.1 72.9h.3M130.2 79.2h.3M130.2 72.9h.3M131.2 79.2h.4M131.2 72.9h.4"/>
<path d="M132.3 79.2h.4M132.3 72.9h.4M133.4 79.2h.4M133.4 72.9h.4M134.5 79.2h.3M134.5 72.9h.3M135.5 79.2h.4M135.5 72.9h.4M136.6 79.2h.4M136.6 72.9h.4M137.7 79.2h.4M137.7 72.9h.4"/>
<path d="M138.8 79.2h.3M138.8 72.9h.3M139.9 79.2h.3M139.9 72.9h.3M140.9 79.2h.4M140.9 72.9h.4M142 79.2h.4M142 72.9h.4M143.1 79.2h.4M143.1 72.9h.4M144.2 79.2h.3M144.2 72.9h.3"/>
<path d="M145.3 79.2h.3M145.3 72.9h.3M146.3 79.2h.4M146.3 72.9h.4M147.4 79.2h.4M147.4 72.9h.4M148.5 79.2h.4M148.5 72.9h.4M149.6 79.2h.3M149.6 72.9h.3M150.7 79.2h.3M150.7 72.9h.3"/>
<path d="M151.7 79.2h.4M151.7 72.9h.4M152.8 79.2h.4M152.8 72.9h.4M153.9 79.2h.4M153.9 72.9h.4M155 79.2h.3M155 72.9h.3M100.6 92h.8M100.6 85.7h.8M100.6 98.5h55.1M101 95.2h.4"/>
<path d="M101 88.9h.4M101 82.5h.4M102.1 92h.3M102.1 85.7h.3M103.2 92h.3M103.2 85.7h.3M104.2 92h.4M104.2 85.7h.4M105.3 92h.4M105.3 85.7h.4M105.5 98.1v.4M106.4 92h.4"/>
<path d="M106.4 85.7h.4M107.5 92h.3M107.5 85.7h.3M108.6 92h.3M108.6 85.7h.3M109.6 92h.4M109.6 85.7h.4M110.2 98.1v.7M110.7 92h.4M110.7 85.7h.4M111.8 92h.4M111.8 85.7h.4"/>
<path d="M112.9 92h.3M112.9 85.7h.3M114 92h.3M114 85.7h.3M114.7 98.1v.4M115 92h.4M115 85.7h.4M116.1 92h.4M116.1 85.7h.4M117.2 92h.4M117.2 85.7h.4M118.3 92h.3"/>
<path d="M118.3 85.7h.3M119.2 98.1v.7M119.4 92h.3M119.4 85.7h.3M120.4 92h.4M120.4 85.7h.4M121.5 92h.4M121.5 85.7h.4M122.6 92h.4M122.6 85.7h.4M123.7 92h.3M123.7 85.7h.3"/>
<path d="M123.9 98.1v.4M124.8 92h.3M124.8 85.7h.3M125.8 92h.4M125.8 85.7h.4M126.9 92h.4M126.9 85.7h.4M128 92h.4M128 85.7h.4M128.4 98.1v.7M129.1 92h.3M129.1 85.7h.3"/>
<path d="M130.2 92h.3M130.2 85.7h.3M131.2 92h.4M131.2 85.7h.4M132.3 92h.4M132.3 85.7h.4M132.9 98.1v.4M133.4 92h.4M133.4 85.7h.4M134.5 92h.3M134.5 85.7h.3M135.5 92h.4"/>
<path d="M135.5 85.7h.4M136.6 92h.4M136.6 85.7h.4M137.5 98.1v.7M137.7 92h.4M137.7 85.7h.4M138.8 92h.3M138.8 85.7h.3M139.9 92h.3M139.9 85.7h.3M140.9 92h.4M140.9 85.7h.4"/>
<path d="M142 92h.4M142 85.7h.4M142 98.1v.4M143.1 92h.4M143.1 85.7h.4M144.2 92h.3M144.2 85.7h.3M145.3 92h.3M145.3 85.7h.3M146.3 92h.4M146.3 85.7h.4M146.5 98.1v.7"/>
<path d="M147.4 92h.4M147.4 85.7h.4M148.5 92h.4M148.5 85.7h.4M149.6 92h.3M149.6 85.7h.3M150.7 92h.3M150.7 85.7h.3M151.2 98.1v.4M151.7 92h.4M151.7 85.7h.4M152.8 92h.4"/>
<path d="M152.8 85.7h.4M153.9 92h.4M153.9 85.7h.4M155 92h.3M155 85.7h.3M155.7 98.1v.7"/>
</g>
<path d="M101 72.9h54.7v25.6" fill="none" stroke="#231f20" stroke-width=".18"/>
<path d="M101 72.9v25.6h54.7" fill="none" stroke="#949698" stroke-width=".18"/>
<path d="M104.4 79.8h14v5.6h-14z" fill="#fff" stroke="#231f20" stroke-width=".16"/>
<path d="M105.1 81h6.3M105.1 84h2.5M109 84h2.4M43 134.6h-9.4a36.9 36.9 0 0 0-7.7 1.8M45.7 134.8h1.4l2 .4h2M55.2 135.7a105.9 105.9 0 0 1 16.9 4.3l1.6 .4M77 142l4.5 3.1" fill="none" stroke="#231f20" stroke-width=".36"/>
<g fill="none" stroke="#231f20" stroke-width=".16">
<path d="M25.6 137.8h.7M25.6 135.1h.7M25.6 132.6h.7M25.6 129.9h.7M25.6 127.3h.7M25.6 124.7h.7M25.6 122.1h.7M26 122.1v26.5M26 139h.2M26 136.5h.2M26 133.8h.2M26 131.3h.2"/>
<path d="M26 128.6h.2M26 126.1h.2M26 123.4h.2M27.1 137.8h.3M27.1 135.1h.3M27.1 132.6h.3M27.1 129.9h.3M27.1 127.3h.3M27.1 124.7h.3M27.1 122.1h.3M28.1 137.8h.4M28.1 135.1h.4"/>
<path d="M28.1 132.6h.4M28.1 129.9h.4M28.1 127.3h.4M28.1 124.7h.4M28.1 122.1h.4M29.2 137.8h.4M29.2 135.1h.4M29.2 132.6h.4M29.2 129.9h.4M29.2 127.3h.4M29.2 124.7h.4M29.2 122.1h.4"/>
<path d="M30.3 137.8h.4M30.3 135.1h.4M30.3 132.6h.4M30.3 129.9h.4M30.3 127.3h.4M30.3 124.7h.4M30.3 122.1h.4M31.4 137.8h.3M31.4 135.1h.3M31.4 132.6h.3M31.4 129.9h.3M31.4 127.3h.3"/>
<path d="M31.4 124.7h.3M31.4 122.1h.3M32.5 137.8h.3M32.5 135.1h.3M32.5 132.6h.3M32.5 129.9h.3M32.5 127.3h.3M32.5 124.7h.3M32.5 122.1h.3M33.5 137.8h.4M33.5 135.1h.4M33.5 132.6h.4"/>
<path d="M33.5 129.9h.4M33.5 127.3h.4M33.5 124.7h.4M33.5 122.1h.4M34.6 137.8h.4M34.6 135.1h.4M34.6 132.6h.4M34.6 129.9h.4M34.6 127.3h.4M34.6 124.7h.4M34.6 122.1h.4M35.7 137.8h.4"/>
<path d="M35.7 135.1h.4M35.7 132.6h.4M35.7 129.9h.4M35.7 127.3h.4M35.7 124.7h.4M35.7 122.1h.4M36.8 137.8h.3M36.8 135.1h.3M36.8 132.6h.3M36.8 129.9h.3M36.8 127.3h.3M36.8 124.7h.3"/>
<path d="M36.8 122.1h.3M37.8 137.8h.4M37.8 135.1h.4M37.8 132.6h.4M37.8 129.9h.4M37.8 127.3h.4M37.8 124.7h.4M37.8 122.1h.4M38.9 137.8h.4M38.9 135.1h.4M38.9 132.6h.4M38.9 129.9h.4"/>
<path d="M38.9 127.3h.4M38.9 124.7h.4M38.9 122.1h.4M40 137.8h.4M40 135.1h.4M40 132.6h.4M40 129.9h.4M40 127.3h.4M40 124.7h.4M40 122.1h.4M41.1 137.8h.3M41.1 135.1h.3"/>
<path d="M41.1 132.6h.3M41.1 129.9h.3M41.1 127.3h.3M41.1 124.7h.3M41.1 122.1h.3M42.2 137.8h.3M42.2 135.1h.3M42.2 132.6h.3M42.2 129.9h.3M42.2 127.3h.3M42.2 124.7h.3M42.2 122.1h.3"/>
<path d="M43.2 137.8h.4M43.2 135.1h.4M43.2 132.6h.4M43.2 129.9h.4M43.2 127.3h.4M43.2 124.7h.4M43.2 122.1h.4M44.3 137.8h.4M44.3 135.1h.4M44.3 132.6h.4M44.3 129.9h.4M44.3 127.3h.4"/>
<path d="M44.3 124.7h.4M44.3 122.1h.4M45.4 137.8h.4M45.4 135.1h.4M45.4 132.6h.4M45.4 129.9h.4M45.4 127.3h.4M45.4 124.7h.4M45.4 122.1h.4M46.5 137.8h.3M46.5 135.1h.3M46.5 132.6h.3"/>
<path d="M46.5 129.9h.3M46.5 127.3h.3M46.5 124.7h.3M46.5 122.1h.3M47.6 137.8h.3M47.6 135.1h.3M47.6 132.6h.3M47.6 129.9h.3M47.6 127.3h.3M47.6 124.7h.3M47.6 122.1h.3M48.6 137.8h.4"/>
<path d="M48.6 135.1h.4M48.6 132.6h.4M48.6 129.9h.4M48.6 127.3h.4M48.6 124.7h.4M48.6 122.1h.4M49.7 137.8h.4M49.7 135.1h.4M49.7 132.6h.4M49.7 129.9h.4M49.7 127.3h.4M49.7 124.7h.4"/>
<path d="M49.7 122.1h.4M50.8 137.8h.4M50.8 135.1h.4M50.8 132.6h.4M50.8 129.9h.4M50.8 127.3h.4M50.8 124.7h.4M50.8 122.1h.4M51.9 137.8h.3M51.9 135.1h.3M51.9 132.6h.3M51.9 129.9h.3"/>
<path d="M51.9 127.3h.3M51.9 124.7h.3M51.9 122.1h.3M53 137.8h.3M53 135.1h.3M53 132.6h.3M53 129.9h.3M53 127.3h.3M53 124.7h.3M53 122.1h.3M54 137.8h.4M54 135.1h.4"/>
<path d="M54 132.6h.4M54 129.9h.4M54 127.3h.4M54 124.7h.4M54 122.1h.4M55.1 137.8h.4M55.1 135.1h.4M55.1 132.6h.4M55.1 129.9h.4M55.1 127.3h.4M55.1 124.7h.4M55.1 122.1h.4"/>
<path d="M56.2 137.8h.4M56.2 135.1h.4M56.2 132.6h.4M56.2 129.9h.4M56.2 127.3h.4M56.2 124.7h.4M56.2 122.1h.4M57.3 137.8h.3M57.3 135.1h.3M57.3 132.6h.3M57.3 129.9h.3M57.3 127.3h.3"/>
<path d="M57.3 124.7h.3M57.3 122.1h.3M58.4 137.8h.3M58.4 135.1h.3M58.4 132.6h.3M58.4 129.9h.3M58.4 127.3h.3M58.4 124.7h.3M58.4 122.1h.3M59.4 137.8h.4M59.4 135.1h.4M59.4 132.6h.4"/>
<path d="M59.4 129.9h.4M59.4 127.3h.4M59.4 124.7h.4M59.4 122.1h.4M60.5 137.8h.4M60.5 135.1h.4M60.5 132.6h.4M60.5 129.9h.4M60.5 127.3h.4M60.5 124.7h.4M60.5 122.1h.4M61.6 137.8h.4"/>
<path d="M61.6 135.1h.4M61.6 132.6h.4M61.6 129.9h.4M61.6 127.3h.4M61.6 124.7h.4M61.6 122.1h.4M62.7 137.8h.3M62.7 135.1h.3M62.7 132.6h.3M62.7 129.9h.3M62.7 127.3h.3M62.7 124.7h.3"/>
<path d="M62.7 122.1h.3M63.8 137.8h.3M63.8 135.1h.3M63.8 132.6h.3M63.8 129.9h.3M63.8 127.3h.3M63.8 124.7h.3M63.8 122.1h.3M64.8 137.8h.4M64.8 135.1h.4M64.8 132.6h.4M64.8 129.9h.4"/>
<path d="M64.8 127.3h.4M64.8 124.7h.4M64.8 122.1h.4M65.9 137.8h.4M65.9 135.1h.4M65.9 132.6h.4M65.9 129.9h.4M65.9 127.3h.4M65.9 124.7h.4M65.9 122.1h.4M67 137.8h.4M67 135.1h.4"/>
<path d="M67 132.6h.4M67 129.9h.4M67 127.3h.4M67 124.7h.4M67 122.1h.4M68.1 137.8h.3M68.1 135.1h.3M68.1 132.6h.3M68.1 129.9h.3M68.1 127.3h.3M68.1 124.7h.3M68.1 122.1h.3"/>
<path d="M69.2 137.8h.3M69.2 135.1h.3M69.2 132.6h.3M69.2 129.9h.3M69.2 127.3h.3M69.2 124.7h.3M69.2 122.1h.3M70.2 137.8h.4M70.2 135.1h.4M70.2 132.6h.4M70.2 129.9h.4M70.2 127.3h.4"/>
<path d="M70.2 124.7h.4M70.2 122.1h.4M71.3 137.8h.4M71.3 135.1h.4M71.3 132.6h.4M71.3 129.9h.4M71.3 127.3h.4M71.3 124.7h.4M71.3 122.1h.4M72.4 137.8h.4M72.4 135.1h.4M72.4 132.6h.4"/>
<path d="M72.4 129.9h.4M72.4 127.3h.4M72.4 124.7h.4M72.4 122.1h.4M73.5 137.8h.3M73.5 135.1h.3M73.5 132.6h.3M73.5 129.9h.3M73.5 127.3h.3M73.5 124.7h.3M73.5 122.1h.3M74.6 137.8h.3"/>
<path d="M74.6 135.1h.3M74.6 132.6h.3M74.6 129.9h.3M74.6 127.3h.3M74.6 124.7h.3M74.6 122.1h.3M75.6 137.8h.4M75.6 135.1h.4M75.6 132.6h.4M75.6 129.9h.4M75.6 127.3h.4M75.6 124.7h.4"/>
<path d="M75.6 122.1h.4M76.7 137.8h.4M76.7 135.1h.4M76.7 132.6h.4M76.7 129.9h.4M76.7 127.3h.4M76.7 124.7h.4M76.7 122.1h.4M77.8 137.8h.4M77.8 135.1h.4M77.8 132.6h.4M77.8 129.9h.4"/>
<path d="M77.8 127.3h.4M77.8 124.7h.4M77.8 122.1h.4M78.9 137.8h.3M78.9 135.1h.3M78.9 132.6h.3M78.9 129.9h.3M78.9 127.3h.3M78.9 124.7h.3M78.9 122.1h.3M80 137.8h.3M80 135.1h.3"/>
<path d="M80 132.6h.3M80 129.9h.3M80 127.3h.3M80 124.7h.3M80 122.1h.3M81 137.8h.4M81 135.1h.4M81 132.6h.4M81 129.9h.4M81 127.3h.4M81 124.7h.4M81 122.1h.4"/>
<path d="M25.6 145.5h.7M25.6 143h.7M25.6 140.3h.7M25.6 148.2h56M26 147h.2M26 144.3h.2M26 141.7h.2M27.1 145.5h.3M27.1 143h.3M27.1 140.3h.3M28.1 145.5h.4M28.1 143h.4"/>
<path d="M28.1 140.3h.4M29.2 145.5h.4M29.2 143h.4M29.2 140.3h.4M30.3 145.5h.4M30.3 143h.4M30.3 140.3h.4M30.7 148v.2M31.4 145.5h.3M31.4 143h.3M31.4 140.3h.3M32.5 145.5h.3"/>
<path d="M32.5 143h.3M32.5 140.3h.3M33.5 145.5h.4M33.5 143h.4M33.5 140.3h.4M34.6 145.5h.4M34.6 143h.4M34.6 140.3h.4M35.3 148v.6M35.7 145.5h.4M35.7 143h.4M35.7 140.3h.4"/>
<path d="M36.8 145.5h.3M36.8 143h.3M36.8 140.3h.3M37.8 145.5h.4M37.8 143h.4M37.8 140.3h.4M38.9 145.5h.4M38.9 143h.4M38.9 140.3h.4M39.8 148v.2M40 145.5h.4M40 143h.4"/>
<path d="M40 140.3h.4M41.1 145.5h.3M41.1 143h.3M41.1 140.3h.3M42.2 145.5h.3M42.2 143h.3M42.2 140.3h.3M43.2 145.5h.4M43.2 143h.4M43.2 140.3h.4M44.3 145.5h.4M44.3 143h.4"/>
<path d="M44.3 140.3h.4M44.5 148v.6M45.4 145.5h.4M45.4 143h.4M45.4 140.3h.4M46.5 145.5h.3M46.5 143h.3M46.5 140.3h.3M47.6 145.5h.3M47.6 143h.3M47.6 140.3h.3M48.6 145.5h.4"/>
<path d="M48.6 143h.4M48.6 140.3h.4M49.2 148v.2M49.7 145.5h.4M49.7 143h.4M49.7 140.3h.4M50.8 145.5h.4M50.8 143h.4M50.8 140.3h.4M51.9 145.5h.3M51.9 143h.3M51.9 140.3h.3"/>
<path d="M53 145.5h.3M53 143h.3M53 140.3h.3M53.9 148v.6M54 145.5h.4M54 143h.4M54 140.3h.4M55.1 145.5h.4M55.1 143h.4M55.1 140.3h.4M56.2 145.5h.4M56.2 143h.4"/>
<path d="M56.2 140.3h.4M57.3 145.5h.3M57.3 143h.3M57.3 140.3h.3M58.4 145.5h.3M58.4 143h.3M58.4 140.3h.3M58.4 148v.2M59.4 145.5h.4M59.4 143h.4M59.4 140.3h.4M60.5 145.5h.4"/>
<path d="M60.5 143h.4M60.5 140.3h.4M61.6 145.5h.4M61.6 143h.4M61.6 140.3h.4M62.7 145.5h.3M62.7 143h.3M62.7 140.3h.3M63 148v.6M63.8 145.5h.3M63.8 143h.3M63.8 140.3h.3"/>
<path d="M64.8 145.5h.4M64.8 143h.4M64.8 140.3h.4M65.9 145.5h.4M65.9 143h.4M65.9 140.3h.4M67 145.5h.4M67 143h.4M67 140.3h.4M67.7 148v.2M68.1 145.5h.3M68.1 143h.3"/>
<path d="M68.1 140.3h.3M69.2 145.5h.3M69.2 143h.3M69.2 140.3h.3M70.2 145.5h.4M70.2 143h.4M70.2 140.3h.4M71.3 145.5h.4M71.3 143h.4M71.3 140.3h.4M72.4 145.5h.4M72.4 143h.4"/>
<path d="M72.4 140.3h.4M72.4 148v.6M73.5 145.5h.3M73.5 143h.3M73.5 140.3h.3M74.6 145.5h.3M74.6 143h.3M74.6 140.3h.3M75.6 145.5h.4M75.6 143h.4M75.6 140.3h.4M76.7 145.5h.4"/>
<path d="M76.7 143h.4M76.7 140.3h.4M76.9 148v.2M77.8 145.5h.4M77.8 143h.4M77.8 140.3h.4M78.9 145.5h.3M78.9 143h.3M78.9 140.3h.3M80 145.5h.3M80 143h.3M80 140.3h.3"/>
<path d="M81 145.5h.4M81 143h.4M81 140.3h.4M81.6 148v.6"/>
</g>
<path d="M26 122.1h55.6v26.1h-55.6z" fill="none" stroke="#949698" stroke-width=".18"/>
<path d="M30.1 125.8h12.8v3.3h-12.8z" fill="#fff" stroke="#231f20" stroke-width=".16"/>
<path d="M31.5 127.3h4.1M43 134.6h1.4l1.3 .2M51.1 135.2l.7 .2 3.4 .3M113.8 133.8h-6.1l-3.1 .2-3.1 .3M122.4 134.5h1.1l.9 .2h2l2.1 .4a65.3 65.3 0 0 1 12.4 2.8l9.2 3.3 3.1 1.2 3 1.5M73.7 140.4l3.3 1.6" fill="none" stroke="#231f20" stroke-width=".36"/>
<g fill="none" stroke="#231f20" stroke-width=".16">
<path d="M101.3 139.8h.7M101.3 137.3h.7M101.3 134.8h.7M101.3 132.3h.7M101.3 129.7h.7M101.3 127h.7M101.3 124.5h.7M101.3 122h.7M101.6 122v25.9M101.6 138.6h.4M101.6 136h.4M101.6 133.5h.4"/>
<path d="M101.6 131h.4M101.6 128.3h.4M101.6 125.8h.4M101.6 123.3h.4M102.7 139.8h.4M102.7 137.3h.4M102.7 134.8h.4M102.7 132.3h.4M102.7 129.7h.4M102.7 127h.4M102.7 124.5h.4M102.7 122h.4"/>
<path d="M103.8 139.8h.4M103.8 137.3h.4M103.8 134.8h.4M103.8 132.3h.4M103.8 129.7h.4M103.8 127h.4M103.8 124.5h.4M103.8 122h.4M104.9 139.8h.3M104.9 137.3h.3M104.9 134.8h.3M104.9 132.3h.3"/>
<path d="M104.9 129.7h.3M104.9 127h.3M104.9 124.5h.3M104.9 122h.3M106 139.8h.3M106 137.3h.3M106 134.8h.3M106 132.3h.3M106 129.7h.3M106 127h.3M106 124.5h.3M106 122h.3"/>
<path d="M107 139.8h.4M107 137.3h.4M107 134.8h.4M107 132.3h.4M107 129.7h.4M107 127h.4M107 124.5h.4M107 122h.4M108.1 139.8h.4M108.1 137.3h.4M108.1 134.8h.4M108.1 132.3h.4"/>
<path d="M108.1 129.7h.4M108.1 127h.4M108.1 124.5h.4M108.1 122h.4M109.2 139.8h.3M109.2 137.3h.3M109.2 134.8h.3M109.2 132.3h.3M109.2 129.7h.3M109.2 127h.3M109.2 124.5h.3M109.2 122h.3"/>
<path d="M110.3 139.8h.3M110.3 137.3h.3M110.3 134.8h.3M110.3 132.3h.3M110.3 129.7h.3M110.3 127h.3M110.3 124.5h.3M110.3 122h.3M111.3 139.8h.4M111.3 137.3h.4M111.3 134.8h.4M111.3 132.3h.4"/>
<path d="M111.3 129.7h.4M111.3 127h.4M111.3 124.5h.4M111.3 122h.4M112.4 139.8h.4M112.4 137.3h.4M112.4 134.8h.4M112.4 132.3h.4M112.4 129.7h.4M112.4 127h.4M112.4 124.5h.4M112.4 122h.4"/>
<path d="M113.5 139.8h.4M113.5 137.3h.4M113.5 134.8h.4M113.5 132.3h.4M113.5 129.7h.4M113.5 127h.4M113.5 124.5h.4M113.5 122h.4M114.6 139.8h.3M114.6 137.3h.3M114.6 134.8h.3M114.6 132.3h.3"/>
<path d="M114.6 129.7h.3M114.6 127h.3M114.6 124.5h.3M114.6 122h.3M115.7 139.8h.3M115.7 137.3h.3M115.7 134.8h.3M115.7 132.3h.3M115.7 129.7h.3M115.7 127h.3M115.7 124.5h.3M115.7 122h.3"/>
<path d="M116.7 139.8h.4M116.7 137.3h.4M116.7 134.8h.4M116.7 132.3h.4M116.7 129.7h.4M116.7 127h.4M116.7 124.5h.4M116.7 122h.4M117.8 139.8h.4M117.8 137.3h.4M117.8 134.8h.4M117.8 132.3h.4"/>
<path d="M117.8 129.7h.4M117.8 127h.4M117.8 124.5h.4M117.8 122h.4M118.9 139.8h.4M118.9 137.3h.4M118.9 134.8h.4M118.9 132.3h.4M118.9 129.7h.4M118.9 127h.4M118.9 124.5h.4M118.9 122h.4"/>
<path d="M120 139.8h.3M120 137.3h.3M120 134.8h.3M120 132.3h.3M120 129.7h.3M120 127h.3M120 124.5h.3M120 122h.3M121.1 139.8h.3M121.1 137.3h.3M121.1 134.8h.3M121.1 132.3h.3"/>
<path d="M121.1 129.7h.3M121.1 127h.3M121.1 124.5h.3M121.1 122h.3M122.1 139.8h.4M122.1 137.3h.4M122.1 134.8h.4M122.1 132.3h.4M122.1 129.7h.4M122.1 127h.4M122.1 124.5h.4M122.1 122h.4"/>
<path d="M123.2 139.8h.4M123.2 137.3h.4M123.2 134.8h.4M123.2 132.3h.4M123.2 129.7h.4M123.2 127h.4M123.2 124.5h.4M123.2 122h.4M124.3 139.8h.4M124.3 137.3h.4M124.3 134.8h.4M124.3 132.3h.4"/>
<path d="M124.3 129.7h.4M124.3 127h.4M124.3 124.5h.4M124.3 122h.4M125.4 139.8h.3M125.4 137.3h.3M125.4 134.8h.3M125.4 132.3h.3M125.4 129.7h.3M125.4 127h.3M125.4 124.5h.3M125.4 122h.3"/>
<path d="M126.5 139.8h.3M126.5 137.3h.3M126.5 134.8h.3M126.5 132.3h.3M126.5 129.7h.3M126.5 127h.3M126.5 124.5h.3M126.5 122h.3M127.5 139.8h.4M127.5 137.3h.4M127.5 134.8h.4M127.5 132.3h.4"/>
<path d="M127.5 129.7h.4M127.5 127h.4M127.5 124.5h.4M127.5 122h.4M128.6 139.8h.4M128.6 137.3h.4M128.6 134.8h.4M128.6 132.3h.4M128.6 129.7h.4M128.6 127h.4M128.6 124.5h.4M128.6 122h.4"/>
<path d="M129.7 139.8h.4M129.7 137.3h.4M129.7 134.8h.4M129.7 132.3h.4M129.7 129.7h.4M129.7 127h.4M129.7 124.5h.4M129.7 122h.4M130.8 139.8h.3M130.8 137.3h.3M130.8 134.8h.3M130.8 132.3h.3"/>
<path d="M130.8 129.7h.3M130.8 127h.3M130.8 124.5h.3M130.8 122h.3M131.9 139.8h.3M131.9 137.3h.3M131.9 134.8h.3M131.9 132.3h.3M131.9 129.7h.3M131.9 127h.3M131.9 124.5h.3M131.9 122h.3"/>
<path d="M132.9 139.8h.4M132.9 137.3h.4M132.9 134.8h.4M132.9 132.3h.4M132.9 129.7h.4M132.9 127h.4M132.9 124.5h.4M132.9 122h.4M134 139.8h.4M134 137.3h.4M134 134.8h.4M134 132.3h.4"/>
<path d="M134 129.7h.4M134 127h.4M134 124.5h.4M134 122h.4M135.1 139.8h.4M135.1 137.3h.4M135.1 134.8h.4M135.1 132.3h.4M135.1 129.7h.4M135.1 127h.4M135.1 124.5h.4M135.1 122h.4"/>
<path d="M136.2 139.8h.3M136.2 137.3h.3M136.2 134.8h.3M136.2 132.3h.3M136.2 129.7h.3M136.2 127h.3M136.2 124.5h.3M136.2 122h.3M137.3 139.8h.3M137.3 137.3h.3M137.3 134.8h.3M137.3 132.3h.3"/>
<path d="M137.3 129.7h.3M137.3 127h.3M137.3 124.5h.3M137.3 122h.3M138.3 139.8h.4M138.3 137.3h.4M138.3 134.8h.4M138.3 132.3h.4M138.3 129.7h.4M138.3 127h.4M138.3 124.5h.4M138.3 122h.4"/>
<path d="M139.4 139.8h.4M139.4 137.3h.4M139.4 134.8h.4M139.4 132.3h.4M139.4 129.7h.4M139.4 127h.4M139.4 124.5h.4M139.4 122h.4M140.5 139.8h.4M140.5 137.3h.4M140.5 134.8h.4M140.5 132.3h.4"/>
<path d="M140.5 129.7h.4M140.5 127h.4M140.5 124.5h.4M140.5 122h.4M141.6 139.8h.3M141.6 137.3h.3M141.6 134.8h.3M141.6 132.3h.3M141.6 129.7h.3M141.6 127h.3M141.6 124.5h.3M141.6 122h.3"/>
<path d="M142.7 139.8h.3M142.7 137.3h.3M142.7 134.8h.3M142.7 132.3h.3M142.7 129.7h.3M142.7 127h.3M142.7 124.5h.3M142.7 122h.3M143.7 139.8h.4M143.7 137.3h.4M143.7 134.8h.4M143.7 132.3h.4"/>
<path d="M143.7 129.7h.4M143.7 127h.4M143.7 124.5h.4M143.7 122h.4M144.8 139.8h.4M144.8 137.3h.4M144.8 134.8h.4M144.8 132.3h.4M144.8 129.7h.4M144.8 127h.4M144.8 124.5h.4M144.8 122h.4"/>
<path d="M145.9 139.8h.4M145.9 137.3h.4M145.9 134.8h.4M145.9 132.3h.4M145.9 129.7h.4M145.9 127h.4M145.9 124.5h.4M145.9 122h.4M147 139.8h.3M147 137.3h.3M147 134.8h.3M147 132.3h.3"/>
<path d="M147 129.7h.3M147 127h.3M147 124.5h.3M147 122h.3M148.1 139.8h.3M148.1 137.3h.3M148.1 134.8h.3M148.1 132.3h.3M148.1 129.7h.3M148.1 127h.3M148.1 124.5h.3M148.1 122h.3"/>
<path d="M149.1 139.8h.4M149.1 137.3h.4M149.1 134.8h.4M149.1 132.3h.4M149.1 129.7h.4M149.1 127h.4M149.1 124.5h.4M149.1 122h.4M150.2 139.8h.4M150.2 137.3h.4M150.2 134.8h.4M150.2 132.3h.4"/>
<path d="M150.2 129.7h.4M150.2 127h.4M150.2 124.5h.4M150.2 122h.4M151.3 139.8h.3M151.3 137.3h.3M151.3 134.8h.3M151.3 132.3h.3M151.3 129.7h.3M151.3 127h.3M151.3 124.5h.3M151.3 122h.3"/>
<path d="M152.4 139.8h.3M152.4 137.3h.3M152.4 134.8h.3M152.4 132.3h.3M152.4 129.7h.3M152.4 127h.3M152.4 124.5h.3M152.4 122h.3M153.4 139.8h.4M153.4 137.3h.4M153.4 134.8h.4M153.4 132.3h.4"/>
<path d="M153.4 129.7h.4M153.4 127h.4M153.4 124.5h.4M153.4 122h.4M154.5 139.8h.4M154.5 137.3h.4M154.5 134.8h.4M154.5 132.3h.4M154.5 129.7h.4M154.5 127h.4M154.5 124.5h.4M154.5 122h.4"/>
<path d="M155.6 139.8h.4M155.6 137.3h.4M155.6 134.8h.4M155.6 132.3h.4M155.6 129.7h.4M155.6 127h.4M155.6 124.5h.4M155.6 122h.4M101.3 145h.7M101.3 142.5h.7M101.3 147.6h55M101.6 146.3h.4"/>
<path d="M101.6 143.8h.4M101.6 141.1h.4M102.7 145h.4M102.7 142.5h.4M103.8 145h.4M103.8 142.5h.4M104.9 145h.3M104.9 142.5h.3M106 145h.3M106 142.5h.3M106.1 147.2v.4M107 145h.4"/>
<path d="M107 142.5h.4M108.1 145h.4M108.1 142.5h.4M109.2 145h.3M109.2 142.5h.3M110.3 145h.3M110.3 142.5h.3M110.8 147.2v.7M111.3 145h.4M111.3 142.5h.4M112.4 145h.4M112.4 142.5h.4"/>
<path d="M113.5 145h.4M113.5 142.5h.4M114.6 145h.3M114.6 142.5h.3M115.3 147.2v.4M115.7 145h.3M115.7 142.5h.3M116.7 145h.4M116.7 142.5h.4M117.8 145h.4M117.8 142.5h.4M118.9 145h.4"/>
<path d="M118.9 142.5h.4M119.8 147.2v.7M120 145h.3M120 142.5h.3M121.1 145h.3M121.1 142.5h.3M122.1 145h.4M122.1 142.5h.4M123.2 145h.4M123.2 142.5h.4M124.3 145h.4M124.3 142.5h.4"/>
<path d="M124.5 147.2v.4M125.4 145h.3M125.4 142.5h.3M126.5 145h.3M126.5 142.5h.3M127.5 145h.4M127.5 142.5h.4M128.6 145h.4M128.6 142.5h.4M129 147.2v.7M129.7 145h.4M129.7 142.5h.4"/>
<path d="M130.8 145h.3M130.8 142.5h.3M131.9 145h.3M131.9 142.5h.3M132.9 145h.4M132.9 142.5h.4M133.5 147.2v.4M134 145h.4M134 142.5h.4M135.1 145h.4M135.1 142.5h.4M136.2 145h.3"/>
<path d="M136.2 142.5h.3M137.3 145h.3M137.3 142.5h.3M138.2 147.2v.7M138.3 145h.4M138.3 142.5h.4M139.4 145h.4M139.4 142.5h.4M140.5 145h.4M140.5 142.5h.4M141.6 145h.3M141.6 142.5h.3"/>
<path d="M142.7 145h.3M142.7 142.5h.3M142.7 147.2v.4M143.7 145h.4M143.7 142.5h.4M144.8 145h.4M144.8 142.5h.4M145.9 145h.4M145.9 142.5h.4M147 145h.3M147 142.5h.3M147.2 147.2v.7"/>
<path d="M148.1 145h.3M148.1 142.5h.3M149.1 145h.4M149.1 142.5h.4M150.2 145h.4M150.2 142.5h.4M151.3 145h.3M151.3 142.5h.3M151.8 147.2v.4M152.4 145h.3M152.4 142.5h.3M153.4 145h.4"/>
<path d="M153.4 142.5h.4M154.5 145h.4M154.5 142.5h.4M155.6 145h.4M155.6 142.5h.4M156.3 147.2v.7"/>
</g>
<path d="M101.6 122h54.7v25.6" fill="none" stroke="#231f20" stroke-width=".18"/>
<path d="M101.6 122v25.6h54.7" fill="none" stroke="#949698" stroke-width=".18"/>
<path d="M105.2 125.2h11.6v3.7h-11.6z" fill="#fff"/>
<g fill="none" stroke="#231f20" stroke-width=".16">
<path d="M105.2 125.2h11.6v3.7h-11.6zM27.7 176.9h.7M27.7 172.7h.7M28 172.7v25.8M28 179h.4M28 174.9h.4M29.1 176.9h.4M29.1 172.7h.4M30.2 176.9h.3M30.2 172.7h.3M31.3 176.9h.3M31.3 172.7h.3"/>
<path d="M32.3 176.9h.4M32.3 172.7h.4M33.4 176.9h.4M33.4 172.7h.4M34.5 176.9h.4M34.5 172.7h.4M35.6 176.9h.3M35.6 172.7h.3M36.7 176.9h.3M36.7 172.7h.3M37.7 176.9h.4M37.7 172.7h.4"/>
<path d="M38.8 176.9h.4M38.8 172.7h.4M39.9 176.9h.4M39.9 172.7h.4M41 176.9h.3M41 172.7h.3M42.1 176.9h.3M42.1 172.7h.3M43.1 176.9h.4M43.1 172.7h.4M44.2 176.9h.4M44.2 172.7h.4"/>
<path d="M45.3 176.9h.4M45.3 172.7h.4M46.4 176.9h.3M46.4 172.7h.3M47.5 176.9h.3M47.5 172.7h.3M48.5 176.9h.4M48.5 172.7h.4M49.6 176.9h.4M49.6 172.7h.4M50.7 176.9h.4M50.7 172.7h.4"/>
<path d="M51.8 176.9h.3M51.8 172.7h.3M52.9 176.9h.3M52.9 172.7h.3M53.9 176.9h.4M53.9 172.7h.4M55 176.9h.4M55 172.7h.4M56.1 176.9h.3M56.1 172.7h.3M57.2 176.9h.3M57.2 172.7h.3"/>
<path d="M58.2 176.9h.4M58.2 172.7h.4M59.3 176.9h.4M59.3 172.7h.4M60.4 176.9h.4M60.4 172.7h.4M61.5 176.9h.3M61.5 172.7h.3M62.6 176.9h.3M62.6 172.7h.3M63.6 176.9h.4M63.6 172.7h.4"/>
<path d="M64.7 176.9h.4M64.7 172.7h.4M65.8 176.9h.4M65.8 172.7h.4M66.9 176.9h.3M66.9 172.7h.3M68 176.9h.3M68 172.7h.3M69 176.9h.4M69 172.7h.4M70.1 176.9h.4M70.1 172.7h.4"/>
<path d="M71.2 176.9h.4M71.2 172.7h.4M72.3 176.9h.3M72.3 172.7h.3M73.4 176.9h.3M73.4 172.7h.3M74.4 176.9h.4M74.4 172.7h.4M75.5 176.9h.4M75.5 172.7h.4M76.6 176.9h.4M76.6 172.7h.4"/>
<path d="M77.7 176.9h.3M77.7 172.7h.3M78.8 176.9h.3M78.8 172.7h.3M79.8 176.9h.4M79.8 172.7h.4M27.7 193.8h.7M27.7 189.6h.7M27.7 185.3h.7M27.7 181.2h.7M27.7 198.1h53.2M28 195.9h.4"/>
<path d="M28 191.8h.4M28 187.5h.4M28 183.3h.4M29.1 193.8h.4M29.1 189.6h.4M29.1 185.3h.4M29.1 181.2h.4M30.2 193.8h.3M30.2 189.6h.3M30.2 185.3h.3M30.2 181.2h.3M31.3 193.8h.3"/>
<path d="M31.3 189.6h.3M31.3 185.3h.3M31.3 181.2h.3M32.3 193.8h.4M32.3 189.6h.4M32.3 185.3h.4M32.3 181.2h.4M33.4 193.8h.4M33.4 189.6h.4M33.4 185.3h.4M33.4 181.2h.4M34.5 193.8h.4"/>
<path d="M34.5 189.6h.4M34.5 185.3h.4M34.5 181.2h.4M34.7 197.7v.4M35.6 193.8h.3M35.6 189.6h.3M35.6 185.3h.3M35.6 181.2h.3M36.7 193.8h.3M36.7 189.6h.3M36.7 185.3h.3M36.7 181.2h.3"/>
<path d="M37.7 193.8h.4M37.7 189.6h.4M37.7 185.3h.4M37.7 181.2h.4M38.8 193.8h.4M38.8 189.6h.4M38.8 185.3h.4M38.8 181.2h.4M39.9 193.8h.4M39.9 189.6h.4M39.9 185.3h.4M39.9 181.2h.4"/>
<path d="M41 193.8h.3M41 189.6h.3M41 185.3h.3M41 181.2h.3M41.3 197.7v.8M42.1 193.8h.3M42.1 189.6h.3M42.1 185.3h.3M42.1 181.2h.3M43.1 193.8h.4M43.1 189.6h.4M43.1 185.3h.4"/>
<path d="M43.1 181.2h.4M44.2 193.8h.4M44.2 189.6h.4M44.2 185.3h.4M44.2 181.2h.4M45.3 193.8h.4M45.3 189.6h.4M45.3 185.3h.4M45.3 181.2h.4M46.4 193.8h.3M46.4 189.6h.3M46.4 185.3h.3"/>
<path d="M46.4 181.2h.3M47.5 193.8h.3M47.5 189.6h.3M47.5 185.3h.3M47.5 181.2h.3M47.8 197.7v.4M48.5 193.8h.4M48.5 189.6h.4M48.5 185.3h.4M48.5 181.2h.4M49.6 193.8h.4M49.6 189.6h.4"/>
<path d="M49.6 185.3h.4M49.6 181.2h.4M50.7 193.8h.4M50.7 189.6h.4M50.7 185.3h.4M50.7 181.2h.4M51.8 193.8h.3M51.8 189.6h.3M51.8 185.3h.3M51.8 181.2h.3M52.9 193.8h.3M52.9 189.6h.3"/>
<path d="M52.9 185.3h.3M52.9 181.2h.3M53.9 193.8h.4M53.9 189.6h.4M53.9 185.3h.4M53.9 181.2h.4M54.5 197.7v.8M55 193.8h.4M55 189.6h.4M55 185.3h.4M55 181.2h.4M56.1 193.8h.3"/>
<path d="M56.1 189.6h.3M56.1 185.3h.3M56.1 181.2h.3M57.2 193.8h.3M57.2 189.6h.3M57.2 185.3h.3M57.2 181.2h.3M58.2 193.8h.4M58.2 189.6h.4M58.2 185.3h.4M58.2 181.2h.4M59.3 193.8h.4"/>
<path d="M59.3 189.6h.4M59.3 185.3h.4M59.3 181.2h.4M60.4 193.8h.4M60.4 189.6h.4M60.4 185.3h.4M60.4 181.2h.4M61.1 197.7v.4M61.5 193.8h.3M61.5 189.6h.3M61.5 185.3h.3M61.5 181.2h.3"/>
<path d="M62.6 193.8h.3M62.6 189.6h.3M62.6 185.3h.3M62.6 181.2h.3M63.6 193.8h.4M63.6 189.6h.4M63.6 185.3h.4M63.6 181.2h.4M64.7 193.8h.4M64.7 189.6h.4M64.7 185.3h.4M64.7 181.2h.4"/>
<path d="M65.8 193.8h.4M65.8 189.6h.4M65.8 185.3h.4M65.8 181.2h.4M66.9 193.8h.3M66.9 189.6h.3M66.9 185.3h.3M66.9 181.2h.3M67.8 197.7v.8M68 193.8h.3M68 189.6h.3M68 185.3h.3"/>
<path d="M68 181.2h.3M69 193.8h.4M69 189.6h.4M69 185.3h.4M69 181.2h.4M70.1 193.8h.4M70.1 189.6h.4M70.1 185.3h.4M70.1 181.2h.4M71.2 193.8h.4M71.2 189.6h.4M71.2 185.3h.4"/>
<path d="M71.2 181.2h.4M72.3 193.8h.3M72.3 189.6h.3M72.3 185.3h.3M72.3 181.2h.3M73.4 193.8h.3M73.4 189.6h.3M73.4 185.3h.3M73.4 181.2h.3M74.3 197.7v.4M74.4 193.8h.4M74.4 189.6h.4"/>
<path d="M74.4 185.3h.4M74.4 181.2h.4M75.5 193.8h.4M75.5 189.6h.4M75.5 185.3h.4M75.5 181.2h.4M76.6 193.8h.4M76.6 189.6h.4M76.6 185.3h.4M76.6 181.2h.4M77.7 193.8h.3M77.7 189.6h.3"/>
<path d="M77.7 185.3h.3M77.7 181.2h.3M78.8 193.8h.3M78.8 189.6h.3M78.8 185.3h.3M78.8 181.2h.3M79.8 193.8h.4M79.8 189.6h.4M79.8 185.3h.4M79.8 181.2h.4M80.9 197.7v.8"/>
</g>
<g fill="none" stroke="#231f20" stroke-width=".36">
<path d="M106 127h4.2M113.8 133.8l4.5 .2 4.1 .5M80.1 179.8l-2.1 1.3M80.8 177.1a36 36 0 0 1-16.3 7.2l-5.1 .8h-5l-6.7 .3-6.5 .2M30.4 186l-2.5 .1M32.1 197.5l-.2 .7M32.2 195.3v.7M32.6 193.1l-.2 .8M32.8 191l-.2 .7M33 194.4v.7M33 196.6v1M33.1 188.8l-.1 .7"/>
<path d="M33.1 190.4l-.1 2.6M33.1 196v.7M33.7 187.8l-.4-.2-.2 .3M34.6 187.9h.7M36.7 187.9h.8M37.1 185.6l-1.3 .2M37.1 189.9l-1.3 .2h-1.4l-.5-.2h-.6l-.2 .4M37.1 193.7l-2 .3h-1.2l-.6 .2-.2 .4M38.5 185.6h5.3M38.5 189.9h.8M38.5 193.7h.8M38.9 187.8h.7"/>
<path d="M39.4 185.6l-1.8 .2h-9.7M40.7 189.9h3.1M40.7 193.5h3.1M41.1 187.8h.9M43.4 187.8h.7M45.2 185.6h5M45.2 189.7h.7M45.2 193.5h.7M45.6 187.6h.7M47.4 189.7h2.8M47.4 193.5h2.8M47.7 187.6h.7"/>
<path d="M49.9 187.6h.7M51.7 185.4h2.5M51.7 189.5h.7M51.7 193.5h.7M52 187.4h.8M53.8 189.5h3.1M53.8 193.5l3.1 .2M54.2 187.4h.9M56.5 187.4h.8M56.9 185.2l-2.5 .2M58.3 189.4h.8M58.3 193.7h.8"/>
<path d="M58.7 187.4h.7M60.5 189.4h3.1M60.9 185.1l-2.6 .1M60.9 187.4h.9M63.2 187.2h.7M63.6 184.9l-2.6 .2M63.6 193.5l-3.1 .2M65 189.4h.7M65 193.5h.7M65.4 187h.7M67.2 189.4h3M67.2 193.5l3 .2"/>
<path d="M67.5 184.2l-2.5 .3M67.5 186.9h.9M69.9 186.7h.7M70.2 183.6l-2.5 .6M71.7 189.4h.7M71.7 193.7h.7M72 186.5h.7M73.8 193.9l2.9 .1M74.9 186.1l-.7 .2M76.5 181.6l-2.3 .9-2.5 .8M76.7 188.8l-2.9 .4M77.1 185.8l-.8 .2"/>
<path d="M78.1 188.6h.8M78.1 194h.8M79.2 185.4l-.7 .2M80.3 188.3h.5M80.3 194.2h.5M80.7 185.1h.1"/>
</g>
<path d="M28 172.7h52.9v25.4h-52.9z" fill="none" stroke="#949698" stroke-width=".18"/>
<path d="M30.2 173.8h17.4v10.6h-17.4z" fill="#fff" stroke="#231f20" stroke-width=".16"/>
<g fill="none" stroke="#231f20" stroke-width=".36">
<path d="M32.1 174.8h6.3M32.1 176.8h2.5M32.1 178.9h.7M34.2 178.9h.7M36 176.8h2.4M36.4 178.9h.7M101.9 172.8v1.6l.2 .5 .5 .6 2.5 1.6a37.8 37.8 0 0 0 10.1 5l13.7 4.7M32.1 180.9h2.5M32.1 183.1h2.5M36 180.9h.7M36 183.1h.7M38.2 180.9h.2"/>
<path d="M38.2 183.1h.2M101.9 180.5l.7 .4 3.6 .7M101.9 181.1h.9M103.7 181.2l.7 .2M105.9 181.8l.7 .2M107.7 182l2.5 .7M108 182.3l.7 .2M110.2 182.9l1.4 .3M110.9 182.9l2.5 .5M113.1 183.6l.7 .2M114.8 183.8l2.6 .5M115.2 183.9l.7 .2"/>
<path d="M117.4 184.5l.7 .2M118.8 184.7l3.6 .7M119.5 185l1.1 .2M122 185.4l.8 .2M123.8 185.6l2.6 .7M124.2 185.9l.7 .2M126.4 186.5l.7 .1M127.8 186.6l1.1 .2M128.5 187l1.1 .2M128.9 186.8l8.8 2.9 18 5M128.9 186.8l2.3 .7M131 187.5l.8 .2"/>
<path d="M132.7 187.9l.5 .2M133.2 188.1l2 .5M133.2 188.1l.7 .2M135.4 188.6l.7 .2M136.6 189l1.1 .3M137.5 189.3h.2M137.7 189.3l2.5 .6M137.7 189.3l.7 .2M139.9 189.9l.7 .2M141.7 190.2l.5 .2M142 190.4h.2M142.2 190.4l2 .6"/>
<path d="M142.2 190.4l.5 .2M144.2 190.8l.7 .2M145.6 191.3l3.6 .7M146.3 191.3l1.1 .2M148.9 191.9h.7M150.7 192.4l2.3 .5M151 192.2l.6 .2M153 192.8l.7 .1M154.4 193.3l1.3 .4M155.2 193.1l.5 .2"/>
</g>
<g fill="none" stroke="#231f20" stroke-width=".16">
<path d="M101.6 176.8h.7M101.6 172.7h.7M102 172.7v25.5M102 179h.3M102 174.8h.3M103.1 176.8h.3M103.1 172.7h.3M104.1 176.8h.4M104.1 172.7h.4M105.2 176.8h.4M105.2 172.7h.4M106.3 176.8h.4"/>
<path d="M106.3 172.7h.4M107.4 176.8h.3M107.4 172.7h.3M108.5 176.8h.3M108.5 172.7h.3M109.5 176.8h.4M109.5 172.7h.4M110.6 176.8h.4M110.6 172.7h.4M111.7 176.8h.4M111.7 172.7h.4M112.8 176.8h.3"/>
<path d="M112.8 172.7h.3M113.9 176.8h.3M113.9 172.7h.3M114.9 176.8h.4M114.9 172.7h.4M116 176.8h.4M116 172.7h.4M117.1 176.8h.4M117.1 172.7h.4M118.2 176.8h.3M118.2 172.7h.3M119.3 176.8h.3"/>
<path d="M119.3 172.7h.3M120.3 176.8h.4M120.3 172.7h.4M121.4 176.8h.4M121.4 172.7h.4M122.5 176.8h.4M122.5 172.7h.4M123.6 176.8h.3M123.6 172.7h.3M124.7 176.8h.3M124.7 172.7h.3M125.7 176.8h.4"/>
<path d="M125.7 172.7h.4M126.8 176.8h.4M126.8 172.7h.4M127.9 176.8h.4M127.9 172.7h.4M129 176.8h.3M129 172.7h.3M130.1 176.8h.3M130.1 172.7h.3M131.1 176.8h.4M131.1 172.7h.4M132.2 176.8h.4"/>
<path d="M132.2 172.7h.4M133.3 176.8h.4M133.3 172.7h.4M134.4 176.8h.3M134.4 172.7h.3M135.5 176.8h.3M135.5 172.7h.3M136.5 176.8h.4M136.5 172.7h.4M137.6 176.8h.4M137.6 172.7h.4M138.7 176.8h.3"/>
<path d="M138.7 172.7h.3M139.8 176.8h.3M139.8 172.7h.3M140.8 176.8h.4M140.8 172.7h.4M141.9 176.8h.4M141.9 172.7h.4M143 176.8h.4M143 172.7h.4M144.1 176.8h.3M144.1 172.7h.3M145.2 176.8h.3"/>
<path d="M145.2 172.7h.3M146.2 176.8h.4M146.2 172.7h.4M147.3 176.8h.4M147.3 172.7h.4M148.4 176.8h.4M148.4 172.7h.4M149.5 176.8h.3M149.5 172.7h.3M150.6 176.8h.3M150.6 172.7h.3M151.6 176.8h.4"/>
<path d="M151.6 172.7h.4M152.7 176.8h.4M152.7 172.7h.4M153.8 176.8h.4M153.8 172.7h.4M154.9 176.8h.3M154.9 172.7h.3M101.6 193.7h.7M101.6 189.4h.7M101.6 185.3h.7M101.6 181.1h.7M101.6 197.9h54.2"/>
<path d="M102 195.7h.3M102 191.6h.3M102 187.4h.3M102 183.1h.3M103.1 193.7h.3M103.1 189.4h.3M103.1 185.3h.3M103.1 181.1h.3M104.1 193.7h.4M104.1 189.4h.4M104.1 185.3h.4M104.1 181.1h.4"/>
<path d="M105.2 193.7h.4M105.2 189.4h.4M105.2 185.3h.4M105.2 181.1h.4M106.3 193.7h.4M106.3 189.4h.4M106.3 185.3h.4M106.3 181.1h.4M106.5 197.5v.4M107.4 193.7h.3M107.4 189.4h.3M107.4 185.3h.3"/>
<path d="M107.4 181.1h.3M108.5 193.7h.3M108.5 189.4h.3M108.5 185.3h.3M108.5 181.1h.3M109.5 193.7h.4M109.5 189.4h.4M109.5 185.3h.4M109.5 181.1h.4M110.6 193.7h.4M110.6 189.4h.4M110.6 185.3h.4"/>
<path d="M110.6 181.1h.4M111 197.5v.7M111.7 193.7h.4M111.7 189.4h.4M111.7 185.3h.4M111.7 181.1h.4M112.8 193.7h.3M112.8 189.4h.3M112.8 185.3h.3M112.8 181.1h.3M113.9 193.7h.3M113.9 189.4h.3"/>
<path d="M113.9 185.3h.3M113.9 181.1h.3M114.9 193.7h.4M114.9 189.4h.4M114.9 185.3h.4M114.9 181.1h.4M115.5 197.5v.4M116 193.7h.4M116 189.4h.4M116 185.3h.4M116 181.1h.4M117.1 193.7h.4"/>
<path d="M117.1 189.4h.4M117.1 185.3h.4M117.1 181.1h.4M118.2 193.7h.3M118.2 189.4h.3M118.2 185.3h.3M118.2 181.1h.3M119.3 193.7h.3M119.3 189.4h.3M119.3 185.3h.3M119.3 181.1h.3M120 197.5v.7"/>
<path d="M120.3 193.7h.4M120.3 189.4h.4M120.3 185.3h.4M120.3 181.1h.4M121.4 193.7h.4M121.4 189.4h.4M121.4 185.3h.4M121.4 181.1h.4M122.5 193.7h.4M122.5 189.4h.4M122.5 185.3h.4M122.5 181.1h.4"/>
<path d="M123.6 193.7h.3M123.6 189.4h.3M123.6 185.3h.3M123.6 181.1h.3M124.5 197.5v.4M124.7 193.7h.3M124.7 189.4h.3M124.7 185.3h.3M124.7 181.1h.3M125.7 193.7h.4M125.7 189.4h.4M125.7 185.3h.4"/>
<path d="M125.7 181.1h.4M126.8 193.7h.4M126.8 189.4h.4M126.8 185.3h.4M126.8 181.1h.4M127.9 193.7h.4M127.9 189.4h.4M127.9 185.3h.4M127.9 181.1h.4M128.8 197.5v.4M129 193.7h.3M129 189.4h.3"/>
<path d="M129 185.3h.3M129 181.1h.3M129 197.9v.3M130.1 193.7h.3M130.1 189.4h.3M130.1 185.3h.3M130.1 181.1h.3M131.1 193.7h.4M131.1 189.4h.4M131.1 185.3h.4M131.1 181.1h.4M132.2 193.7h.4"/>
<path d="M132.2 189.4h.4M132.2 185.3h.4M132.2 181.1h.4M133.3 193.7h.4M133.3 189.4h.4M133.3 185.3h.4M133.3 181.1h.4M133.3 197.5v.4M134.4 193.7h.3M134.4 189.4h.3M134.4 185.3h.3M134.4 181.1h.3"/>
<path d="M135.5 193.7h.3M135.5 189.4h.3M135.5 185.3h.3M135.5 181.1h.3M136.5 193.7h.4M136.5 189.4h.4M136.5 185.3h.4M136.5 181.1h.4M137.6 193.7h.4M137.6 189.4h.4M137.6 185.3h.4M137.6 181.1h.4"/>
<path d="M137.8 197.5v.7M138.7 193.7h.3M138.7 189.4h.3M138.7 185.3h.3M138.7 181.1h.3M139.8 193.7h.3M139.8 189.4h.3M139.8 185.3h.3M139.8 181.1h.3M140.8 193.7h.4M140.8 189.4h.4M140.8 185.3h.4"/>
<path d="M140.8 181.1h.4M141.9 193.7h.4M141.9 189.4h.4M141.9 185.3h.4M141.9 181.1h.4M142.3 197.5v.4M143 193.7h.4M143 189.4h.4M143 185.3h.4M143 181.1h.4M144.1 193.7h.3M144.1 189.4h.3"/>
<path d="M144.1 185.3h.3M144.1 181.1h.3M145.2 193.7h.3M145.2 189.4h.3M145.2 185.3h.3M145.2 181.1h.3M146.2 193.7h.4M146.2 189.4h.4M146.2 185.3h.4M146.2 181.1h.4M146.8 197.5v.7M147.3 193.7h.4"/>
<path d="M147.3 189.4h.4M147.3 185.3h.4M147.3 181.1h.4M148.4 193.7h.4M148.4 189.4h.4M148.4 185.3h.4M148.4 181.1h.4M149.5 193.7h.3M149.5 189.4h.3M149.5 185.3h.3M149.5 181.1h.3M150.6 193.7h.3"/>
<path d="M150.6 189.4h.3M150.6 185.3h.3M150.6 181.1h.3M151.3 197.5v.4M151.6 193.7h.4M151.6 189.4h.4M151.6 185.3h.4M151.6 181.1h.4M152.7 193.7h.4M152.7 189.4h.4M152.7 185.3h.4M152.7 181.1h.4"/>
<path d="M153.8 193.7h.4M153.8 189.4h.4M153.8 185.3h.4M153.8 181.1h.4M154.9 193.7h.3M154.9 189.4h.3M154.9 185.3h.3M154.9 181.1h.3M155.8 197.5v.7"/>
</g>
<path d="M102 172.7h53.8v25.2h-53.8" fill="none" stroke="#231f20" stroke-width=".18"/>
<path d="M102 172.7v25.2" fill="none" stroke="#949698" stroke-width=".18"/>
<path d="M138.7 173.8h15.1v7.3h-15.1z" fill="#fff" stroke="#231f20" stroke-width=".16"/>
<path d="M139.3 174.9h6.3M139.3 177.3h2.5M139.3 179.6h.7M141.5 179.6h.7M143.3 177.3h2.3M143.6 179.6h.8" fill="none" stroke="#231f20" stroke-width=".36"/>
<path d="M18 10.3h68.4" fill="none" stroke="#231f20" stroke-width=".7" stroke-linecap="butt"/>
<use href="#words"/>
</svg>
